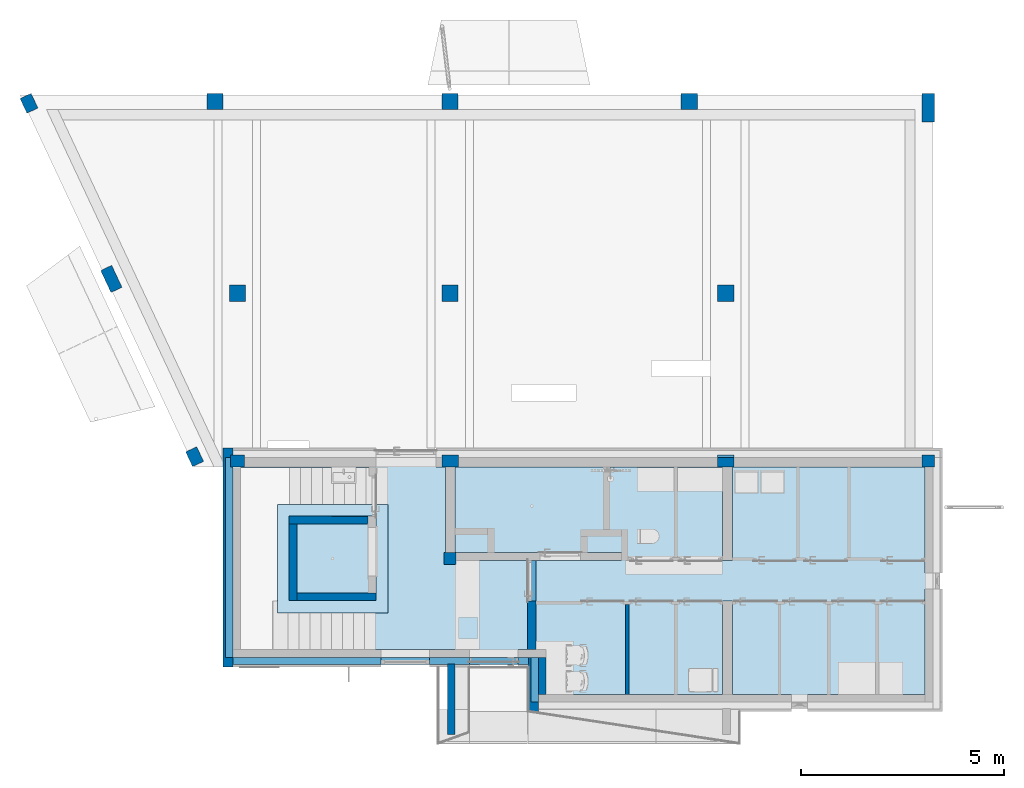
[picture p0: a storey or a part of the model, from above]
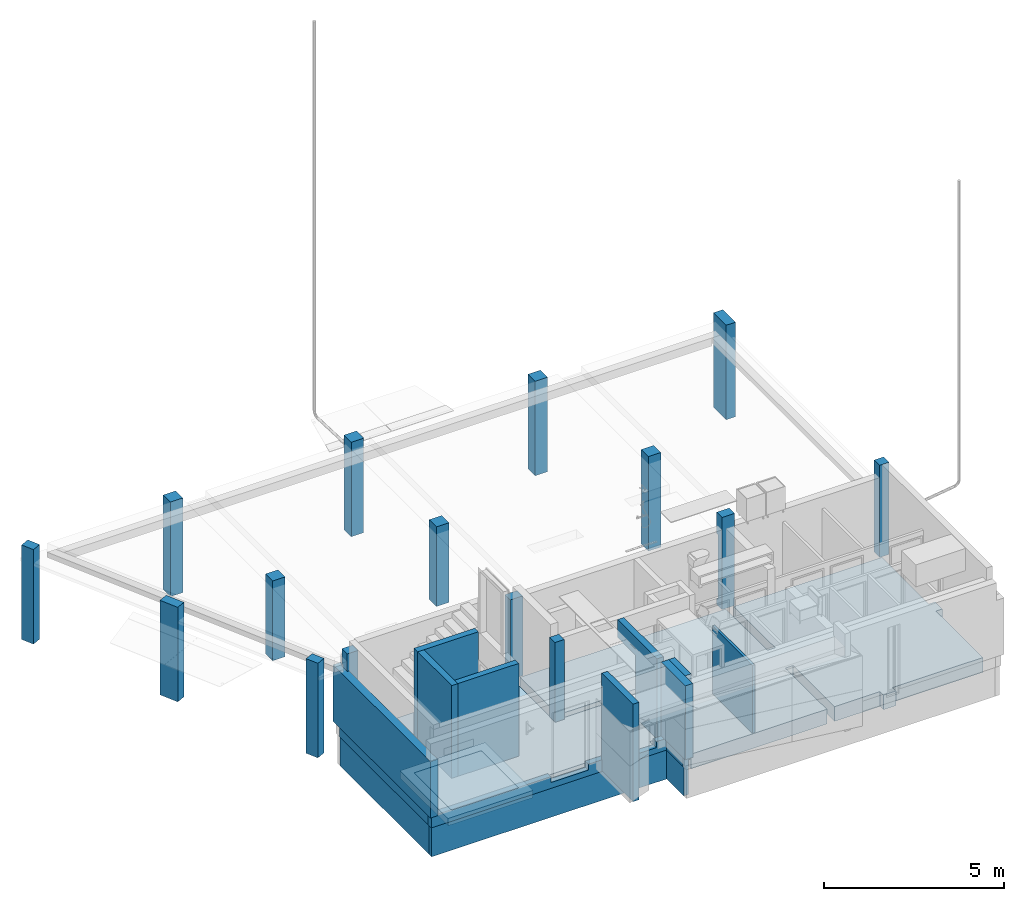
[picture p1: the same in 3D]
Properties of the parts of a building model (IFC2X3), part 1 of 3

# File
Description: ViewDefinition [CoordinationView_V2.0], RevitIdentifiers [ContentGUID: f1a5ce15-1688-4ac3-b104-60991c236845, VersionGUID: 6ece28bc-73fe-4a4b-b3da-6d619ce2e189, NumberOfSaves: 295], CoordinateReference [CoordinateBase: Shared Coordinates, ProjectSite: Internal]
File name: Kiili14_AR.ifc
Time: 2025-11-07T10:45:03+02:00
Written by: ODA SDAI 24.12
Made in: Autodesk Revit 25.4.20.11 (ENU) - IFC 25.4.20.11

# IfcProject, KLI1425
LongName: Kiili 14 korterelamu; Phase: PP

# IfcSite, Default
RefLatitude: 42, 24, 53, 508911; RefLongitude: -71, -15, -29, -58837; RefElevation: 0 mm

# IfcBuilding
Pset_BuildingCommon - NumberOfStoreys: 6

# IfcBuildingStorey: Level:Building Story. Project Base Point (6)
Pset_AirSideSystemInformation - sets with these values: 2
Name | LongName = Name | Elevation (mm)
1K | 1K | 0
2K | 2K | 3125
3K | 3K | 6295
4K | 4K | 9465
5K | 5K | 12811
Parapet | Parapet | 16500

# IfcSpace: Abir. 2-4.7:285176, 2-4.7
In: 2K
LongName: Abir.; InteriorOrExteriorSpace: INTERNAL
Pset_AirSideSystemInformation - Name: Abir.; sets with these values: 2
Pset_SpaceCommon - Reference: Abir. 2-4.7

# IfcSpace: Abir. 3-8.7:285861, 3-8.7
In: 3K
LongName: Abir.; InteriorOrExteriorSpace: INTERNAL
Pset_AirSideSystemInformation - Name: Abir.; sets with these values: 2
Pset_SpaceCommon - Reference: Abir. 3-8.7

# IfcSpace: Abiruum 5-12.9:296837, 5-12.9
In: 5K
LongName: Abiruum; InteriorOrExteriorSpace: INTERNAL
Pset_AirSideSystemInformation - Name: Abiruum; sets with these values: 2
Pset_SpaceCommon - Reference: Abiruum 5-12.9

# IfcSpace: Elutuba-köök 2-1.2:284823, 2-1.2
In: 2K
LongName: Elutuba-köök; InteriorOrExteriorSpace: INTERNAL
Pset_AirSideSystemInformation - Name: Elutuba-köök; sets with these values: 2
Pset_SpaceCommon - Reference: Elutuba-köök 2-1.2

# IfcSpace: Elutuba-köök 2-2.2:284964, 2-2.2
In: 2K
LongName: Elutuba-köök; InteriorOrExteriorSpace: INTERNAL
Pset_AirSideSystemInformation - Name: Elutuba-köök; sets with these values: 2
Pset_SpaceCommon - Reference: Elutuba-köök 2-2.2

# IfcSpace: Elutuba-köök 2-3.2:284970, 2-3.2
In: 2K
LongName: Elutuba-köök; InteriorOrExteriorSpace: INTERNAL
Pset_AirSideSystemInformation - Name: Elutuba-köök; sets with these values: 2
Pset_SpaceCommon - Reference: Elutuba-köök 2-3.2

# IfcSpace: Elutuba-köök 2-4.2:285173, 2-4.2
In: 2K
LongName: Elutuba-köök; InteriorOrExteriorSpace: INTERNAL
Pset_AirSideSystemInformation - Name: Elutuba-köök; sets with these values: 2
Pset_SpaceCommon - Reference: Elutuba-köök 2-4.2

# IfcSpace: Elutuba-köök 3-5.2:285785, 3-5.2
In: 3K
LongName: Elutuba-köök; InteriorOrExteriorSpace: INTERNAL
Pset_AirSideSystemInformation - Name: Elutuba-köök; sets with these values: 2
Pset_SpaceCommon - Reference: Elutuba-köök 3-5.2

# IfcSpace: Elutuba-köök 3-6.2:285788, 3-6.2
In: 3K
LongName: Elutuba-köök; InteriorOrExteriorSpace: INTERNAL
Pset_AirSideSystemInformation - Name: Elutuba-köök; sets with these values: 2
Pset_SpaceCommon - Reference: Elutuba-köök 3-6.2

# IfcSpace: Elutuba-köök 3-7.2:285791, 3-7.2
In: 3K
LongName: Elutuba-köök; InteriorOrExteriorSpace: INTERNAL
Pset_AirSideSystemInformation - Name: Elutuba-köök; sets with these values: 2
Pset_SpaceCommon - Reference: Elutuba-köök 3-7.2

# IfcSpace: Elutuba-köök 3-8.2:285794, 3-8.2
In: 3K
LongName: Elutuba-köök; InteriorOrExteriorSpace: INTERNAL
Pset_AirSideSystemInformation - Name: Elutuba-köök; sets with these values: 2
Pset_SpaceCommon - Reference: Elutuba-köök 3-8.2

# IfcSpace: Elutuba-köök 4-10.2:295655, 4-10.2
In: 4K
LongName: Elutuba-köök; InteriorOrExteriorSpace: INTERNAL
Pset_AirSideSystemInformation - Name: Elutuba-köök; sets with these values: 2
Pset_SpaceCommon - Reference: Elutuba-köök 4-10.2

# IfcSpace: Elutuba-köök 4-11.2:295363, 4-11.2
In: 4K
LongName: Elutuba-köök; InteriorOrExteriorSpace: INTERNAL
Pset_AirSideSystemInformation - Name: Elutuba-köök; sets with these values: 2
Pset_SpaceCommon - Reference: Elutuba-köök 4-11.2

# IfcSpace: Elutuba-köök 4-9.2:295332, 4-9.2
In: 4K
LongName: Elutuba-köök; InteriorOrExteriorSpace: INTERNAL
Pset_AirSideSystemInformation - Name: Elutuba-köök; sets with these values: 2
Pset_SpaceCommon - Reference: Elutuba-köök 4-9.2

# IfcSpace: Esik 2-1.1:284817, 2-1.1
In: 2K
LongName: Esik; InteriorOrExteriorSpace: INTERNAL
Pset_AirSideSystemInformation - Name: Esik; sets with these values: 2
Pset_SpaceCommon - Reference: Esik 2-1.1

# IfcSpace: Esik 2-2.1:284829, 2-2.1
In: 2K
LongName: Esik; InteriorOrExteriorSpace: INTERNAL
Pset_AirSideSystemInformation - Name: Esik; sets with these values: 2
Pset_SpaceCommon - Reference: Esik 2-2.1

# IfcSpace: Esik 2-3.1:284967, 2-3.1
In: 2K
LongName: Esik; InteriorOrExteriorSpace: INTERNAL
Pset_AirSideSystemInformation - Name: Esik; sets with these values: 2
Pset_SpaceCommon - Reference: Esik 2-3.1

# IfcSpace: Esik 2-4.1:285167, 2-4.1
In: 2K
LongName: Esik; InteriorOrExteriorSpace: INTERNAL
Pset_AirSideSystemInformation - Name: Esik; sets with these values: 2
Pset_SpaceCommon - Reference: Esik 2-4.1

# IfcSpace: Esik 3-5.1:285908, 3-5.1
In: 3K
LongName: Esik; InteriorOrExteriorSpace: INTERNAL
Pset_AirSideSystemInformation - Name: Esik; sets with these values: 2
Pset_SpaceCommon - Reference: Esik 3-5.1

# IfcSpace: Esik 3-6.1:285911, 3-6.1
In: 3K
LongName: Esik; InteriorOrExteriorSpace: INTERNAL
Pset_AirSideSystemInformation - Name: Esik; sets with these values: 2
Pset_SpaceCommon - Reference: Esik 3-6.1

# IfcSpace: Esik 3-7.1:285915, 3-7.1
In: 3K
LongName: Esik; InteriorOrExteriorSpace: INTERNAL
Pset_AirSideSystemInformation - Name: Esik; sets with these values: 2
Pset_SpaceCommon - Reference: Esik 3-7.1

# IfcSpace: Esik 3-8.1:285919, 3-8.1
In: 3K
LongName: Esik; InteriorOrExteriorSpace: INTERNAL
Pset_AirSideSystemInformation - Name: Esik; sets with these values: 2
Pset_SpaceCommon - Reference: Esik 3-8.1

# IfcSpace: Esik 4-10.1:295348, 4-10.1
In: 4K
LongName: Esik; InteriorOrExteriorSpace: INTERNAL
Pset_AirSideSystemInformation - Name: Esik; sets with these values: 2
Pset_SpaceCommon - Reference: Esik 4-10.1

# IfcSpace: Esik 4-11.1:295360, 4-11.1
In: 4K
LongName: Esik; InteriorOrExteriorSpace: INTERNAL
Pset_AirSideSystemInformation - Name: Esik; sets with these values: 2
Pset_SpaceCommon - Reference: Esik 4-11.1

# IfcSpace: Esik 4-9.1:295547, 4-9.1
In: 4K
LongName: Esik; InteriorOrExteriorSpace: INTERNAL
Pset_AirSideSystemInformation - Name: Esik; sets with these values: 2
Pset_SpaceCommon - Reference: Esik 4-9.1

# IfcSpace: Esik 5-12.1:509769, 5-12.1
In: 5K
LongName: Esik; InteriorOrExteriorSpace: INTERNAL
Pset_AirSideSystemInformation - Name: Esik; sets with these values: 2
Pset_SpaceCommon - Reference: Esik 5-12.1

# IfcSpace: Garder. 4-11.4:295954, 4-11.4
In: 4K
LongName: Garder.; InteriorOrExteriorSpace: INTERNAL
Pset_AirSideSystemInformation - Name: Garder.; sets with these values: 2
Pset_SpaceCommon - Reference: Garder. 4-11.4

# IfcSpace: Garder. 5-12.2:296507, 5-12.2
In: 5K
LongName: Garder.; InteriorOrExteriorSpace: INTERNAL
Pset_AirSideSystemInformation - Name: Garder.; sets with these values: 2
Pset_SpaceCommon - Reference: Garder. 5-12.2

# IfcSpace: Koridor 1-0.5:490513, 1-0.5
In: 1K
LongName: Koridor; InteriorOrExteriorSpace: INTERNAL
Pset_AirSideSystemInformation - Name: Koridor; sets with these values: 2
Pset_SpaceCommon - Reference: Koridor 1-0.5

# IfcSpace: Koridor 2-0.3:285197, 2-0.3
In: 2K
LongName: Koridor; InteriorOrExteriorSpace: INTERNAL
Pset_AirSideSystemInformation - Name: Koridor; sets with these values: 2
Pset_SpaceCommon - Reference: Koridor 2-0.3

# IfcSpace: Koridor 2-4.3:285179, 2-4.3
In: 2K
LongName: Koridor; InteriorOrExteriorSpace: INTERNAL
Pset_AirSideSystemInformation - Name: Koridor; sets with these values: 2
Pset_SpaceCommon - Reference: Koridor 2-4.3

# IfcSpace: Koridor 3-0.3:286145, 3-0.3
In: 3K
LongName: Koridor; InteriorOrExteriorSpace: INTERNAL
Pset_AirSideSystemInformation - Name: Koridor; sets with these values: 2
Pset_SpaceCommon - Reference: Koridor 3-0.3

# IfcSpace: Koridor 3-8.3:285852, 3-8.3
In: 3K
LongName: Koridor; InteriorOrExteriorSpace: INTERNAL
Pset_AirSideSystemInformation - Name: Koridor; sets with these values: 2
Pset_SpaceCommon - Reference: Koridor 3-8.3

# IfcSpace: Koridor 4-0.3:295980, 4-0.3
In: 4K
LongName: Koridor; InteriorOrExteriorSpace: INTERNAL
Pset_AirSideSystemInformation - Name: Koridor; sets with these values: 2
Pset_SpaceCommon - Reference: Koridor 4-0.3

# IfcSpace: Koridor 4-9.3:295556, 4-9.3
In: 4K
LongName: Koridor; InteriorOrExteriorSpace: INTERNAL
Pset_AirSideSystemInformation - Name: Koridor; sets with these values: 2
Pset_SpaceCommon - Reference: Koridor 4-9.3

# IfcSpace: Koridor 5-12.3:510105, 5-12.3
In: 5K
LongName: Koridor; InteriorOrExteriorSpace: INTERNAL
Pset_AirSideSystemInformation - Name: Koridor; sets with these values: 2
Pset_SpaceCommon - Reference: Koridor 5-12.3

# IfcSpace: Koristaja 1-0.3:497457, 1-0.3
In: 1K
LongName: Koristaja; InteriorOrExteriorSpace: INTERNAL
Pset_AirSideSystemInformation - Name: Koristaja; sets with these values: 2
Pset_SpaceCommon - Reference: Koristaja 1-0.3

# IfcSpace: Leil 5-12.14:510385, 5-12.14
In: 5K
LongName: Leil; InteriorOrExteriorSpace: INTERNAL
Pset_AirSideSystemInformation - Name: Leil; sets with these values: 2
Pset_SpaceCommon - Reference: Leil 5-12.14

# IfcSpace: Lift 1-0.2:517327, 1-0.2
In: 1K
LongName: Lift; InteriorOrExteriorSpace: INTERNAL
Pset_AirSideSystemInformation - Name: Lift; sets with these values: 2
Pset_SpaceCommon - Reference: Lift 1-0.2

# IfcSpace: Lift 2-0.2:285191, 2-0.2
In: 2K
LongName: Lift; InteriorOrExteriorSpace: INTERNAL
Pset_AirSideSystemInformation - Name: Lift; sets with these values: 2
Pset_SpaceCommon - Reference: Lift 2-0.2

# IfcSpace: Lift 3-0.2:286151, 3-0.2
In: 3K
LongName: Lift; InteriorOrExteriorSpace: INTERNAL
Pset_AirSideSystemInformation - Name: Lift; sets with these values: 2
Pset_SpaceCommon - Reference: Lift 3-0.2

# IfcSpace: Lift 4-0.2:295974, 4-0.2
In: 4K
LongName: Lift; InteriorOrExteriorSpace: INTERNAL
Pset_AirSideSystemInformation - Name: Lift; sets with these values: 2
Pset_SpaceCommon - Reference: Lift 4-0.2

# IfcSpace: Lift 5-0.2:296583, 5-0.2
In: 5K
LongName: Lift; InteriorOrExteriorSpace: INTERNAL
Pset_AirSideSystemInformation - Name: Lift; sets with these values: 2
Pset_SpaceCommon - Reference: Lift 5-0.2

# IfcSpace: Panipaik 1-0.10:490445, 1-0.10
In: 1K
LongName: Panipaik; InteriorOrExteriorSpace: INTERNAL
Pset_AirSideSystemInformation - Name: Panipaik; sets with these values: 2
Pset_SpaceCommon - Reference: Panipaik 1-0.10

# IfcSpace: Panipaik 1-0.11:490448, 1-0.11
In: 1K
LongName: Panipaik; InteriorOrExteriorSpace: INTERNAL
Pset_AirSideSystemInformation - Name: Panipaik; sets with these values: 2
Pset_SpaceCommon - Reference: Panipaik 1-0.11

# IfcSpace: Panipaik 1-0.12:490451, 1-0.12
In: 1K
LongName: Panipaik; InteriorOrExteriorSpace: INTERNAL
Pset_AirSideSystemInformation - Name: Panipaik; sets with these values: 2
Pset_SpaceCommon - Reference: Panipaik 1-0.12

# IfcSpace: Panipaik 1-0.13:490454, 1-0.13
In: 1K
LongName: Panipaik; InteriorOrExteriorSpace: INTERNAL
Pset_AirSideSystemInformation - Name: Panipaik; sets with these values: 2
Pset_SpaceCommon - Reference: Panipaik 1-0.13

# IfcSpace: Panipaik 1-0.14:490457, 1-0.14
In: 1K
LongName: Panipaik; InteriorOrExteriorSpace: INTERNAL
Pset_AirSideSystemInformation - Name: Panipaik; sets with these values: 2
Pset_SpaceCommon - Reference: Panipaik 1-0.14

# IfcSpace: Panipaik 1-0.15:490460, 1-0.15
In: 1K
LongName: Panipaik; InteriorOrExteriorSpace: INTERNAL
Pset_AirSideSystemInformation - Name: Panipaik; sets with these values: 2
Pset_SpaceCommon - Reference: Panipaik 1-0.15

# IfcSpace: Panipaik 1-0.16:490463, 1-0.16
In: 1K
LongName: Panipaik; InteriorOrExteriorSpace: INTERNAL
Pset_AirSideSystemInformation - Name: Panipaik; sets with these values: 2
Pset_SpaceCommon - Reference: Panipaik 1-0.16

# IfcSpace: Panipaik 1-0.17:490466, 1-0.17
In: 1K
LongName: Panipaik; InteriorOrExteriorSpace: INTERNAL
Pset_AirSideSystemInformation - Name: Panipaik; sets with these values: 2
Pset_SpaceCommon - Reference: Panipaik 1-0.17

# IfcSpace: Panipaik 1-0.6:490433, 1-0.6
In: 1K
LongName: Panipaik; InteriorOrExteriorSpace: INTERNAL
Pset_AirSideSystemInformation - Name: Panipaik; sets with these values: 2
Pset_SpaceCommon - Reference: Panipaik 1-0.6

# IfcSpace: Panipaik 1-0.7:490436, 1-0.7
In: 1K
LongName: Panipaik; InteriorOrExteriorSpace: INTERNAL
Pset_AirSideSystemInformation - Name: Panipaik; sets with these values: 2
Pset_SpaceCommon - Reference: Panipaik 1-0.7

# IfcSpace: Panipaik 1-0.8:490439, 1-0.8
In: 1K
LongName: Panipaik; InteriorOrExteriorSpace: INTERNAL
Pset_AirSideSystemInformation - Name: Panipaik; sets with these values: 2
Pset_SpaceCommon - Reference: Panipaik 1-0.8

# IfcSpace: Panipaik 1-0.9:490442, 1-0.9
In: 1K
LongName: Panipaik; InteriorOrExteriorSpace: INTERNAL
Pset_AirSideSystemInformation - Name: Panipaik; sets with these values: 2
Pset_SpaceCommon - Reference: Panipaik 1-0.9

# IfcSpace: Sauna eesr. 5-12.6:296002, 5-12.6
In: 5K
LongName: Sauna eesr.; InteriorOrExteriorSpace: INTERNAL
Pset_AirSideSystemInformation - Name: Sauna eesr.; sets with these values: 2
Pset_SpaceCommon - Reference: Sauna eesr. 5-12.6

# IfcSpace: Tehnor. 1-0.4:490507, 1-0.4
In: 1K
LongName: Tehnor.; InteriorOrExteriorSpace: INTERNAL
Pset_AirSideSystemInformation - Name: Tehnor.; sets with these values: 2
Pset_SpaceCommon - Reference: Tehnor. 1-0.4

# IfcSpace: Trepikoda 1-0.1:517294, 1-0.1
In: 1K
LongName: Trepikoda; InteriorOrExteriorSpace: INTERNAL
Pset_AirSideSystemInformation - Name: Trepikoda; sets with these values: 2
Pset_SpaceCommon - Reference: Trepikoda 1-0.1

# IfcSpace: Trepikoda 2-0.1:285194, 2-0.1
In: 2K
LongName: Trepikoda; InteriorOrExteriorSpace: INTERNAL
Pset_AirSideSystemInformation - Name: Trepikoda; sets with these values: 2
Pset_SpaceCommon - Reference: Trepikoda 2-0.1

# IfcSpace: Trepikoda 3-0.1:286157, 3-0.1
In: 3K
LongName: Trepikoda; InteriorOrExteriorSpace: INTERNAL
Pset_AirSideSystemInformation - Name: Trepikoda; sets with these values: 2
Pset_SpaceCommon - Reference: Trepikoda 3-0.1

# IfcSpace: Trepikoda 4-0.1:295968, 4-0.1
In: 4K
LongName: Trepikoda; InteriorOrExteriorSpace: INTERNAL
Pset_AirSideSystemInformation - Name: Trepikoda; sets with these values: 2
Pset_SpaceCommon - Reference: Trepikoda 4-0.1

# IfcSpace: Trepikoda 5-0.1:296577, 5-0.1
In: 5K
LongName: Trepikoda; InteriorOrExteriorSpace: INTERNAL
Pset_AirSideSystemInformation - Name: Trepikoda; sets with these values: 2
Pset_SpaceCommon - Reference: Trepikoda 5-0.1

# IfcSpace: Tuba 2-1.3:284826, 2-1.3
In: 2K
LongName: Tuba; InteriorOrExteriorSpace: INTERNAL
Pset_AirSideSystemInformation - Name: Tuba; sets with these values: 2
Pset_SpaceCommon - Reference: Tuba 2-1.3

# IfcSpace: Tuba 2-2.3:284835, 2-2.3
In: 2K
LongName: Tuba; InteriorOrExteriorSpace: INTERNAL
Pset_AirSideSystemInformation - Name: Tuba; sets with these values: 2
Pset_SpaceCommon - Reference: Tuba 2-2.3

# IfcSpace: Tuba 2-3.3:284977, 2-3.3
In: 2K
LongName: Tuba; InteriorOrExteriorSpace: INTERNAL
Pset_AirSideSystemInformation - Name: Tuba; sets with these values: 2
Pset_SpaceCommon - Reference: Tuba 2-3.3

# IfcSpace: Tuba 2-4.4:285182, 2-4.4
In: 2K
LongName: Tuba; InteriorOrExteriorSpace: INTERNAL
Pset_AirSideSystemInformation - Name: Tuba; sets with these values: 2
Pset_SpaceCommon - Reference: Tuba 2-4.4

# IfcSpace: Tuba 2-4.5:285185, 2-4.5
In: 2K
LongName: Tuba; InteriorOrExteriorSpace: INTERNAL
Pset_AirSideSystemInformation - Name: Tuba; sets with these values: 2
Pset_SpaceCommon - Reference: Tuba 2-4.5

# IfcSpace: Tuba 3-5.3:285767, 3-5.3
In: 3K
LongName: Tuba; InteriorOrExteriorSpace: INTERNAL
Pset_AirSideSystemInformation - Name: Tuba; sets with these values: 2
Pset_SpaceCommon - Reference: Tuba 3-5.3

# IfcSpace: Tuba 3-6.3:285770, 3-6.3
In: 3K
LongName: Tuba; InteriorOrExteriorSpace: INTERNAL
Pset_AirSideSystemInformation - Name: Tuba; sets with these values: 2
Pset_SpaceCommon - Reference: Tuba 3-6.3

# IfcSpace: Tuba 3-7.3:285773, 3-7.3
In: 3K
LongName: Tuba; InteriorOrExteriorSpace: INTERNAL
Pset_AirSideSystemInformation - Name: Tuba; sets with these values: 2
Pset_SpaceCommon - Reference: Tuba 3-7.3

# IfcSpace: Tuba 3-8.4:285776, 3-8.4
In: 3K
LongName: Tuba; InteriorOrExteriorSpace: INTERNAL
Pset_AirSideSystemInformation - Name: Tuba; sets with these values: 2
Pset_SpaceCommon - Reference: Tuba 3-8.4

# IfcSpace: Tuba 3-8.5:285779, 3-8.5
In: 3K
LongName: Tuba; InteriorOrExteriorSpace: INTERNAL
Pset_AirSideSystemInformation - Name: Tuba; sets with these values: 2
Pset_SpaceCommon - Reference: Tuba 3-8.5

# IfcSpace: Tuba 4-10.3:295354, 4-10.3
In: 4K
LongName: Tuba; InteriorOrExteriorSpace: INTERNAL
Pset_AirSideSystemInformation - Name: Tuba; sets with these values: 2
Pset_SpaceCommon - Reference: Tuba 4-10.3

# IfcSpace: Tuba 4-11.3:295370, 4-11.3
In: 4K
LongName: Tuba; InteriorOrExteriorSpace: INTERNAL
Pset_AirSideSystemInformation - Name: Tuba; sets with these values: 2
Pset_SpaceCommon - Reference: Tuba 4-11.3

# IfcSpace: Tuba 4-9.4:295336, 4-9.4
In: 4K
LongName: Tuba; InteriorOrExteriorSpace: INTERNAL
Pset_AirSideSystemInformation - Name: Tuba; sets with these values: 2
Pset_SpaceCommon - Reference: Tuba 4-9.4

# IfcSpace: Tuba 4-9.5:295339, 4-9.5
In: 4K
LongName: Tuba; InteriorOrExteriorSpace: INTERNAL
Pset_AirSideSystemInformation - Name: Tuba; sets with these values: 2
Pset_SpaceCommon - Reference: Tuba 4-9.5

# IfcSpace: Tuba 5-12.10:296516, 5-12.10
In: 5K
LongName: Tuba; InteriorOrExteriorSpace: INTERNAL
Pset_AirSideSystemInformation - Name: Tuba; sets with these values: 2
Pset_SpaceCommon - Reference: Tuba 5-12.10

# IfcSpace: Tuba 5-12.12:295989, 5-12.12
In: 5K
LongName: Tuba; InteriorOrExteriorSpace: INTERNAL
Pset_AirSideSystemInformation - Name: Tuba; sets with these values: 2
Pset_SpaceCommon - Reference: Tuba 5-12.12

# IfcSpace: Tuba 5-12.13:295993, 5-12.13
In: 5K
LongName: Tuba; InteriorOrExteriorSpace: INTERNAL
Pset_AirSideSystemInformation - Name: Tuba; sets with these values: 2
Pset_SpaceCommon - Reference: Tuba 5-12.13

# IfcSpace: Tuba 5-12.4:295999, 5-12.4
In: 5K
LongName: Tuba; InteriorOrExteriorSpace: INTERNAL
Pset_AirSideSystemInformation - Name: Tuba; sets with these values: 2
Pset_SpaceCommon - Reference: Tuba 5-12.4

# IfcSpace: Tuba 5-12.7:296005, 5-12.7
In: 5K
LongName: Tuba; InteriorOrExteriorSpace: INTERNAL
Pset_AirSideSystemInformation - Name: Tuba; sets with these values: 2
Pset_SpaceCommon - Reference: Tuba 5-12.7

# IfcSpace: Vannit. 2-1.4:284820, 2-1.4
In: 2K
LongName: Vannit.; InteriorOrExteriorSpace: INTERNAL
Pset_AirSideSystemInformation - Name: Vannit.; sets with these values: 2
Pset_SpaceCommon - Reference: Vannit. 2-1.4

# IfcSpace: Vannit. 2-2.4:284832, 2-2.4
In: 2K
LongName: Vannit.; InteriorOrExteriorSpace: INTERNAL
Pset_AirSideSystemInformation - Name: Vannit.; sets with these values: 2
Pset_SpaceCommon - Reference: Vannit. 2-2.4

# IfcSpace: Vannit. 2-3.4:284974, 2-3.4
In: 2K
LongName: Vannit.; InteriorOrExteriorSpace: INTERNAL
Pset_AirSideSystemInformation - Name: Vannit.; sets with these values: 2
Pset_SpaceCommon - Reference: Vannit. 2-3.4

# IfcSpace: Vannit. 2-4.6:285170, 2-4.6
In: 2K
LongName: Vannit.; InteriorOrExteriorSpace: INTERNAL
Pset_AirSideSystemInformation - Name: Vannit.; sets with these values: 2
Pset_SpaceCommon - Reference: Vannit. 2-4.6

# IfcSpace: Vannit. 3-5.4:285843, 3-5.4
In: 3K
LongName: Vannit.; InteriorOrExteriorSpace: INTERNAL
Pset_AirSideSystemInformation - Name: Vannit.; sets with these values: 2
Pset_SpaceCommon - Reference: Vannit. 3-5.4

# IfcSpace: Vannit. 3-6.4:285846, 3-6.4
In: 3K
LongName: Vannit.; InteriorOrExteriorSpace: INTERNAL
Pset_AirSideSystemInformation - Name: Vannit.; sets with these values: 2
Pset_SpaceCommon - Reference: Vannit. 3-6.4

# IfcSpace: Vannit. 3-7.4:285849, 3-7.4
In: 3K
LongName: Vannit.; InteriorOrExteriorSpace: INTERNAL
Pset_AirSideSystemInformation - Name: Vannit.; sets with these values: 2
Pset_SpaceCommon - Reference: Vannit. 3-7.4

# IfcSpace: Vannit. 3-8.6:285855, 3-8.6
In: 3K
LongName: Vannit.; InteriorOrExteriorSpace: INTERNAL
Pset_AirSideSystemInformation - Name: Vannit.; sets with these values: 2
Pset_SpaceCommon - Reference: Vannit. 3-8.6

# IfcSpace: Vannit. 4-10.4:295351, 4-10.4
In: 4K
LongName: Vannit.; InteriorOrExteriorSpace: INTERNAL
Pset_AirSideSystemInformation - Name: Vannit.; sets with these values: 2
Pset_SpaceCommon - Reference: Vannit. 4-10.4

# IfcSpace: Vannit. 4-11.5:295367, 4-11.5
In: 4K
LongName: Vannit.; InteriorOrExteriorSpace: INTERNAL
Pset_AirSideSystemInformation - Name: Vannit.; sets with these values: 2
Pset_SpaceCommon - Reference: Vannit. 4-11.5

# IfcSpace: Vannit. 4-9.6:295342, 4-9.6
In: 4K
LongName: Vannit.; InteriorOrExteriorSpace: INTERNAL
Pset_AirSideSystemInformation - Name: Vannit.; sets with these values: 2
Pset_SpaceCommon - Reference: Vannit. 4-9.6

# IfcSpace: Vannit. 5-12.11:295996, 5-12.11
In: 5K
LongName: Vannit.; InteriorOrExteriorSpace: INTERNAL
Pset_AirSideSystemInformation - Name: Vannit.; sets with these values: 2
Pset_SpaceCommon - Reference: Vannit. 5-12.11

# IfcSpace: Vannit. 5-12.8:296008, 5-12.8
In: 5K
LongName: Vannit.; InteriorOrExteriorSpace: INTERNAL
Pset_AirSideSystemInformation - Name: Vannit.; sets with these values: 2
Pset_SpaceCommon - Reference: Vannit. 5-12.8

# IfcSpace: WC 5-12.5:296011, 5-12.5
In: 5K
LongName: WC; InteriorOrExteriorSpace: INTERNAL
Pset_AirSideSystemInformation - Name: WC; sets with these values: 2
Pset_SpaceCommon - Reference: WC 5-12.5

# IfcBeam: M_Precast Beam - Double-Sided Corbel - Straight Ends:T-tala (3)
In: 2K
Type - PredefinedType: BEAM
Type - Pset_BeamCommon - LoadBearing: yes
Material: _K. Betoon. Armeeritud. Monteeritav
Pset_BeamCommon - IsExternal: no; Reference: T-tala; Span: 8650 mm; Slope: 0 deg
Pset_QuantityTakeOff - Reference: T-tala; sets with these values: 2
Name (M_Precast Beam - Double-Sided Corbel - Straight Ends:T-tala:...)
669460
670158
670166

# IfcBeam: M_Precast Beam - One-Sided Corbel - Straight Ends:400x600 (2)
In: 2K
Type - PredefinedType: BEAM
Type - Pset_BeamCommon - LoadBearing: yes
Material: _K. Betoon. Armeeritud. Monteeritav
Pset_BeamCommon - IsExternal: no; Slope: 0 deg; Reference: 400x600
Pset_QuantityTakeOff - Reference: 400x600; sets with these values: 2
Name (M_Precast Beam - One-Sided Corbel - Straight Ends:400x600:...) | Span (mm)
670254 | 8805.02
670708 | 10031.2

# IfcBeam: M_Precast-Rectangular Beam:400 RB 800, M_Precast-Rectangular Beam:400 RB 800:671603
In: 2K
Type - PredefinedType: BEAM
Type - Pset_BeamCommon - LoadBearing: yes
Material: _K. Betoon. Armeeritud. Monteeritav
Pset_BeamCommon - IsExternal: no; Slope: 0 deg; Reference: 400 RB 800; Span: 22267.1 mm
Pset_QuantityTakeOff - Reference: 400 RB 800; sets with these values: 2

# IfcBuildingElementPart (465)
Name (Part:...) | In | Material
713097 | 2K | _K. Välisviimistlus. Alumiinium-komposiitplaat
713098 | 2K | _K. Õhk. Roov. Fassaadikatte alusroov. Horisontaalne. 25 mm
713099 | 2K | _K. Õhk. Roov. Fassaadikatte alusroov. Horisontaalne. 25 mm
713100 | 2K | _K. Õhk. Roov. Fassaadikatte alusroov. Horisontaalne. 25 mm
713101 | 2K | _K. Õhk. Roov. Fassaadikatte alusroov. Horisontaalne. 25 mm
713102 | 2K | _K. Õhk. Roov. Fassaadikatte alusroov. Horisontaalne. 25 mm
713103 | 2K | _K. Õhk. Roov. Fassaadikatte alusroov. Horisontaalne. 25 mm
713104 | 2K | _K. Õhk. Roov. Fassaadikatte alusroov. Horisontaalne. 25 mm
713105 | 2K | _K. Õhk. Roov. Fassaadikatte alusroov. Horisontaalne. 25 mm
713106 | 2K | _K. Õhk. Roov. Fassaadikatte alusroov. Horisontaalne. 25 mm
713107 | 2K | _K. Õhk. Roov. Fassaadikatte alusroov. Horisontaalne. 25 mm
713108 | 2K | _K. Õhk. Roov. Fassaadikatte alusroov. Horisontaalne. 25 mm
713109 | 2K | _K. Õhk. Roov. Fassaadikatte alusroov. Horisontaalne. 25 mm
713110 | 2K | _K. Õhk. Roov. Fassaadikatte alusroov. Horisontaalne. 25 mm
713111 | 2K | _K. Välisviimistlus. Alumiinium-komposiitplaat
713112 | 2K | _K. Välisviimistlus. Alumiinium-komposiitplaat
713113 | 2K | _K. Välisviimistlus. Alumiinium-komposiitplaat
713114 | 2K | _K. Välisviimistlus. Alumiinium-komposiitplaat
713115 | 2K | _K. Välisviimistlus. Alumiinium-komposiitplaat
713116 | 2K | _K. Välisviimistlus. Alumiinium-komposiitplaat
713117 | 2K | _K. Välisviimistlus. Alumiinium-komposiitplaat
713118 | 2K | _K. Välisviimistlus. Alumiinium-komposiitplaat
713119 | 2K | _K. Välisviimistlus. Alumiinium-komposiitplaat
713120 | 2K | _K. Välisviimistlus. Alumiinium-komposiitplaat
713121 | 2K | _K. Välisviimistlus. Alumiinium-komposiitplaat
713122 | 2K | _K. Välisviimistlus. Alumiinium-komposiitplaat
710677 | 2K | _K. Välisviimistlus. Alumiinium-komposiitplaat
710678 | 2K | _K. Õhk. Roov. Fassaadikatte alusroov. Horisontaalne. 25 mm
710679 | 2K | _K. Õhk. Roov. Fassaadikatte alusroov. Horisontaalne. 25 mm
710680 | 2K | _K. Õhk. Roov. Fassaadikatte alusroov. Horisontaalne. 25 mm
710681 | 2K | _K. Õhk. Roov. Fassaadikatte alusroov. Horisontaalne. 25 mm
710682 | 2K | _K. Õhk. Roov. Fassaadikatte alusroov. Horisontaalne. 25 mm
710683 | 2K | _K. Õhk. Roov. Fassaadikatte alusroov. Horisontaalne. 25 mm
710684 | 2K | _K. Õhk. Roov. Fassaadikatte alusroov. Horisontaalne. 25 mm
710685 | 2K | _K. Õhk. Roov. Fassaadikatte alusroov. Horisontaalne. 25 mm
710686 | 2K | _K. Õhk. Roov. Fassaadikatte alusroov. Horisontaalne. 25 mm
710687 | 2K | _K. Õhk. Roov. Fassaadikatte alusroov. Horisontaalne. 25 mm
710688 | 2K | _K. Õhk. Roov. Fassaadikatte alusroov. Horisontaalne. 25 mm
710689 | 2K | _K. Õhk. Roov. Fassaadikatte alusroov. Horisontaalne. 25 mm
710690 | 2K | _K. Õhk. Roov. Fassaadikatte alusroov. Horisontaalne. 25 mm
710691 | 2K | _K. Välisviimistlus. Alumiinium-komposiitplaat
710692 | 2K | _K. Välisviimistlus. Alumiinium-komposiitplaat
710693 | 2K | _K. Välisviimistlus. Alumiinium-komposiitplaat
710694 | 2K | _K. Välisviimistlus. Alumiinium-komposiitplaat
710695 | 2K | _K. Välisviimistlus. Alumiinium-komposiitplaat
710696 | 2K | _K. Välisviimistlus. Alumiinium-komposiitplaat
710697 | 2K | _K. Välisviimistlus. Alumiinium-komposiitplaat
710698 | 2K | _K. Välisviimistlus. Alumiinium-komposiitplaat
710699 | 2K | _K. Välisviimistlus. Alumiinium-komposiitplaat
710700 | 2K | _K. Välisviimistlus. Alumiinium-komposiitplaat
710701 | 2K | _K. Välisviimistlus. Alumiinium-komposiitplaat
710702 | 2K | _K. Välisviimistlus. Alumiinium-komposiitplaat
711866 | 2K | _K. Õhk. Roov. Fassaadikatte alusroov. Horisontaalne. 25 mm
711867 | 2K | _K. Õhk. Roov. Fassaadikatte alusroov. Horisontaalne. 25 mm
711868 | 2K | _K. Õhk. Roov. Fassaadikatte alusroov. Horisontaalne. 25 mm
711869 | 2K | _K. Õhk. Roov. Fassaadikatte alusroov. Horisontaalne. 25 mm
711870 | 2K | _K. Õhk. Roov. Fassaadikatte alusroov. Horisontaalne. 25 mm
711871 | 2K | _K. Õhk. Roov. Fassaadikatte alusroov. Horisontaalne. 25 mm
711872 | 2K | _K. Õhk. Roov. Fassaadikatte alusroov. Horisontaalne. 25 mm
711874 | 2K | _K. Õhk. Roov. Fassaadikatte alusroov. Horisontaalne. 25 mm
711875 | 2K | _K. Õhk. Roov. Fassaadikatte alusroov. Horisontaalne. 25 mm
711876 | 2K | _K. Õhk. Roov. Fassaadikatte alusroov. Horisontaalne. 25 mm
711877 | 2K | _K. Õhk. Roov. Fassaadikatte alusroov. Horisontaalne. 25 mm
711879 | 2K | _K. Välisviimistlus. Alumiinium-komposiitplaat
711880 | 2K | _K. Välisviimistlus. Alumiinium-komposiitplaat
711882 | 2K | _K. Välisviimistlus. Alumiinium-komposiitplaat
711883 | 2K | _K. Välisviimistlus. Alumiinium-komposiitplaat
711884 | 2K | _K. Välisviimistlus. Alumiinium-komposiitplaat
711886 | 2K | _K. Välisviimistlus. Alumiinium-komposiitplaat
711888 | 2K | _K. Välisviimistlus. Alumiinium-komposiitplaat
711889 | 2K | _K. Välisviimistlus. Alumiinium-komposiitplaat
760929 | 2K | _K. Õhk. Roov. Fassaadikatte alusroov. Horisontaalne. 25 mm
760930 | 2K | _K. Õhk. Roov. Fassaadikatte alusroov. Horisontaalne. 25 mm
760931 | 2K | _K. Välisviimistlus. Alumiinium-komposiitplaat
707545 | 2K | _K. Välisviimistlus. Alumiinium-komposiitplaat
707546 | 2K | _K. Õhk. Roov. Fassaadikatte alusroov. Horisontaalne. 25 mm
707547 | 2K | _K. Õhk. Roov. Fassaadikatte alusroov. Horisontaalne. 25 mm
707549 | 2K | _K. Õhk. Roov. Fassaadikatte alusroov. Horisontaalne. 25 mm
707550 | 2K | _K. Õhk. Roov. Fassaadikatte alusroov. Horisontaalne. 25 mm
707551 | 2K | _K. Õhk. Roov. Fassaadikatte alusroov. Horisontaalne. 25 mm
707552 | 2K | _K. Õhk. Roov. Fassaadikatte alusroov. Horisontaalne. 25 mm
707553 | 2K | _K. Õhk. Roov. Fassaadikatte alusroov. Horisontaalne. 25 mm
707554 | 2K | _K. Õhk. Roov. Fassaadikatte alusroov. Horisontaalne. 25 mm
707555 | 2K | _K. Õhk. Roov. Fassaadikatte alusroov. Horisontaalne. 25 mm
707556 | 2K | _K. Õhk. Roov. Fassaadikatte alusroov. Horisontaalne. 25 mm
707557 | 2K | _K. Õhk. Roov. Fassaadikatte alusroov. Horisontaalne. 25 mm
707558 | 2K | _K. Välisviimistlus. Alumiinium-komposiitplaat
707560 | 2K | _K. Välisviimistlus. Alumiinium-komposiitplaat
707561 | 2K | _K. Välisviimistlus. Alumiinium-komposiitplaat
707562 | 2K | _K. Välisviimistlus. Alumiinium-komposiitplaat
707563 | 2K | _K. Välisviimistlus. Alumiinium-komposiitplaat
707564 | 2K | _K. Välisviimistlus. Alumiinium-komposiitplaat
707565 | 2K | _K. Välisviimistlus. Alumiinium-komposiitplaat
707566 | 2K | _K. Välisviimistlus. Alumiinium-komposiitplaat
707567 | 2K | _K. Välisviimistlus. Alumiinium-komposiitplaat
707568 | 2K | _K. Välisviimistlus. Alumiinium-komposiitplaat
707828 | 2K | _K. Õhk. Roov. Fassaadikatte alusroov. Horisontaalne. 25 mm
707829 | 2K | _K. Õhk. Roov. Fassaadikatte alusroov. Horisontaalne. 25 mm
707830 | 2K | _K. Välisviimistlus. Alumiinium-komposiitplaat
707831 | 2K | _K. Välisviimistlus. Alumiinium-komposiitplaat
710145 | 2K | _K. Välisviimistlus. Alumiinium-komposiitplaat
710146 | 2K | _K. Õhk. Roov. Fassaadikatte alusroov. Horisontaalne. 25 mm
710147 | 2K | _K. Õhk. Roov. Fassaadikatte alusroov. Horisontaalne. 25 mm
710148 | 2K | _K. Õhk. Roov. Fassaadikatte alusroov. Horisontaalne. 25 mm
710149 | 2K | _K. Õhk. Roov. Fassaadikatte alusroov. Horisontaalne. 25 mm
710150 | 2K | _K. Õhk. Roov. Fassaadikatte alusroov. Horisontaalne. 25 mm
710151 | 2K | _K. Õhk. Roov. Fassaadikatte alusroov. Horisontaalne. 25 mm
710152 | 2K | _K. Õhk. Roov. Fassaadikatte alusroov. Horisontaalne. 25 mm
710153 | 2K | _K. Õhk. Roov. Fassaadikatte alusroov. Horisontaalne. 25 mm
710154 | 2K | _K. Õhk. Roov. Fassaadikatte alusroov. Horisontaalne. 25 mm
710155 | 2K | _K. Õhk. Roov. Fassaadikatte alusroov. Horisontaalne. 25 mm
710156 | 2K | _K. Õhk. Roov. Fassaadikatte alusroov. Horisontaalne. 25 mm
710157 | 2K | _K. Õhk. Roov. Fassaadikatte alusroov. Horisontaalne. 25 mm
710158 | 2K | _K. Õhk. Roov. Fassaadikatte alusroov. Horisontaalne. 25 mm
710159 | 2K | _K. Välisviimistlus. Alumiinium-komposiitplaat
710160 | 2K | _K. Välisviimistlus. Alumiinium-komposiitplaat
710161 | 2K | _K. Välisviimistlus. Alumiinium-komposiitplaat
710162 | 2K | _K. Välisviimistlus. Alumiinium-komposiitplaat
710163 | 2K | _K. Välisviimistlus. Alumiinium-komposiitplaat
710164 | 2K | _K. Välisviimistlus. Alumiinium-komposiitplaat
710165 | 2K | _K. Välisviimistlus. Alumiinium-komposiitplaat
710166 | 2K | _K. Välisviimistlus. Alumiinium-komposiitplaat
710167 | 2K | _K. Välisviimistlus. Alumiinium-komposiitplaat
710168 | 2K | _K. Välisviimistlus. Alumiinium-komposiitplaat
710169 | 2K | _K. Välisviimistlus. Alumiinium-komposiitplaat
710170 | 2K | _K. Välisviimistlus. Alumiinium-komposiitplaat
709193 | 2K | _K. Välisviimistlus. Alumiinium-komposiitplaat
709194 | 2K | _K. Õhk. Roov. Fassaadikatte alusroov. Horisontaalne. 25 mm
709195 | 2K | _K. Õhk. Roov. Fassaadikatte alusroov. Horisontaalne. 25 mm
709196 | 2K | _K. Õhk. Roov. Fassaadikatte alusroov. Horisontaalne. 25 mm
709198 | 2K | _K. Õhk. Roov. Fassaadikatte alusroov. Horisontaalne. 25 mm
709199 | 2K | _K. Õhk. Roov. Fassaadikatte alusroov. Horisontaalne. 25 mm
709200 | 2K | _K. Õhk. Roov. Fassaadikatte alusroov. Horisontaalne. 25 mm
709201 | 2K | _K. Õhk. Roov. Fassaadikatte alusroov. Horisontaalne. 25 mm
709203 | 2K | _K. Õhk. Roov. Fassaadikatte alusroov. Horisontaalne. 25 mm
709204 | 2K | _K. Õhk. Roov. Fassaadikatte alusroov. Horisontaalne. 25 mm
709205 | 2K | _K. Õhk. Roov. Fassaadikatte alusroov. Horisontaalne. 25 mm
709206 | 2K | _K. Õhk. Roov. Fassaadikatte alusroov. Horisontaalne. 25 mm
709207 | 2K | _K. Välisviimistlus. Alumiinium-komposiitplaat
709208 | 2K | _K. Välisviimistlus. Alumiinium-komposiitplaat
709210 | 2K | _K. Välisviimistlus. Alumiinium-komposiitplaat
709212 | 2K | _K. Välisviimistlus. Alumiinium-komposiitplaat
709215 | 2K | _K. Välisviimistlus. Alumiinium-komposiitplaat
709216 | 2K | _K. Välisviimistlus. Alumiinium-komposiitplaat
709217 | 2K | _K. Välisviimistlus. Alumiinium-komposiitplaat
760555 | 2K | _K. Õhk. Roov. Fassaadikatte alusroov. Horisontaalne. 25 mm
760556 | 2K | _K. Õhk. Roov. Fassaadikatte alusroov. Horisontaalne. 25 mm
760557 | 2K | _K. Välisviimistlus. Alumiinium-komposiitplaat
705880 | 2K | _K. Välisviimistlus. Alumiinium-komposiitplaat
705881 | 2K | _K. Õhk. Roov. Fassaadikatte alusroov. Horisontaalne. 25 mm
705882 | 2K | _K. Õhk. Roov. Fassaadikatte alusroov. Horisontaalne. 25 mm
705883 | 2K | _K. Õhk. Roov. Fassaadikatte alusroov. Horisontaalne. 25 mm
705884 | 2K | _K. Õhk. Roov. Fassaadikatte alusroov. Horisontaalne. 25 mm
705885 | 2K | _K. Õhk. Roov. Fassaadikatte alusroov. Horisontaalne. 25 mm
705886 | 2K | _K. Õhk. Roov. Fassaadikatte alusroov. Horisontaalne. 25 mm
705887 | 2K | _K. Õhk. Roov. Fassaadikatte alusroov. Horisontaalne. 25 mm
705888 | 2K | _K. Õhk. Roov. Fassaadikatte alusroov. Horisontaalne. 25 mm
705889 | 2K | _K. Õhk. Roov. Fassaadikatte alusroov. Horisontaalne. 25 mm
705890 | 2K | _K. Õhk. Roov. Fassaadikatte alusroov. Horisontaalne. 25 mm
705891 | 2K | _K. Välisviimistlus. Alumiinium-komposiitplaat
705892 | 2K | _K. Välisviimistlus. Alumiinium-komposiitplaat
705893 | 2K | _K. Välisviimistlus. Alumiinium-komposiitplaat
705894 | 2K | _K. Välisviimistlus. Alumiinium-komposiitplaat
705895 | 2K | _K. Välisviimistlus. Alumiinium-komposiitplaat
705896 | 2K | _K. Välisviimistlus. Alumiinium-komposiitplaat
705897 | 2K | _K. Välisviimistlus. Alumiinium-komposiitplaat
705898 | 2K | _K. Välisviimistlus. Alumiinium-komposiitplaat
705899 | 2K | _K. Välisviimistlus. Alumiinium-komposiitplaat
704829 | 2K | _K. Välisviimistlus. Alumiinium-komposiitplaat
704830 | 2K | _K. Õhk. Roov. Fassaadikatte alusroov. Horisontaalne. 25 mm
704831 | 2K | _K. Õhk. Roov. Fassaadikatte alusroov. Horisontaalne. 25 mm
704832 | 2K | _K. Õhk. Roov. Fassaadikatte alusroov. Horisontaalne. 25 mm
704833 | 2K | _K. Õhk. Roov. Fassaadikatte alusroov. Horisontaalne. 25 mm
704834 | 2K | _K. Õhk. Roov. Fassaadikatte alusroov. Horisontaalne. 25 mm
704835 | 2K | _K. Õhk. Roov. Fassaadikatte alusroov. Horisontaalne. 25 mm
704836 | 2K | _K. Õhk. Roov. Fassaadikatte alusroov. Horisontaalne. 25 mm
704837 | 2K | _K. Õhk. Roov. Fassaadikatte alusroov. Horisontaalne. 25 mm
704838 | 2K | _K. Õhk. Roov. Fassaadikatte alusroov. Horisontaalne. 25 mm
704839 | 2K | _K. Õhk. Roov. Fassaadikatte alusroov. Horisontaalne. 25 mm
704840 | 2K | _K. Välisviimistlus. Alumiinium-komposiitplaat
704841 | 2K | _K. Välisviimistlus. Alumiinium-komposiitplaat
704842 | 2K | _K. Välisviimistlus. Alumiinium-komposiitplaat
704843 | 2K | _K. Välisviimistlus. Alumiinium-komposiitplaat
704844 | 2K | _K. Välisviimistlus. Alumiinium-komposiitplaat
704845 | 2K | _K. Välisviimistlus. Alumiinium-komposiitplaat
704846 | 2K | _K. Välisviimistlus. Alumiinium-komposiitplaat
704847 | 2K | _K. Välisviimistlus. Alumiinium-komposiitplaat
704848 | 2K | _K. Välisviimistlus. Alumiinium-komposiitplaat
705448 | 2K | _K. Õhk. Roov. Fassaadikatte alusroov. Horisontaalne. 25 mm
705449 | 2K | _K. Õhk. Roov. Fassaadikatte alusroov. Horisontaalne. 25 mm
705450 | 2K | _K. Õhk. Roov. Fassaadikatte alusroov. Horisontaalne. 25 mm
705451 | 2K | _K. Õhk. Roov. Fassaadikatte alusroov. Horisontaalne. 25 mm
705452 | 2K | _K. Õhk. Roov. Fassaadikatte alusroov. Horisontaalne. 25 mm
705453 | 2K | _K. Õhk. Roov. Fassaadikatte alusroov. Horisontaalne. 25 mm
705454 | 2K | _K. Õhk. Roov. Fassaadikatte alusroov. Horisontaalne. 25 mm
705455 | 2K | _K. Õhk. Roov. Fassaadikatte alusroov. Horisontaalne. 25 mm
705456 | 2K | _K. Õhk. Roov. Fassaadikatte alusroov. Horisontaalne. 25 mm
705457 | 2K | _K. Välisviimistlus. Alumiinium-komposiitplaat
705458 | 2K | _K. Välisviimistlus. Alumiinium-komposiitplaat
705461 | 2K | _K. Välisviimistlus. Alumiinium-komposiitplaat
705462 | 2K | _K. Välisviimistlus. Alumiinium-komposiitplaat
705464 | 2K | _K. Välisviimistlus. Alumiinium-komposiitplaat
705465 | 2K | _K. Välisviimistlus. Alumiinium-komposiitplaat
674171 | 2K | _K. Õhk. Roov. Fassaadikatte alusroov. Horisontaalne. 25 mm
674172 | 2K | _K. Õhk. Roov. Fassaadikatte alusroov. Horisontaalne. 25 mm
674173 | 2K | _K. Õhk. Roov. Fassaadikatte alusroov. Horisontaalne. 25 mm
674174 | 2K | _K. Õhk. Roov. Fassaadikatte alusroov. Horisontaalne. 25 mm
674175 | 2K | _K. Õhk. Roov. Fassaadikatte alusroov. Horisontaalne. 25 mm
674176 | 2K | _K. Õhk. Roov. Fassaadikatte alusroov. Horisontaalne. 25 mm
674177 | 2K | _K. Õhk. Roov. Fassaadikatte alusroov. Horisontaalne. 25 mm
674178 | 2K | _K. Õhk. Roov. Fassaadikatte alusroov. Horisontaalne. 25 mm
674179 | 2K | _K. Välisviimistlus. Alumiinium-komposiitplaat
674180 | 2K | _K. Välisviimistlus. Alumiinium-komposiitplaat
674181 | 2K | _K. Välisviimistlus. Alumiinium-komposiitplaat
674182 | 2K | _K. Välisviimistlus. Alumiinium-komposiitplaat
674183 | 2K | _K. Välisviimistlus. Alumiinium-komposiitplaat
674184 | 2K | _K. Välisviimistlus. Alumiinium-komposiitplaat
674185 | 2K | _K. Välisviimistlus. Alumiinium-komposiitplaat
674186 | 2K | _K. Välisviimistlus. Alumiinium-komposiitplaat
701230 | 2K | _K. Õhk. Roov. Fassaadikatte alusroov. Horisontaalne. 25 mm
701231 | 2K | _K. Õhk. Roov. Fassaadikatte alusroov. Horisontaalne. 25 mm
701232 | 2K | _K. Välisviimistlus. Alumiinium-komposiitplaat
701233 | 2K | _K. Välisviimistlus. Alumiinium-komposiitplaat
704000 | 2K | _K. Välisviimistlus. Alumiinium-komposiitplaat
704001 | 2K | _K. Õhk. Roov. Fassaadikatte alusroov. Horisontaalne. 25 mm
704002 | 2K | _K. Õhk. Roov. Fassaadikatte alusroov. Horisontaalne. 25 mm
704003 | 2K | _K. Õhk. Roov. Fassaadikatte alusroov. Horisontaalne. 25 mm
704004 | 2K | _K. Õhk. Roov. Fassaadikatte alusroov. Horisontaalne. 25 mm
704005 | 2K | _K. Õhk. Roov. Fassaadikatte alusroov. Horisontaalne. 25 mm
704006 | 2K | _K. Õhk. Roov. Fassaadikatte alusroov. Horisontaalne. 25 mm
704007 | 2K | _K. Õhk. Roov. Fassaadikatte alusroov. Horisontaalne. 25 mm
704008 | 2K | _K. Õhk. Roov. Fassaadikatte alusroov. Horisontaalne. 25 mm
704009 | 2K | _K. Õhk. Roov. Fassaadikatte alusroov. Horisontaalne. 25 mm
704010 | 2K | _K. Õhk. Roov. Fassaadikatte alusroov. Horisontaalne. 25 mm
704011 | 2K | _K. Välisviimistlus. Alumiinium-komposiitplaat
704012 | 2K | _K. Välisviimistlus. Alumiinium-komposiitplaat
704013 | 2K | _K. Välisviimistlus. Alumiinium-komposiitplaat
704014 | 2K | _K. Välisviimistlus. Alumiinium-komposiitplaat
704015 | 2K | _K. Välisviimistlus. Alumiinium-komposiitplaat
704016 | 2K | _K. Välisviimistlus. Alumiinium-komposiitplaat
704017 | 2K | _K. Välisviimistlus. Alumiinium-komposiitplaat
704018 | 2K | _K. Välisviimistlus. Alumiinium-komposiitplaat
704019 | 2K | _K. Välisviimistlus. Alumiinium-komposiitplaat
702260 | 2K | _K. Välisviimistlus. Alumiinium-komposiitplaat
702262 | 2K | _K. Välisviimistlus. Alumiinium-komposiitplaat
702264 | 2K | _K. Välisviimistlus. Alumiinium-komposiitplaat
702265 | 2K | _K. Välisviimistlus. Alumiinium-komposiitplaat
702266 | 2K | _K. Välisviimistlus. Alumiinium-komposiitplaat
702268 | 2K | _K. Välisviimistlus. Alumiinium-komposiitplaat
676765 | 2K | _K. Välisviimistlus. Alumiinium-komposiitplaat
676766 | 2K | _K. Õhk. Roov. Fassaadikatte alusroov. Horisontaalne. 25 mm
676767 | 2K | _K. Õhk. Roov. Fassaadikatte alusroov. Horisontaalne. 25 mm
676768 | 2K | _K. Õhk. Roov. Fassaadikatte alusroov. Horisontaalne. 25 mm
676769 | 2K | _K. Õhk. Roov. Fassaadikatte alusroov. Horisontaalne. 25 mm
676770 | 2K | _K. Õhk. Roov. Fassaadikatte alusroov. Horisontaalne. 25 mm
676771 | 2K | _K. Õhk. Roov. Fassaadikatte alusroov. Horisontaalne. 25 mm
676772 | 2K | _K. Õhk. Roov. Fassaadikatte alusroov. Horisontaalne. 25 mm
676773 | 2K | _K. Välisviimistlus. Alumiinium-komposiitplaat
676774 | 2K | _K. Välisviimistlus. Alumiinium-komposiitplaat
676775 | 2K | _K. Välisviimistlus. Alumiinium-komposiitplaat
676776 | 2K | _K. Välisviimistlus. Alumiinium-komposiitplaat
676777 | 2K | _K. Välisviimistlus. Alumiinium-komposiitplaat
676778 | 2K | _K. Välisviimistlus. Alumiinium-komposiitplaat
675941 | 2K | _K. Õhk. Roov. Fassaadikatte alusroov. Horisontaalne. 25 mm
676171 | 2K | _K. Välisviimistlus. Alumiinium-komposiitplaat
694031 | 2K | _K. Välisviimistlus. Alumiinium-komposiitplaat
694033 | 2K | _K. Välisviimistlus. Alumiinium-komposiitplaat
694034 | 2K | _K. Välisviimistlus. Alumiinium-komposiitplaat
694035 | 2K | _K. Välisviimistlus. Alumiinium-komposiitplaat
694036 | 2K | _K. Välisviimistlus. Alumiinium-komposiitplaat
695132 | 2K | _K. Välisviimistlus. Alumiinium-komposiitplaat
676512 | 2K | _K. Välisviimistlus. Alumiinium-komposiitplaat
676513 | 2K | _K. Õhk. Roov. Fassaadikatte alusroov. Horisontaalne. 25 mm
676515 | 2K | _K. Õhk. Roov. Fassaadikatte alusroov. Horisontaalne. 25 mm
676516 | 2K | _K. Õhk. Roov. Fassaadikatte alusroov. Horisontaalne. 25 mm
676519 | 2K | _K. Õhk. Roov. Fassaadikatte alusroov. Horisontaalne. 25 mm
676521 | 2K | _K. Välisviimistlus. Alumiinium-komposiitplaat
676522 | 2K | _K. Välisviimistlus. Alumiinium-komposiitplaat
676525 | 2K | _K. Välisviimistlus. Alumiinium-komposiitplaat
691583 | 2K | _K. Õhk. Roov. Fassaadikatte alusroov. Horisontaalne. 25 mm
691587 | 2K | _K. Välisviimistlus. Alumiinium-komposiitplaat
701683 | 2K | _K. Õhk. Roov. Fassaadikatte alusroov. Horisontaalne. 25 mm
701684 | 2K | _K. Õhk. Roov. Fassaadikatte alusroov. Horisontaalne. 25 mm
673930 | 2K | _K. Õhk. Roov. Fassaadikatte alusroov. Horisontaalne. 25 mm
673931 | 2K | _K. Õhk. Roov. Fassaadikatte alusroov. Horisontaalne. 25 mm
673932 | 2K | _K. Õhk. Roov. Fassaadikatte alusroov. Horisontaalne. 25 mm
673933 | 2K | _K. Õhk. Roov. Fassaadikatte alusroov. Horisontaalne. 25 mm
673934 | 2K | _K. Õhk. Roov. Fassaadikatte alusroov. Horisontaalne. 25 mm
673935 | 2K | _K. Välisviimistlus. Alumiinium-komposiitplaat
673936 | 2K | _K. Välisviimistlus. Alumiinium-komposiitplaat
673937 | 2K | _K. Välisviimistlus. Alumiinium-komposiitplaat
673938 | 2K | _K. Välisviimistlus. Alumiinium-komposiitplaat
673939 | 2K | _K. Välisviimistlus. Alumiinium-komposiitplaat
674870 | 2K | _K. Välisviimistlus. Alumiinium-komposiitplaat
674871 | 2K | _K. Õhk. Roov. Fassaadikatte alusroov. Horisontaalne. 25 mm
674872 | 2K | _K. Õhk. Roov. Fassaadikatte alusroov. Horisontaalne. 25 mm
674873 | 2K | _K. Välisviimistlus. Alumiinium-komposiitplaat
675921 | 2K | _K. Välisviimistlus. Alumiinium-komposiitplaat
675922 | 2K | _K. Õhk. Roov. Fassaadikatte alusroov. Horisontaalne. 25 mm
675923 | 2K | _K. Õhk. Roov. Fassaadikatte alusroov. Horisontaalne. 25 mm
675924 | 2K | _K. Õhk. Roov. Fassaadikatte alusroov. Horisontaalne. 25 mm
675925 | 2K | _K. Õhk. Roov. Fassaadikatte alusroov. Horisontaalne. 25 mm
675926 | 2K | _K. Õhk. Roov. Fassaadikatte alusroov. Horisontaalne. 25 mm
675927 | 2K | _K. Õhk. Roov. Fassaadikatte alusroov. Horisontaalne. 25 mm
675928 | 2K | _K. Õhk. Roov. Fassaadikatte alusroov. Horisontaalne. 25 mm
675929 | 2K | _K. Välisviimistlus. Alumiinium-komposiitplaat
675930 | 2K | _K. Välisviimistlus. Alumiinium-komposiitplaat
675931 | 2K | _K. Välisviimistlus. Alumiinium-komposiitplaat
675932 | 2K | _K. Välisviimistlus. Alumiinium-komposiitplaat
675933 | 2K | _K. Välisviimistlus. Alumiinium-komposiitplaat
675934 | 2K | _K. Välisviimistlus. Alumiinium-komposiitplaat
693098 | 2K | _K. Õhk. Roov. Fassaadikatte alusroov. Horisontaalne. 25 mm
693099 | 2K | _K. Õhk. Roov. Fassaadikatte alusroov. Horisontaalne. 25 mm
693101 | 2K | _K. Õhk. Roov. Fassaadikatte alusroov. Horisontaalne. 25 mm
693104 | 2K | _K. Õhk. Roov. Fassaadikatte alusroov. Horisontaalne. 25 mm
693106 | 2K | _K. Õhk. Roov. Fassaadikatte alusroov. Horisontaalne. 25 mm
693108 | 2K | _K. Välisviimistlus. Alumiinium-komposiitplaat
693109 | 2K | _K. Välisviimistlus. Alumiinium-komposiitplaat
693111 | 2K | _K. Välisviimistlus. Alumiinium-komposiitplaat
693114 | 2K | _K. Välisviimistlus. Alumiinium-komposiitplaat
693116 | 2K | _K. Välisviimistlus. Alumiinium-komposiitplaat
701845 | 2K | _K. Õhk. Roov. Fassaadikatte alusroov. Horisontaalne. 25 mm
701847 | 2K | _K. Õhk. Roov. Fassaadikatte alusroov. Horisontaalne. 25 mm
719988 | 5K | _K. Välisviimistlus. Alumiinium-komposiitplaat
719989 | 5K | _K. Õhk. Roov. Fassaadikatte alusroov. Horisontaalne. 25 mm
719990 | 5K | _K. Õhk. Roov. Fassaadikatte alusroov. Horisontaalne. 25 mm
719991 | 5K | _K. Õhk. Roov. Fassaadikatte alusroov. Horisontaalne. 25 mm
719993 | 5K | _K. Välisviimistlus. Alumiinium-komposiitplaat
719150 | 5K | _K. Välisviimistlus. Alumiinium-komposiitplaat
719151 | 5K | _K. Õhk. Roov. Fassaadikatte alusroov. Horisontaalne. 25 mm
719152 | 5K | _K. Õhk. Roov. Fassaadikatte alusroov. Horisontaalne. 25 mm
719153 | 5K | _K. Õhk. Roov. Fassaadikatte alusroov. Horisontaalne. 25 mm
719154 | 5K | _K. Välisviimistlus. Alumiinium-komposiitplaat
719155 | 5K | _K. Välisviimistlus. Alumiinium-komposiitplaat
720932 | 5K | _K. Välisviimistlus. Alumiinium-komposiitplaat
720933 | 5K | _K. Õhk. Roov. Fassaadikatte alusroov. Horisontaalne. 25 mm
720934 | 5K | _K. Õhk. Roov. Fassaadikatte alusroov. Horisontaalne. 25 mm
720935 | 5K | _K. Õhk. Roov. Fassaadikatte alusroov. Horisontaalne. 25 mm
720936 | 5K | _K. Välisviimistlus. Alumiinium-komposiitplaat
720937 | 5K | _K. Välisviimistlus. Alumiinium-komposiitplaat
721535 | 5K | _K. Välisviimistlus. Alumiinium-komposiitplaat
721536 | 5K | _K. Õhk. Roov. Fassaadikatte alusroov. Horisontaalne. 25 mm
721537 | 5K | _K. Õhk. Roov. Fassaadikatte alusroov. Horisontaalne. 25 mm
721538 | 5K | _K. Õhk. Roov. Fassaadikatte alusroov. Horisontaalne. 25 mm
721539 | 5K | _K. Välisviimistlus. Alumiinium-komposiitplaat
721896 | 5K | _K. Välisviimistlus. Alumiinium-komposiitplaat
721897 | 5K | _K. Õhk. Roov. Fassaadikatte alusroov. Horisontaalne. 25 mm
721898 | 5K | _K. Õhk. Roov. Fassaadikatte alusroov. Horisontaalne. 25 mm
721899 | 5K | _K. Õhk. Roov. Fassaadikatte alusroov. Horisontaalne. 25 mm
721900 | 5K | _K. Välisviimistlus. Alumiinium-komposiitplaat
721901 | 5K | _K. Välisviimistlus. Alumiinium-komposiitplaat
721113 | 5K | _K. Välisviimistlus. Alumiinium-komposiitplaat
721114 | 5K | _K. Õhk. Roov. Fassaadikatte alusroov. Horisontaalne. 25 mm
721115 | 5K | _K. Õhk. Roov. Fassaadikatte alusroov. Horisontaalne. 25 mm
721116 | 5K | _K. Õhk. Roov. Fassaadikatte alusroov. Horisontaalne. 25 mm
721117 | 5K | _K. Välisviimistlus. Alumiinium-komposiitplaat
721118 | 5K | _K. Välisviimistlus. Alumiinium-komposiitplaat
720653 | Parapet | _K. Välisviimistlus. Alumiinium-komposiitplaat
720654 | Parapet | _K. Õhk. Roov. Fassaadikatte alusroov. Horisontaalne. 25 mm
720655 | Parapet | _K. Õhk. Roov. Fassaadikatte alusroov. Horisontaalne. 25 mm
720656 | Parapet | _K. Õhk. Roov. Fassaadikatte alusroov. Horisontaalne. 25 mm
720657 | Parapet | _K. Õhk. Roov. Fassaadikatte alusroov. Horisontaalne. 25 mm
720658 | Parapet | _K. Õhk. Roov. Fassaadikatte alusroov. Horisontaalne. 25 mm
720659 | Parapet | _K. Välisviimistlus. Alumiinium-komposiitplaat
720660 | Parapet | _K. Välisviimistlus. Alumiinium-komposiitplaat
720661 | Parapet | _K. Välisviimistlus. Alumiinium-komposiitplaat
720662 | Parapet | _K. Välisviimistlus. Alumiinium-komposiitplaat
717084 | 5K | _K. Õhk. Roov. Fassaadikatte alusroov. Horisontaalne. 25 mm
717085 | 5K | _K. Õhk. Roov. Fassaadikatte alusroov. Horisontaalne. 25 mm
717087 | 5K | _K. Välisviimistlus. Alumiinium-komposiitplaat
717088 | 5K | _K. Välisviimistlus. Alumiinium-komposiitplaat
714182 | 5K | _K. Välisviimistlus. Alumiinium-komposiitplaat
714183 | 5K | _K. Õhk. Roov. Fassaadikatte alusroov. Horisontaalne. 25 mm
714184 | 5K | _K. Õhk. Roov. Fassaadikatte alusroov. Horisontaalne. 25 mm
714185 | 5K | _K. Õhk. Roov. Fassaadikatte alusroov. Horisontaalne. 25 mm
714186 | 5K | _K. Õhk. Roov. Fassaadikatte alusroov. Horisontaalne. 25 mm
714187 | 5K | _K. Välisviimistlus. Alumiinium-komposiitplaat
714188 | 5K | _K. Välisviimistlus. Alumiinium-komposiitplaat
714189 | 5K | _K. Välisviimistlus. Alumiinium-komposiitplaat
715540 | 5K | _K. Välisviimistlus. Alumiinium-komposiitplaat
715541 | 5K | _K. Õhk. Roov. Fassaadikatte alusroov. Horisontaalne. 25 mm
715542 | 5K | _K. Õhk. Roov. Fassaadikatte alusroov. Horisontaalne. 25 mm
715543 | 5K | _K. Õhk. Roov. Fassaadikatte alusroov. Horisontaalne. 25 mm
715544 | 5K | _K. Õhk. Roov. Fassaadikatte alusroov. Horisontaalne. 25 mm
715545 | 5K | _K. Välisviimistlus. Alumiinium-komposiitplaat
715546 | 5K | _K. Välisviimistlus. Alumiinium-komposiitplaat
715547 | 5K | _K. Välisviimistlus. Alumiinium-komposiitplaat
717761 | 5K | _K. Õhk. Roov. Fassaadikatte alusroov. Horisontaalne. 25 mm
717763 | 5K | _K. Õhk. Roov. Fassaadikatte alusroov. Horisontaalne. 25 mm
717764 | 5K | _K. Välisviimistlus. Alumiinium-komposiitplaat
717766 | 5K | _K. Välisviimistlus. Alumiinium-komposiitplaat
762181 | 5K | _K. Õhk. Roov. Fassaadikatte alusroov. Horisontaalne. 25 mm
675277 | 5K | _K. Välisviimistlus. Alumiinium-komposiitplaat
675278 | 5K | _K. Õhk. Roov. Fassaadikatte alusroov. Horisontaalne. 25 mm
675279 | 5K | _K. Õhk. Roov. Fassaadikatte alusroov. Horisontaalne. 25 mm
675280 | 5K | _K. Õhk. Roov. Fassaadikatte alusroov. Horisontaalne. 25 mm
675281 | 5K | _K. Õhk. Roov. Fassaadikatte alusroov. Horisontaalne. 25 mm
675282 | 5K | _K. Välisviimistlus. Alumiinium-komposiitplaat
675283 | 5K | _K. Välisviimistlus. Alumiinium-komposiitplaat
675284 | 5K | _K. Välisviimistlus. Alumiinium-komposiitplaat
715916 | 5K | _K. Välisviimistlus. Alumiinium-komposiitplaat
715917 | 5K | _K. Õhk. Roov. Fassaadikatte alusroov. Horisontaalne. 25 mm
715918 | 5K | _K. Õhk. Roov. Fassaadikatte alusroov. Horisontaalne. 25 mm
715919 | 5K | _K. Õhk. Roov. Fassaadikatte alusroov. Horisontaalne. 25 mm
715920 | 5K | _K. Õhk. Roov. Fassaadikatte alusroov. Horisontaalne. 25 mm
715921 | 5K | _K. Välisviimistlus. Alumiinium-komposiitplaat
715922 | 5K | _K. Välisviimistlus. Alumiinium-komposiitplaat
715923 | 5K | _K. Välisviimistlus. Alumiinium-komposiitplaat
716481 | Parapet | _K. Välisviimistlus. Alumiinium-komposiitplaat
716482 | Parapet | _K. Õhk. Roov. Fassaadikatte alusroov. Horisontaalne. 25 mm
716483 | Parapet | _K. Õhk. Roov. Fassaadikatte alusroov. Horisontaalne. 25 mm
716484 | Parapet | _K. Õhk. Roov. Fassaadikatte alusroov. Horisontaalne. 25 mm
716485 | Parapet | _K. Välisviimistlus. Alumiinium-komposiitplaat
716486 | Parapet | _K. Välisviimistlus. Alumiinium-komposiitplaat
716802 | 5K | _K. Välisviimistlus. Alumiinium-komposiitplaat
716803 | 5K | _K. Õhk. Roov. Fassaadikatte alusroov. Horisontaalne. 25 mm
716804 | 5K | _K. Õhk. Roov. Fassaadikatte alusroov. Horisontaalne. 25 mm
716805 | 5K | _K. Õhk. Roov. Fassaadikatte alusroov. Horisontaalne. 25 mm
716806 | 5K | _K. Välisviimistlus. Alumiinium-komposiitplaat
716807 | 5K | _K. Välisviimistlus. Alumiinium-komposiitplaat
723134 | 1K | _K. Välisviimistlus. Alumiinium-komposiitplaat
723135 | 1K | _K. Õhk. Roov. Fassaadikatte alusroov. Horisontaalne. 25 mm
723136 | 1K | _K. Õhk. Roov. Fassaadikatte alusroov. Horisontaalne. 25 mm
723137 | 1K | _K. Välisviimistlus. Alumiinium-komposiitplaat
723196 | 1K | _K. Välisviimistlus. Alumiinium-komposiitplaat
723198 | 1K | _K. Õhk. Roov. Fassaadikatte alusroov. Horisontaalne. 25 mm
723257 | 1K | _K. Välisviimistlus. Alumiinium-komposiitplaat
723258 | 1K | _K. Õhk. Roov. Fassaadikatte alusroov. Horisontaalne. 25 mm
723259 | 1K | _K. Õhk. Roov. Fassaadikatte alusroov. Horisontaalne. 25 mm
723260 | 1K | _K. Välisviimistlus. Alumiinium-komposiitplaat
723585 | 1K | _K. Välisviimistlus. Alumiinium-komposiitplaat
723586 | 1K | _K. Õhk. Roov. Fassaadikatte alusroov. Horisontaalne. 25 mm
723587 | 1K | _K. Õhk. Roov. Fassaadikatte alusroov. Horisontaalne. 25 mm
723588 | 1K | _K. Välisviimistlus. Alumiinium-komposiitplaat
534382 | 1K | _K. Õhk. Roov. Fassaadikatte alusroov. Horisontaalne. 25 mm
534385 | 1K | _K. Välisviimistlus. Alumiinium-komposiitplaat
724000 | 1K | _K. Välisviimistlus. Alumiinium-komposiitplaat
724001 | 1K | _K. Õhk. Roov. Fassaadikatte alusroov. Horisontaalne. 25 mm
724002 | 1K | _K. Õhk. Roov. Fassaadikatte alusroov. Horisontaalne. 25 mm
724003 | 1K | _K. Õhk. Roov. Fassaadikatte alusroov. Horisontaalne. 25 mm
724004 | 1K | _K. Välisviimistlus. Alumiinium-komposiitplaat
724005 | 1K | _K. Välisviimistlus. Alumiinium-komposiitplaat
724226 | 1K | _K. Välisviimistlus. Alumiinium-komposiitplaat
724227 | 1K | _K. Õhk. Roov. Fassaadikatte alusroov. Horisontaalne. 25 mm
724228 | 1K | _K. Õhk. Roov. Fassaadikatte alusroov. Horisontaalne. 25 mm
724229 | 1K | _K. Välisviimistlus. Alumiinium-komposiitplaat
723826 | 1K | _K. Välisviimistlus. Alumiinium-komposiitplaat
723827 | 1K | _K. Õhk. Roov. Fassaadikatte alusroov. Horisontaalne. 25 mm
723828 | 1K | _K. Õhk. Roov. Fassaadikatte alusroov. Horisontaalne. 25 mm
723829 | 1K | _K. Välisviimistlus. Alumiinium-komposiitplaat
725842 | 1K | _K. Välisviimistlus. Alumiinium-komposiitplaat
725843 | 1K | _K. Õhk. Roov. Fassaadikatte alusroov. Horisontaalne. 25 mm
725844 | 1K | _K. Õhk. Roov. Fassaadikatte alusroov. Horisontaalne. 25 mm
725845 | 1K | _K. Välisviimistlus. Alumiinium-komposiitplaat
739213 | 1K | _K. Välisviimistlus. Alumiinium-komposiitplaat
739214 | 1K | _K. Õhk. Roov. Fassaadikatte alusroov. Horisontaalne. 25 mm
739215 | 1K | _K. Õhk. Roov. Fassaadikatte alusroov. Horisontaalne. 25 mm
739216 | 1K | _K. Õhk. Roov. Fassaadikatte alusroov. Horisontaalne. 25 mm
739217 | 1K | _K. Õhk. Roov. Fassaadikatte alusroov. Horisontaalne. 25 mm
739218 | 1K | _K. Õhk. Roov. Fassaadikatte alusroov. Horisontaalne. 25 mm
739219 | 1K | _K. Õhk. Roov. Fassaadikatte alusroov. Horisontaalne. 25 mm
739220 | 1K | _K. Õhk. Roov. Fassaadikatte alusroov. Horisontaalne. 25 mm
739222 | 1K | _K. Välisviimistlus. Alumiinium-komposiitplaat
739223 | 1K | _K. Välisviimistlus. Alumiinium-komposiitplaat
739226 | 1K | _K. Välisviimistlus. Alumiinium-komposiitplaat

# IfcBuildingElementProxy: Door-casing_Rectangle:Door-casing_Rectangle (13)
Type - Material: <Unnamed>
Pset_BuildingElementProxyCommon - Reference: Door-casing_Rectangle; sets with these values: 2
Name (Door-casing_Rectangle:Door-casing_Rectangle:...) | In
345891 | 1-0.4
345987 | 1-0.1
492370 | 2-0.3
492394 | 2-0.3
492527 | 2-0.3
492572 | 2-0.3
493646 | 3-0.3
493650 | 3-0.3
493654 | 3-0.3
493658 | 3-0.3
509804 | 4-0.1
509913 | 5-12.1
517154 | 1-0.1

# IfcBuildingElementProxy: Door-casing_Rectangle:Door-casing_Rectangle (2)
In: 1K
Type - Material: _K. Avatäited. Raam. Alumiinium
Pset_BuildingElementProxyCommon - Reference: Door-casing_Rectangle; sets with these values: 2
Name (Door-casing_Rectangle:Door-casing_Rectangle:...)
346272
489209

# IfcBuildingElementProxy: Door-casing_Rectangle:Door-casing_Rectangle (12)
In: 1-0.5
Type - Material: _K. Metall. Plekk. Tsingitud
Pset_BuildingElementProxyCommon - Reference: Door-casing_Rectangle; sets with these values: 2
Name (Door-casing_Rectangle:Door-casing_Rectangle:...)
491813
491997
492014
492031
492048
492065
492082
492101
492208
492225
492263
492280

# IfcBuildingElementProxy: Door-casing_Rectangle:Door-casing_Rectangle (41)
Type - Material: _K. Puit. Peitsitud ja lakitud
Pset_BuildingElementProxyCommon - Reference: Door-casing_Rectangle; sets with these values: 2
Name (Door-casing_Rectangle:Door-casing_Rectangle:...) | In
514374 | 5-12.12
514480 | 5-12.13
515150 | 5-12.11
515270 | 5-12.3
515338 | 5-12.3
515455 | 5-12.7
515548 | 5-12.7
515680 | 5-12.9
516058 | 5-12.6
522175 | 4-10.3
522227 | 4-10.2
522287 | 4-9.5
522321 | 4-9.4
522386 | 4-9.3
522532 | 4-11.2
522564 | 4-11.5
522599 | 4-11.1
522640 | 4-9.1
523066 | 4-0.3
536288 | 2-1.3
536353 | 2-1.2
536381 | 2-1.2
536428 | 2-2.3
536481 | 2-2.1
536545 | 2-3.1
536626 | 2-3.3
536693 | 2-4.3
536742 | 2-4.4
536839 | 2-4.3
536930 | 2-4.3
537461 | 3-5.3
537465 | 3-5.2
537467 | 3-5.2
537469 | 3-6.3
537471 | 3-6.1
537475 | 3-7.1
537479 | 3-7.3
537481 | 3-8.3
537483 | 3-8.4
537487 | 3-8.3
537491 | 3-8.3

# IfcBuildingElementProxy: Door-handle_Lever_ABLOY_INOXI_3-19ss-002_RT:Default (136)
Type - Material: <Unnamed>
Pset_BuildingElementProxyCommon - Reference: Default; sets with these values: 2
Name (Door-handle_Lever_ABLOY_INOXI_3-19ss-002_RT:Default:...) | In
345889 | 1-0.4
345890 | 1K
345985 | 1-0.1
345986 | 1K
346270 | 1K
346271 | 1K
489338 | 1K
489339 | 1K
491811 | 1-0.5
491812 | 1K
491995 | 1-0.5
491996 | 1K
492012 | 1-0.5
492013 | 1K
492029 | 1-0.5
492030 | 1K
492046 | 1-0.5
492047 | 1K
492063 | 1-0.5
492064 | 1K
492080 | 1-0.5
492081 | 1K
492171 | 1K
492172 | 1-0.5
492209 | 1K
492210 | 1-0.5
492226 | 1K
492227 | 1-0.5
492264 | 1K
492265 | 1-0.5
492281 | 1K
492282 | 1-0.5
492368 | 2K
492369 | 2-0.3
492392 | 2K
492393 | 2-0.3
492525 | 2-0.3
492526 | 2K
492570 | 2-0.3
492571 | 2K
493644 | 3K
493645 | 3-0.3
493648 | 3K
493649 | 3-0.3
493652 | 3-0.3
493653 | 3K
493656 | 3-0.3
493657 | 3K
509802 | 4-0.1
509803 | 4-0.1
509911 | 5K
509912 | 5-12.1
514372 | 5K
514373 | 5-12.12
514636 | 5-12.13
514637 | 5K
515148 | 5-12.11
515149 | 5K
515268 | 5-12.3
515269 | 5K
515336 | 5-12.3
515337 | 5K
515598 | 5K
515599 | 5-12.7
515600 | 5K
515601 | 5-12.7
515681 | 5K
515682 | 5-12.9
516174 | 5-12.6
516175 | 5K
517152 | 1K
517153 | 1-0.1
522173 | 4K
522174 | 4-10.3
522285 | 4K
522286 | 4-9.5
522319 | 4K
522320 | 4-9.4
522530 | 4K
522531 | 4-11.2
522597 | 4K
522598 | 4-11.1
522942 | 4-10.2
522943 | 4K
522988 | 4K
522989 | 4-9.1
523006 | 4-9.3
523007 | 4K
523149 | 4-0.3
523150 | 4K
523224 | 4-11.5
523225 | 4K
536351 | 2K
536352 | 2-1.2
536543 | 2K
536544 | 2-3.1
536624 | 2K
536625 | 2-3.3
536837 | 2K
536838 | 2-4.3
536928 | 2K
536929 | 2-4.3
537084 | 2-1.3
537085 | 2K
537119 | 2-1.2
537120 | 2K
537179 | 2-2.1
537180 | 2K
537197 | 2-2.3
537198 | 2K
537259 | 2-4.4
537260 | 2K
537277 | 2-4.3
537278 | 2K
537463 | 3K
537464 | 3-5.2
537473 | 3K
537474 | 3-7.1
537477 | 3K
537478 | 3-7.3
537485 | 3K
537486 | 3-8.3
537489 | 3K
537490 | 3-8.3
537492 | 3-5.3
537493 | 3K
537494 | 3-5.2
537495 | 3K
537496 | 3-6.1
537497 | 3K
537498 | 3-6.3
537499 | 3K
537500 | 3-8.4
537501 | 3K
537502 | 3-8.3
537503 | 3K

# IfcBuildingElementProxy: HR_Elevator-door_v1:Default (4)
Type - Material: <Unnamed>
Pset_BuildingElementProxyCommon - Reference: Default; sets with these values: 2
Name (HR_Elevator-door_v1:Default:...) | In
514112 | 4-0.1
517436 | 1-0.2
518800 | 1-0.2
518804 | 2-0.2

# IfcBuildingElementProxy: HR_Flashing_Parapet_v2:Default (6)
In: Parapet
Type - Material: _K. Metall. Plekk. Värvitud. Must
Pset_BuildingElementProxyCommon - Reference: Default; sets with these values: 2
Name (HR_Flashing_Parapet_v2:Default:...)
786767
786858
786981
787136
787441
787840

# IfcBuildingElementProxy: HR_Ladder_Generic_Wall-hosted_v1:Default, HR_Ladder_Generic_Wall-hosted_v1:Default:270476
In: 4-0.1
Type - Material: <Unnamed>
Pset_BuildingElementProxyCommon - Reference: Default; sets with these values: 2

# IfcBuildingElementProxy: HR_Speciality-equipment_Hot-plate_Generic_v1:Default (12)
Type - Material: Kitchen. Hot Plate. Base, Kitchen. Hot Plate. Surface, Kitchen. Hot Plate. Frame, Kitchen. Hot Plate. Hob, Kitchen. Hot Plate. Buttons
Pset_BuildingElementProxyCommon - Reference: Default; sets with these values: 2
Name (HR_Speciality-equipment_Hot-plate_Generic_v1:Default:...) | In | Group
634454 | 2-1.2 | Model Group:Mööbel. Tyykorrus:651438
647986 | 2-4.2 | Model Group:Mööbel. Tyykorrus:651438
648889 | 2-2.2 | Model Group:Mööbel. Tyykorrus:651438
650522 | 2-3.2 | Model Group:Mööbel. Tyykorrus:651438
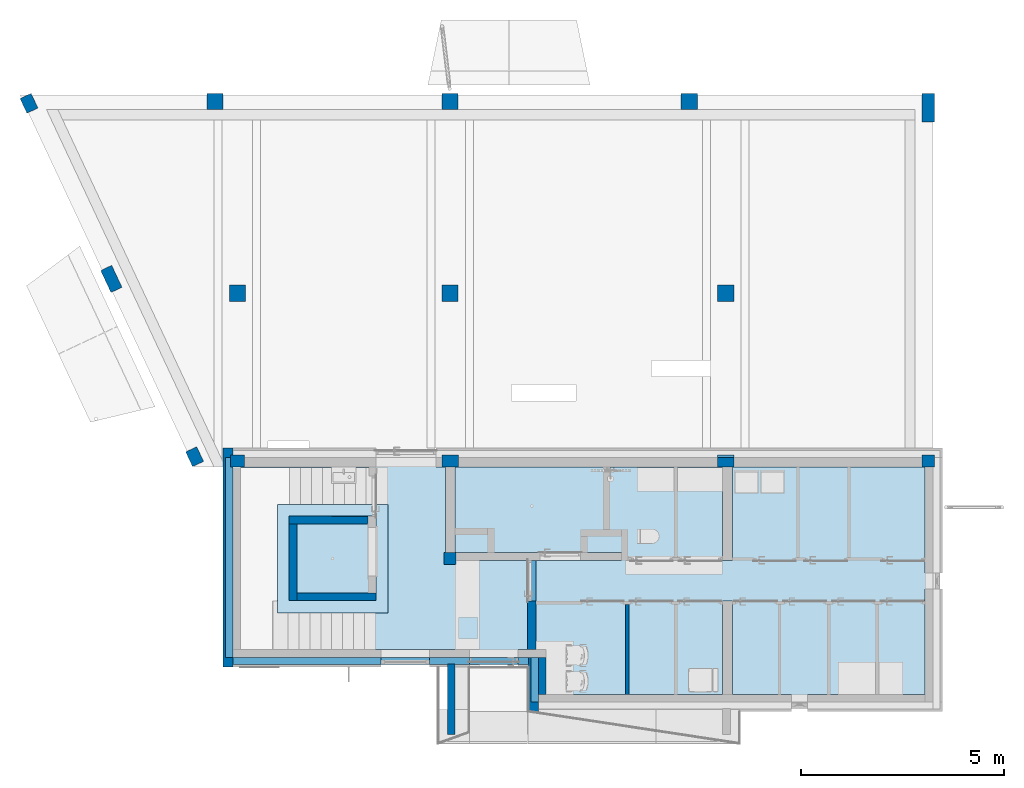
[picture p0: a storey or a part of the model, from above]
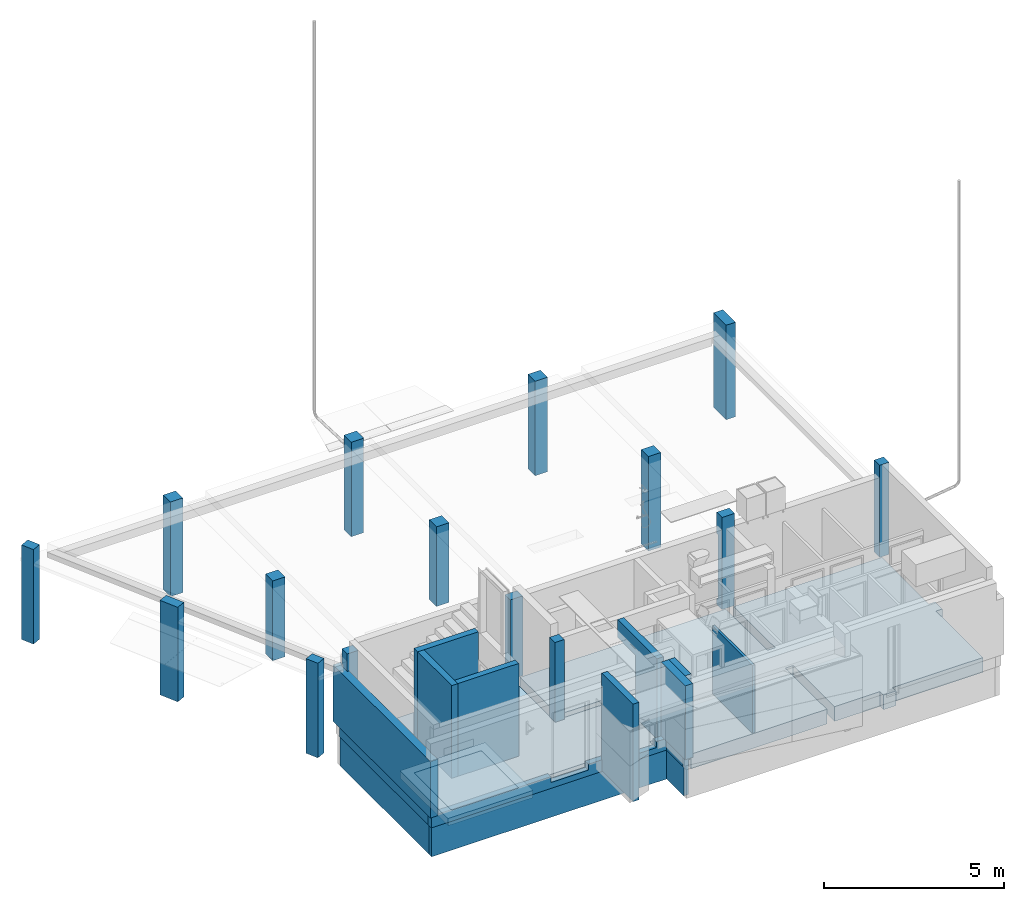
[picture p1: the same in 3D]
Properties of the parts of a building model (IFC2X3), part 2 of 3

# IfcBuildingElementProxy: HR_Speciality-equipment_Hot-plate_Generic_v1:Default (12)
Name (HR_Speciality-equipment_Hot-plate_Generic_v1:Default:...) | In | Group
652425 | 3-5.2 | Model Group:Mööbel. Tyykorrus:652539
652497 | 3-8.2 | Model Group:Mööbel. Tyykorrus:652539
652509 | 3-6.2 | Model Group:Mööbel. Tyykorrus:652539
652533 | 3-7.2 | Model Group:Mööbel. Tyykorrus:652539
653145 | 4-9.2 | Model Group:Mööbel. 4K:653259
653217 | 4-11.2 | Model Group:Mööbel. 4K:653259
653253 | 4-10.2 | Model Group:Mööbel. 4K:653259
661677 | 5-12.4

# IfcBuildingElementProxy: JSO_Solar-panel (1):JSO_Solar-panel (1) (36)
In: 5K
Type - Material: Solar Panel. Panel, Solar Panel. Frame, Solar Panel. Bracket
Pset_BuildingElementProxyCommon - Reference: JSO_Solar-panel (1); sets with these values: 2
Name (JSO_Solar-panel (1):JSO_Solar-panel (1):...)
801606
801608
801610
801612
801614
801616
801617
801618
801619
801620
801621
801622
801623
801627
801628
801629
801630
801631
801632
801636
801637
801638
801639
801640
801641
801642
801643
801644
801645
801646
801648
801649
801650
801651
801653
801655

# IfcBuildingElementProxy: Lipualus_seinale:Lipualus_seinale, Lipualus_seinale:Lipualus_seinale:792574
In: 1K
Type - Material: <Unnamed>
Pset_BuildingElementProxyCommon - Reference: Lipualus_seinale; sets with these values: 2

# IfcBuildingElementProxy: Tänavasilt.Aadress_ja_majanumber:Standard. H320 mm x L(700+400) mm, Tänavasilt.Aadress_ja_majanumber:Standard. H320 mm x L(700+400) mm:794555
In: 1K
Type - Material: _HR. Metal. Paint. Tänavasilt. Sinine, _HR. Metal. Paint. Tänavasilt. Valge
Pset_BuildingElementProxyCommon - Reference: Standard. H320 mm x L(700+400) mm; sets with these values: 2

# IfcColumn: HR_Column_Rectangular_Hollow:160x160x5 (3)
Type - PredefinedType: COLUMN; Material: _K. Metall. Teras. Värvitud
Pset_ColumnCommon - IsExternal: no; Reference: 160x160x5
Pset_QuantityTakeOff - Reference: 160x160x5; sets with these values: 2
Name (HR_Column_Rectangular_Hollow:160x160x5:...) | In
213196 | 4K
213197 | 4K
213219 | 5K

# IfcColumn: HR_Column_Rectangular_Hollow:200x200x5 (2)
Type - PredefinedType: COLUMN; Material: _K. Metall. Teras. Värvitud
Pset_ColumnCommon - IsExternal: no; Reference: 200x200x5
Pset_QuantityTakeOff - Reference: 200x200x5; sets with these values: 2
Name (HR_Column_Rectangular_Hollow:200x200x5:...) | In
212256 | 2K
213126 | 3K

# IfcColumn: HR_Column_Rectangular_Hollow:200x200x8 (4)
Type - PredefinedType: COLUMN; Material: _K. Metall. Teras. Värvitud
Pset_ColumnCommon - IsExternal: no; Reference: 200x200x8
Pset_QuantityTakeOff - Reference: 200x200x8; sets with these values: 2
Name (HR_Column_Rectangular_Hollow:200x200x8:...) | In
212568 | 2K
212580 | 2K
213127 | 3K
213128 | 3K

# IfcColumn: HR_Column_Rectangular_Solid:300x300 (2)
In: 1K
Type - PredefinedType: COLUMN; Material: _K. Betoon. Armeeritud. Monteeritav
Pset_ColumnCommon - IsExternal: no; Reference: 300x300
Pset_QuantityTakeOff - Reference: 300x300; sets with these values: 2
Name (HR_Column_Rectangular_Solid:300x300:...)
205801
207272

# IfcColumn: HR_Column_Rectangular_Solid:350x300, HR_Column_Rectangular_Solid:350x300:205682
In: 1K
Type - PredefinedType: COLUMN; Material: _K. Betoon. Armeeritud. Monteeritav
Pset_ColumnCommon - IsExternal: no; Reference: 350x300
Pset_QuantityTakeOff - Reference: 350x300; sets with these values: 2

# IfcColumn: HR_Column_Rectangular_Solid:400x300 (4)
In: 1K
Type - PredefinedType: COLUMN; Material: _K. Betoon. Armeeritud. Monteeritav
Pset_ColumnCommon - Reference: 400x300; IsExternal: no
Pset_QuantityTakeOff - Reference: 400x300; sets with these values: 2
Name (HR_Column_Rectangular_Solid:400x300:...)
205350
205633
206933
207209

# IfcColumn: HR_Column_Rectangular_Solid:400x400 (6)
In: 1K
Type - PredefinedType: COLUMN; Material: _K. Betoon. Armeeritud. Monteeritav
Pset_ColumnCommon - IsExternal: no; Reference: 400x400
Pset_QuantityTakeOff - Reference: 400x400; sets with these values: 2
Name (HR_Column_Rectangular_Solid:400x400:...)
206716
206845
206859
206873
206885
206895

# IfcColumn: HR_Column_Rectangular_Solid:600x300, HR_Column_Rectangular_Solid:600x300:207099
In: 1K
Type - PredefinedType: COLUMN; Material: _K. Betoon. Armeeritud. Monteeritav
Pset_ColumnCommon - IsExternal: no; Reference: 600x300
Pset_QuantityTakeOff - Reference: 600x300; sets with these values: 2

# IfcColumn: HR_Column_Rectangular_Solid:700x300, HR_Column_Rectangular_Solid:700x300:208280
In: 1K
Type - PredefinedType: COLUMN; Material: _K. Betoon. Armeeritud. Monteeritav
Pset_ColumnCommon - IsExternal: no; Reference: 700x300
Pset_QuantityTakeOff - Reference: 700x300; sets with these values: 2

# IfcCovering: Compound Ceiling:Default. 50 mm, Compound Ceiling:Default. 50 mm:488815
In: 1K
Type - PredefinedType: CEILING
Type - Pset_CoveringCommon - TotalThickness: 20 mm
Material: _K. Õhk. Roov. Fassaadikatte alusroov. Horisontaalne. 25 mm 16 mm, _K. Välisviimistlus. Alumiinium-komposiitplaat 4 mm
Pset_CoveringCommon - Reference: Default. 50 mm; Finish: _K. Välisviimistlus. Alumiinium-komposiitplaat;
Pset_QuantityTakeOff - Reference: Default. 50 mm

# IfcCovering: Compound Ceiling:Parkla soojem lagi (3)
In: 1K
Type - PredefinedType: CEILING
Type - Pset_CoveringCommon - TotalThickness: 304 mm
Material: _K. Soojustus. Mineraalvill 300 mm, _K. Välisviimistlus. Alumiinium-komposiitplaat. Must 4 mm
Pset_CoveringCommon - Reference: Parkla soojem lagi; Finish: _K. Välisviimistlus. Alumiinium-komposiitplaat. Must;
Pset_QuantityTakeOff - Reference: Parkla soojem lagi
Name (Compound Ceiling:Parkla soojem lagi:...)
525626
527126
672377

# IfcCovering: Compound Ceiling:Parkla tala alune perimeetris, Compound Ceiling:Parkla tala alune perimeetris:526526
In: 1K
Type - PredefinedType: CEILING
Type - Pset_CoveringCommon - TotalThickness: 104 mm
Material: _K. Soojustus. Mineraalvill 100 mm, _K. Välisviimistlus. Alumiinium-komposiitplaat 4 mm
Pset_CoveringCommon - Reference: Parkla tala alune perimeetris; Finish: _K. Välisviimistlus. Alumiinium-komposiitplaat;
Pset_QuantityTakeOff - Reference: Parkla tala alune perimeetris

# IfcCovering: Compound Ceiling:Valge rõdud (47)
Type - PredefinedType: CEILING
Type - Pset_CoveringCommon - TotalThickness: 20 mm
Material: _K. Õhk. Roov. Fassaadikatte alusroov. Horisontaalne. 25 mm 16 mm, _K. Välisviimistlus. Alumiinium-komposiitplaat 4 mm
Pset_CoveringCommon - Reference: Valge rõdud; Finish: _K. Välisviimistlus. Alumiinium-komposiitplaat;
Pset_QuantityTakeOff - Reference: Valge rõdud
Name (Compound Ceiling:Valge rõdud:...) | In
677792 | 1K
699351 | 1K
699431 | 2K
699438 | 2K
728988 | 2K
731225 | 2K
731490 | 1K
731694 | 1K
731724 | 1K
731851 | 1K
732288 | 2K
732830 | 3K
732842 | 3K
732853 | 2K
732860 | 2K
732867 | 2K
732874 | 2K
733314 | 3K
733318 | 3K
733327 | 3K
733339 | 4K
733348 | 4K
733359 | 3K
733366 | 3K
733373 | 3K
733380 | 3K
733444 | 4K
733451 | 4K
733458 | 4K
733465 | 4K
733567 | 5K
733574 | 5K
733581 | 5K
733588 | 5K
733616 | 4K
733774 | 4K
733807 | 4K
734142 | 5K
734149 | 5K
734156 | 5K
734478 | 2K
734487 | 2K
734510 | 5K
735012 | 5K
735556 | 5K
735563 | 5K
735574 | 5K

# IfcDistributionPort (68)
Description: Flow
Name | FlowDirection
OutPort_275203_1 | SOURCE
OutPort_275469_1 | SOURCE
InPort_505974_3 | SINK
InPort_505974_4 | SINK
InPort_645102_3 | SINK
InPort_645102_4 | SINK
InPort_645804_3 | SINK
InPort_645804_4 | SINK
InPort_646623_3 | SINK
InPort_646623_4 | SINK
InPort_651368_3 | SINK
InPort_651368_4 | SINK
InPort_652472_3 | SINK
InPort_652472_4 | SINK
InPort_652477_3 | SINK
InPort_652477_4 | SINK
InPort_652481_3 | SINK
InPort_652481_4 | SINK
InPort_652537_3 | SINK
InPort_652537_4 | SINK
InPort_653192_3 | SINK
InPort_653192_4 | SINK
InPort_653197_3 | SINK
InPort_653197_4 | SINK
InPort_653201_3 | SINK
InPort_653201_4 | SINK
InPort_653257_3 | SINK
InPort_653257_4 | SINK
InPort_658073_3 | SINK
InPort_658073_4 | SINK
InPort_663499_3 | SINK
InPort_663499_4 | SINK
InPort_663736_3 | SINK
InPort_663736_4 | SINK
InPort_663894_3 | SINK
InPort_663894_4 | SINK
InPort_664015_3 | SINK
InPort_664015_4 | SINK
Port_777160_0 | SOURCEANDSINK | Group: Hydronic Supply 1
Port_777160_1 | SOURCEANDSINK | Group: Hydronic Supply 1
Port_777181_1 | SOURCEANDSINK | Group: Hydronic Supply 1
Port_777169_0 | SOURCEANDSINK | Group: Hydronic Supply 1
Port_777181_2 | SOURCEANDSINK | Group: Hydronic Supply 1
Port_777169_1 | SOURCEANDSINK | Group: Hydronic Supply 1
Port_777192_1 | SOURCEANDSINK | Group: Hydronic Supply 1
Port_777186_0 | SOURCEANDSINK | Group: Hydronic Supply 1
Port_777192_2 | SOURCEANDSINK | Group: Hydronic Supply 1
Port_777186_1 | SOURCEANDSINK | Group: Hydronic Supply 1
Port_784283_0 | SOURCEANDSINK | Group: Hydronic Supply 2
Port_784283_1 | SOURCEANDSINK | Group: Hydronic Supply 2
Port_784301_1 | SOURCEANDSINK | Group: Hydronic Supply 2
Port_784292_0 | SOURCEANDSINK | Group: Hydronic Supply 2
Port_784301_2 | SOURCEANDSINK | Group: Hydronic Supply 2
Port_784292_1 | SOURCEANDSINK | Group: Hydronic Supply 2
Port_784312_1 | SOURCEANDSINK | Group: Hydronic Supply 2
Port_784306_0 | SOURCEANDSINK | Group: Hydronic Supply 2
Port_784312_2 | SOURCEANDSINK | Group: Hydronic Supply 2
Port_784306_1 | SOURCEANDSINK | Group: Hydronic Supply 2
Port_784369_0 | SOURCEANDSINK | Group: Hydronic Supply 3
Port_784369_1 | SOURCEANDSINK | Group: Hydronic Supply 3
Port_784387_1 | SOURCEANDSINK | Group: Hydronic Supply 3
Port_784378_0 | SOURCEANDSINK | Group: Hydronic Supply 3
Port_784387_2 | SOURCEANDSINK | Group: Hydronic Supply 3
Port_784378_1 | SOURCEANDSINK | Group: Hydronic Supply 3
Port_784401_1 | SOURCEANDSINK | Group: Hydronic Supply 3
Port_784392_0 | SOURCEANDSINK | Group: Hydronic Supply 3
Port_784401_2 | SOURCEANDSINK | Group: Hydronic Supply 3
Port_784392_1 | SOURCEANDSINK | Group: Hydronic Supply 3

# IfcDoor: HR_Generic_Hinged_Double:Default. Klaasprofiiluks lävepakuga. 1500 x 2100 mm, HR_Generic_Hinged_Double:Default. Klaasprofiiluks lävepakuga. 1500 x 2100 mm:489204
In: 1K
Type - ParameterTakesPrecedence: no; Sizeable: no; Material: _K. Avatäited. Raam. Alumiinium, _K. Klaas. Pakett
Type - HR_Generic_Hinged_Double:Default. Klaasprofiiluks lävepakuga. 1500 x 2100 mm:489204 - ThresholdDepth: 92 mm; ThresholdThickness: 20 mm
OverallHeight: 2150 mm; OverallWidth: 1530 mm
Pset_DoorCommon - IsExternal: no; Reference: Default. Klaasprofiiluks lävepakuga. 1500 x 2100 mm
Pset_QuantityTakeOff - Reference: Default. Klaasprofiiluks lävepakuga. 1500 x 2100 mm

# IfcDoor: HR_Generic_Hinged_Single:Default. Klaasprofiiluks lävepakuga. 1200 x 2100 mm. Left, HR_Generic_Hinged_Single:Default. Klaasprofiiluks lävepakuga. 1200 x 2100 mm. Left:346267
In: 1K
Type - ParameterTakesPrecedence: no; Sizeable: no; Material: _K. Klaas. Kirgas, _K. Avatäited. Raam. Alumiinium
Type - HR_Generic_Hinged_Single:Default. Klaasprofiiluks lävepakuga. 1200 x 2100 mm. Left:346267 - ThresholdDepth: 92 mm; ThresholdThickness: 25 mm
OverallHeight: 2130 mm; OverallWidth: 1260 mm
Pset_DoorCommon - IsExternal: no; Reference: Default. Klaasprofiiluks lävepakuga. 1200 x 2100 mm. Left
Pset_QuantityTakeOff - Reference: Default. Klaasprofiiluks lävepakuga. 1200 x 2100 mm. Left

# IfcDoor: HR_Generic_Hinged_Single:Default. Manteluks lävepakuga. 1000 x 2100 mm. Left (3)
Type - ParameterTakesPrecedence: no; Sizeable: no; Material: <Unnamed>, Default
Type - HR_Generic_Hinged_Single:Default. Manteluks lävepakuga. 1000 x 2100 mm. Left:345886 - ThresholdDepth: 92 mm; ThresholdThickness: 20 mm
OverallHeight: 2130 mm; OverallWidth: 1060 mm
Pset_DoorCommon - IsExternal: no; Reference: Default. Manteluks lävepakuga. 1000 x 2100 mm. Left
Pset_QuantityTakeOff - Reference: Default. Manteluks lävepakuga. 1000 x 2100 mm. Left
Name (HR_Generic_Hinged_Single:Default. Manteluks lävepakuga. 1000 x 2100 mm. Left:...) | In
345886 | 1K
492522 | 2K
493651 | 3K

# IfcDoor: HR_Generic_Hinged_Single:Default. Manteluks lävepakuga. 1000 x 2100 mm. Left, HR_Generic_Hinged_Single:Default. Manteluks lävepakuga. 1000 x 2100 mm. Left:345984
In: 1K
Type - ParameterTakesPrecedence: no; Sizeable: no; Material: <Unnamed>, Default
Type - HR_Generic_Hinged_Single:Default. Manteluks lävepakuga. 1000 x 2100 mm. Left:345984 - ThresholdDepth: 92 mm; ThresholdThickness: 20 mm
OverallHeight: 2130 mm; OverallWidth: 1060 mm
Pset_DoorCommon - IsExternal: no; Reference: Default. Manteluks lävepakuga. 1000 x 2100 mm. Left
Pset_QuantityTakeOff - Reference: Default. Manteluks lävepakuga. 1000 x 2100 mm. Left

# IfcDoor: HR_Generic_Hinged_Single:Default. Manteluks lävepakuga. 1000 x 2100 mm. Left, HR_Generic_Hinged_Single:Default. Manteluks lävepakuga. 1000 x 2100 mm. Left:492567
In: 2K
Type - ParameterTakesPrecedence: no; Sizeable: no; Material: <Unnamed>, Default
Type - HR_Generic_Hinged_Single:Default. Manteluks lävepakuga. 1000 x 2100 mm. Left:492567 - ThresholdDepth: 92 mm; ThresholdThickness: 20 mm
OverallHeight: 2130 mm; OverallWidth: 1060 mm
Pset_DoorCommon - IsExternal: yes; Reference: Default. Manteluks lävepakuga. 1000 x 2100 mm. Left
Pset_QuantityTakeOff - Reference: Default. Manteluks lävepakuga. 1000 x 2100 mm. Left

# IfcDoor: HR_Generic_Hinged_Single:Default. Manteluks lävepakuga. 1000 x 2100 mm. Left, HR_Generic_Hinged_Single:Default. Manteluks lävepakuga. 1000 x 2100 mm. Left:493655
In: 3K
Type - ParameterTakesPrecedence: no; Sizeable: no; Material: <Unnamed>, Default
Type - HR_Generic_Hinged_Single:Default. Manteluks lävepakuga. 1000 x 2100 mm. Left:493655 - ThresholdDepth: 92 mm; ThresholdThickness: 20 mm
OverallHeight: 2130 mm; OverallWidth: 1060 mm
Pset_DoorCommon - IsExternal: yes; Reference: Default. Manteluks lävepakuga. 1000 x 2100 mm. Left
Pset_QuantityTakeOff - Reference: Default. Manteluks lävepakuga. 1000 x 2100 mm. Left

# IfcDoor: HR_Generic_Hinged_Single:Default. Manteluks lävepakuga. 1000 x 2100 mm. Left, HR_Generic_Hinged_Single:Default. Manteluks lävepakuga. 1000 x 2100 mm. Left:509799
In: 5K
Type - ParameterTakesPrecedence: no; Sizeable: no; Material: <Unnamed>, Default
Type - HR_Generic_Hinged_Single:Default. Manteluks lävepakuga. 1000 x 2100 mm. Left:509799 - ThresholdDepth: 92 mm; ThresholdThickness: 20 mm
OverallHeight: 2130 mm; OverallWidth: 1060 mm
Pset_DoorCommon - IsExternal: no; Reference: Default. Manteluks lävepakuga. 1000 x 2100 mm. Left
Pset_QuantityTakeOff - Reference: Default. Manteluks lävepakuga. 1000 x 2100 mm. Left

# IfcDoor: HR_Generic_Hinged_Single:Default. Manteluks lävepakuga. 1000 x 2100 mm. Right (4)
Type - ParameterTakesPrecedence: no; Sizeable: no; Material: <Unnamed>
Type - HR_Generic_Hinged_Single:Default. Manteluks lävepakuga. 1000 x 2100 mm. Right:492365 - ThresholdDepth: 92 mm; ThresholdThickness: 20 mm
OverallHeight: 2130 mm; OverallWidth: 1060 mm
Pset_DoorCommon - IsExternal: no; Reference: Default. Manteluks lävepakuga. 1000 x 2100 mm. Right
Pset_QuantityTakeOff - Reference: Default. Manteluks lävepakuga. 1000 x 2100 mm. Right
Name (HR_Generic_Hinged_Single:Default. Manteluks lävepakuga. 1000 x 2100 mm. Right:...) | In
492365 | 2K
492389 | 2K
493643 | 3K
493647 | 3K

# IfcDoor: HR_Generic_Hinged_Single:Default. Manteluks lävepakuga. 1000 x 2100 mm. Right, HR_Generic_Hinged_Single:Default. Manteluks lävepakuga. 1000 x 2100 mm. Right:509908
In: 5K
Type - ParameterTakesPrecedence: no; Sizeable: no; Material: <Unnamed>
Type - HR_Generic_Hinged_Single:Default. Manteluks lävepakuga. 1000 x 2100 mm. Right:509908 - ThresholdDepth: 92 mm; ThresholdThickness: 20 mm
OverallHeight: 2130 mm; OverallWidth: 1060 mm
Pset_DoorCommon - IsExternal: yes; Reference: Default. Manteluks lävepakuga. 1000 x 2100 mm. Right
Pset_QuantityTakeOff - Reference: Default. Manteluks lävepakuga. 1000 x 2100 mm. Right

# IfcDoor: HR_Generic_Hinged_Single:Default. Manteluks lävepakuga. 1000 x 2100 mm. Right, HR_Generic_Hinged_Single:Default. Manteluks lävepakuga. 1000 x 2100 mm. Right:517149
In: 1K
Type - ParameterTakesPrecedence: no; Sizeable: no; Material: <Unnamed>
Type - HR_Generic_Hinged_Single:Default. Manteluks lävepakuga. 1000 x 2100 mm. Right:517149 - ThresholdDepth: 92 mm; ThresholdThickness: 20 mm
OverallHeight: 2130 mm; OverallWidth: 1060 mm
Pset_DoorCommon - IsExternal: no; Reference: Default. Manteluks lävepakuga. 1000 x 2100 mm. Right
Pset_QuantityTakeOff - Reference: Default. Manteluks lävepakuga. 1000 x 2100 mm. Right

# IfcDoor: HR_Generic_Hinged_Single:Default. Manteluks lävepakuga. 1000 x 2100 mm. Right, HR_Generic_Hinged_Single:Default. Manteluks lävepakuga. 1000 x 2100 mm. Right:522594
In: 4K
Type - ParameterTakesPrecedence: no; Sizeable: no; Material: _K. Puit. Peitsitud ja lakitud
Type - HR_Generic_Hinged_Single:Default. Manteluks lävepakuga. 1000 x 2100 mm. Right:522594 - ThresholdDepth: 92 mm; ThresholdThickness: 20 mm
OverallHeight: 2130 mm; OverallWidth: 1060 mm
Pset_DoorCommon - IsExternal: yes; Reference: Default. Manteluks lävepakuga. 1000 x 2100 mm. Right
Pset_QuantityTakeOff - Reference: Default. Manteluks lävepakuga. 1000 x 2100 mm. Right

# IfcDoor: HR_Generic_Hinged_Single:Default. Manteluks lävepakuga. 1000 x 2100 mm. Right, HR_Generic_Hinged_Single:Default. Manteluks lävepakuga. 1000 x 2100 mm. Right:522635
In: 4K
Type - ParameterTakesPrecedence: no; Sizeable: no; Material: _K. Puit. Peitsitud ja lakitud
Type - HR_Generic_Hinged_Single:Default. Manteluks lävepakuga. 1000 x 2100 mm. Right:522635 - ThresholdDepth: 92 mm; ThresholdThickness: 20 mm
OverallHeight: 2130 mm; OverallWidth: 1060 mm
Pset_DoorCommon - IsExternal: no; Reference: Default. Manteluks lävepakuga. 1000 x 2100 mm. Right
Pset_QuantityTakeOff - Reference: Default. Manteluks lävepakuga. 1000 x 2100 mm. Right

# IfcDoor: HR_Generic_Hinged_Single:Default. Manteluks lävepakuga. 700 x 2100 mm. Left, HR_Generic_Hinged_Single:Default. Manteluks lävepakuga. 700 x 2100 mm. Left:516053
In: 5K
Type - ParameterTakesPrecedence: no; Sizeable: no; Material: _K. Puit. Peitsitud ja lakitud
Type - HR_Generic_Hinged_Single:Default. Manteluks lävepakuga. 700 x 2100 mm. Left:516053 - ThresholdDepth: 92 mm; ThresholdThickness: 20 mm
OverallHeight: 2130 mm; OverallWidth: 760 mm
Pset_DoorCommon - IsExternal: no; Reference: Default. Manteluks lävepakuga. 700 x 2100 mm. Left
Pset_QuantityTakeOff - Reference: Default. Manteluks lävepakuga. 700 x 2100 mm. Left

# IfcDoor: HR_Generic_Hinged_Single:Default. Manteluks lävepakuga. 800 x 2100 mm. Left (11)
Type - ParameterTakesPrecedence: no; Sizeable: no; Material: _K. Puit. Peitsitud ja lakitud
Type - HR_Generic_Hinged_Single:Default. Manteluks lävepakuga. 800 x 2100 mm. Left:514475 - ThresholdDepth: 92 mm; ThresholdThickness: 20 mm
OverallHeight: 2130 mm; OverallWidth: 860 mm
Pset_DoorCommon - IsExternal: no; Reference: Default. Manteluks lävepakuga. 800 x 2100 mm. Left
Pset_QuantityTakeOff - Reference: Default. Manteluks lävepakuga. 800 x 2100 mm. Left
Name (HR_Generic_Hinged_Single:Default. Manteluks lävepakuga. 800 x 2100 mm. Left:...) | In
514475 | 5K
515146 | 5K
515265 | 5K
515333 | 5K
522381 | 4K
536377 | 2K
536423 | 2K
536688 | 2K
537466 | 3K
537468 | 3K
537480 | 3K

# IfcDoor: HR_Generic_Hinged_Single:Default. Manteluks lävepakuga. 800 x 2100 mm. Left, HR_Generic_Hinged_Single:Default. Manteluks lävepakuga. 800 x 2100 mm. Left:522222
In: 4K
Type - ParameterTakesPrecedence: no; Sizeable: no; Material: _K. Puit. Peitsitud ja lakitud
Type - HR_Generic_Hinged_Single:Default. Manteluks lävepakuga. 800 x 2100 mm. Left:522222 - ThresholdDepth: 92 mm; ThresholdThickness: 20 mm
OverallHeight: 2130 mm; OverallWidth: 860 mm
Pset_DoorCommon - IsExternal: no; Reference: Default. Manteluks lävepakuga. 800 x 2100 mm. Left
Pset_QuantityTakeOff - Reference: Default. Manteluks lävepakuga. 800 x 2100 mm. Left

# IfcDoor: HR_Generic_Hinged_Single:Default. Manteluks lävepakuga. 800 x 2100 mm. Left (5)
Type - ParameterTakesPrecedence: no; Sizeable: no; Material: _K. Puit. Peitsitud ja lakitud
Type - HR_Generic_Hinged_Single:Default. Manteluks lävepakuga. 800 x 2100 mm. Left:522559 - ThresholdDepth: 92 mm; ThresholdThickness: 20 mm
OverallHeight: 2130 mm; OverallWidth: 860 mm
Pset_DoorCommon - IsExternal: no; Reference: Default. Manteluks lävepakuga. 800 x 2100 mm. Left
Pset_QuantityTakeOff - Reference: Default. Manteluks lävepakuga. 800 x 2100 mm. Left
Name (HR_Generic_Hinged_Single:Default. Manteluks lävepakuga. 800 x 2100 mm. Left:...) | In
522559 | 4K
536284 | 2K
536737 | 2K
537460 | 3K
537482 | 3K

# IfcDoor: HR_Generic_Hinged_Single:Default. Manteluks lävepakuga. 800 x 2100 mm. Left (2)
Type - ParameterTakesPrecedence: no; Sizeable: no; Material: _K. Puit. Peitsitud ja lakitud
Type - HR_Generic_Hinged_Single:Default. Manteluks lävepakuga. 800 x 2100 mm. Left:536476 - ThresholdDepth: 92 mm; ThresholdThickness: 20 mm
OverallHeight: 2130 mm; OverallWidth: 860 mm
Pset_DoorCommon - IsExternal: no; Reference: Default. Manteluks lävepakuga. 800 x 2100 mm. Left
Pset_QuantityTakeOff - Reference: Default. Manteluks lävepakuga. 800 x 2100 mm. Left
Name (HR_Generic_Hinged_Single:Default. Manteluks lävepakuga. 800 x 2100 mm. Left:...) | In
536476 | 2K
537470 | 3K

# IfcDoor: HR_Generic_Hinged_Single:Default. Manteluks lävepakuga. 800 x 2100 mm. Right (7)
Type - ParameterTakesPrecedence: no; Sizeable: no; Material: _K. Puit. Peitsitud ja lakitud
Type - HR_Generic_Hinged_Single:Default. Manteluks lävepakuga. 800 x 2100 mm. Right:514369 - ThresholdDepth: 92 mm; ThresholdThickness: 20 mm
OverallHeight: 2130 mm; OverallWidth: 860 mm
Pset_DoorCommon - IsExternal: no; Reference: Default. Manteluks lävepakuga. 800 x 2100 mm. Right
Pset_QuantityTakeOff - Reference: Default. Manteluks lävepakuga. 800 x 2100 mm. Right
Name (HR_Generic_Hinged_Single:Default. Manteluks lävepakuga. 800 x 2100 mm. Right:...) | In
514369 | 5K
515450 | 5K
515543 | 5K
515679 | 5K
522170 | 4K
536621 | 2K
537476 | 3K

# IfcDoor: HR_Generic_Hinged_Single:Default. Manteluks lävepakuga. 800 x 2100 mm. Right (6)
Type - ParameterTakesPrecedence: no; Sizeable: no; Material: _K. Puit. Peitsitud ja lakitud
Type - HR_Generic_Hinged_Single:Default. Manteluks lävepakuga. 800 x 2100 mm. Right:522282 - ThresholdDepth: 92 mm; ThresholdThickness: 20 mm
OverallHeight: 2130 mm; OverallWidth: 860 mm
Pset_DoorCommon - IsExternal: no; Reference: Default. Manteluks lävepakuga. 800 x 2100 mm. Right
Pset_QuantityTakeOff - Reference: Default. Manteluks lävepakuga. 800 x 2100 mm. Right
Name (HR_Generic_Hinged_Single:Default. Manteluks lävepakuga. 800 x 2100 mm. Right:...) | In
522282 | 4K
522316 | 4K
536348 | 2K
536834 | 2K
537462 | 3K
537484 | 3K

# IfcDoor: HR_Generic_Hinged_Single:Default. Manteluks lävepakuga. 800 x 2100 mm. Right, HR_Generic_Hinged_Single:Default. Manteluks lävepakuga. 800 x 2100 mm. Right:522527
In: 4K
Type - ParameterTakesPrecedence: no; Sizeable: no; Material: _K. Puit. Peitsitud ja lakitud
Type - HR_Generic_Hinged_Single:Default. Manteluks lävepakuga. 800 x 2100 mm. Right:522527 - ThresholdDepth: 92 mm; ThresholdThickness: 20 mm
OverallHeight: 2130 mm; OverallWidth: 860 mm
Pset_DoorCommon - IsExternal: yes; Reference: Default. Manteluks lävepakuga. 800 x 2100 mm. Right
Pset_QuantityTakeOff - Reference: Default. Manteluks lävepakuga. 800 x 2100 mm. Right

# IfcDoor: HR_Generic_Hinged_Single:Default. Manteluks lävepakuga. 800 x 2100 mm. Right (2)
Type - ParameterTakesPrecedence: no; Sizeable: no; Material: _K. Puit. Peitsitud ja lakitud
Type - HR_Generic_Hinged_Single:Default. Manteluks lävepakuga. 800 x 2100 mm. Right:536540 - ThresholdDepth: 92 mm; ThresholdThickness: 20 mm
OverallHeight: 2130 mm; OverallWidth: 860 mm
Pset_DoorCommon - IsExternal: no; Reference: Default. Manteluks lävepakuga. 800 x 2100 mm. Right
Pset_QuantityTakeOff - Reference: Default. Manteluks lävepakuga. 800 x 2100 mm. Right
Name (HR_Generic_Hinged_Single:Default. Manteluks lävepakuga. 800 x 2100 mm. Right:...) | In
536540 | 2K
537472 | 3K

# IfcDoor: HR_Generic_Hinged_Single:Default. Manteluks lävepakuga. 800 x 2100 mm. Right (2)
Type - ParameterTakesPrecedence: no; Sizeable: no; Material: _K. Puit. Peitsitud ja lakitud
Type - HR_Generic_Hinged_Single:Default. Manteluks lävepakuga. 800 x 2100 mm. Right:536925 - ThresholdDepth: 92 mm; ThresholdThickness: 20 mm
OverallHeight: 2130 mm; OverallWidth: 860 mm
Pset_DoorCommon - IsExternal: yes; Reference: Default. Manteluks lävepakuga. 800 x 2100 mm. Right
Pset_QuantityTakeOff - Reference: Default. Manteluks lävepakuga. 800 x 2100 mm. Right
Name (HR_Generic_Hinged_Single:Default. Manteluks lävepakuga. 800 x 2100 mm. Right:...) | In
536925 | 2K
537488 | 3K

# IfcDoor: HR_Generic_Hinged_Single:Default. Manteluks lävepakuta. 1000 x 2100 mm. Left, HR_Generic_Hinged_Single:Default. Manteluks lävepakuta. 1000 x 2100 mm. Left:523065
In: 4K
Type - ParameterTakesPrecedence: no; Sizeable: no; Material: _K. Puit. Peitsitud ja lakitud
Type - HR_Generic_Hinged_Single:Default. Manteluks lävepakuta. 1000 x 2100 mm. Left:523065 - ThresholdDepth: 92 mm; ThresholdThickness: 20 mm
OverallHeight: 2130 mm; OverallWidth: 1060 mm
Pset_DoorCommon - IsExternal: no; Reference: Default. Manteluks lävepakuta. 1000 x 2100 mm. Left
Pset_QuantityTakeOff - Reference: Default. Manteluks lävepakuta. 1000 x 2100 mm. Left

# IfcDoor: HR_Generic_Hinged_Single:Panipaik. Parem (5)
In: 1K
Type - ParameterTakesPrecedence: no; Sizeable: no; Material: _K. Metall. Plekk. Tsingitud
Type - HR_Generic_Hinged_Single:Panipaik. Parem:492096 - ThresholdDepth: 92 mm; ThresholdThickness: 20 mm
OverallHeight: 2130 mm; OverallWidth: 1060 mm
Pset_DoorCommon - IsExternal: no; Reference: Panipaik. Parem
Pset_QuantityTakeOff - Reference: Panipaik. Parem
Name (HR_Generic_Hinged_Single:Panipaik. Parem:...)
492096
492207
492224
492262
492279

# IfcDoor: HR_Generic_Hinged_Single:Panipaik. Vasak (7)
In: 1K
Type - ParameterTakesPrecedence: no; Sizeable: no; Material: _K. Metall. Plekk. Tsingitud
Type - HR_Generic_Hinged_Single:Panipaik. Vasak:491808 - ThresholdDepth: 92 mm; ThresholdThickness: 20 mm
OverallHeight: 2130 mm; OverallWidth: 1060 mm
Pset_DoorCommon - IsExternal: no; Reference: Panipaik. Vasak
Pset_QuantityTakeOff - Reference: Panipaik. Vasak
Name (HR_Generic_Hinged_Single:Panipaik. Vasak:...)
491808
491994
492011
492028
492045
492062
492079

# IfcFlowFitting: Elbow - Welded - SS:D+100 (6)
Type - Material: <Unnamed>
Pset_DistributionFlowElementCommon - Reference: D+100; sets with these values: 2
Pset_PipeFittingTypeCommon - NominalDiameter: 80
Name (Elbow - Welded - SS:D+100:...) | In | Group
777181 | 5K | Hydronic Supply 1
777192 | 5K | Hydronic Supply 1
784301 | 1K | Hydronic Supply 2
784312 | 1K | Hydronic Supply 2
784387 | 1K | Hydronic Supply 3
784401 | 1K | Hydronic Supply 3

# IfcFlowSegment: Pipe Types:Default (9)
Type - Material: _K. Metall. Plekk. Värvitud. Valge
Pset_DistributionFlowElementCommon - Reference: Default; sets with these values: 2
Pset_DuctConnection - ConnectionType: Generic; sets with these values: 2
Name (Pipe Types:Default:...) | In | Pset_FlowSegmentDuctSegment, Length (mm) = Pset_FlowSegmentPipeSegment, Length (mm) | InvertElevation (mm) | Group
777160 | 5K | 6657.93 | 2807.07 | Hydronic Supply 1
777169 | 5K | 3035.31 | 2272.03 | Hydronic Supply 1
777186 | 5K | 2137.93 | -6.15853 | Hydronic Supply 1
784283 | 1K | 13200.7 | 2546.06 | Hydronic Supply 2
784292 | 1K | 1241.5 | 2177.43 | Hydronic Supply 2
784306 | 1K | 2040.75 | -3.30495 | Hydronic Supply 2
784369 | 1K | 10143.5 | 2552.22 | Hydronic Supply 3
784378 | 1K | 1087.06 | 2184.1 | Hydronic Supply 3
784392 | 1K | 2043.53 | 0.907731 | Hydronic Supply 3

# IfcFlowTerminal: Drain-Roof-WATTS-Large_Area-Type_RD-100:2" (2)
Type - Material: Metal-WATTS-Cast Iron, Platic-WATTS_Polyethylene
Type - Pset_ManufacturerTypeInformation - Manufacturer: WATTS
Type - Pset_PipeConnectionFlanged - FlangeThickness: 7.9248 mm
Classification: D2040200 (Uniformat)
Pset_DistributionFlowElementCommon - Reference: 2"; sets with these values: 2
Name (Drain-Roof-WATTS-Large_Area-Type_RD-100:2":...) | In
275203 | Parapet
275469 | 5K

# IfcFlowTerminal: HR_Plumbing-fixtures_Bath_Generic_v1:Default, HR_Plumbing-fixtures_Bath_Generic_v1:Default:562632
In: 3-6.2
Type - Material: <Unnamed>
Pset_DistributionFlowElementCommon - Reference: Default; sets with these values: 2

# IfcFlowTerminal: HR_Plumbing-fixtures_Drain_Channel_Generic_v1:Default (10)
Type - Material: <Unnamed>
Pset_DistributionFlowElementCommon - Reference: Default; sets with these values: 2
Name (HR_Plumbing-fixtures_Drain_Channel_Generic_v1:Default:...) | In
644703 | 2-2.4
645500 | 2-1.4
646540 | 1-0.6
651320 | 2-3.4
652812 | 2-2.4
652814 | 2-1.4
652818 | 2-4.6
652821 | 2-3.4
658984 | 3-8.6
658987 | 3-7.4

# IfcFlowTerminal: HR_Plumbing-fixtures_Drain_Generic_v2:150x150 (3)
Type - Material: <Unnamed>
Pset_DistributionFlowElementCommon - Reference: 150x150; sets with these values: 2
Name (HR_Plumbing-fixtures_Drain_Generic_v2:150x150:...) | In
625330 | 1-0.3
625508 | 1-0.4
625547 | 1K

# IfcFlowTerminal: HR_Plumbing-fixtures_Faucet_Generic_v1:Default (12)
Type - Material: <Unnamed>
Pset_DistributionFlowElementCommon - Reference: Default; sets with these values: 2
Name (HR_Plumbing-fixtures_Faucet_Generic_v1:Default:...) | In | Group
634737 | 2-1.2 | Model Group:Mööbel. Tyykorrus:651438
647712 | 2-4.2 | Model Group:Mööbel. Tyykorrus:651438
648967 | 2-2.2 | Model Group:Mööbel. Tyykorrus:651438
649993 | 2-3.2 | Model Group:Mööbel. Tyykorrus:651438
652428 | 3-5.2 | Model Group:Mööbel. Tyykorrus:652539
652495 | 3-8.2 | Model Group:Mööbel. Tyykorrus:652539
652512 | 3-6.2 | Model Group:Mööbel. Tyykorrus:652539
652524 | 3-7.2 | Model Group:Mööbel. Tyykorrus:652539
653148 | 4-9.2 | Model Group:Mööbel. 4K:653259
653215 | 4-11.2 | Model Group:Mööbel. 4K:653259
653244 | 4-10.2 | Model Group:Mööbel. 4K:653259
661781 | 5-12.4

# IfcFlowTerminal: HR_Plumbing-fixtures_Shower-mixer_Generic_v1:Default (10)
Type - Material: <Unnamed>
Pset_DistributionFlowElementCommon - Reference: Default; sets with these values: 2
Name (HR_Plumbing-fixtures_Shower-mixer_Generic_v1:Default:...) | In
639354 | 2-2.4
645499 | 2-1.4
646539 | 1-0.6
651319 | 2-3.4
652810 | 2-2.4
652813 | 2-1.4
652817 | 2-4.6
652820 | 2-3.4
658983 | 3-8.6
658986 | 3-7.4

# IfcFlowTerminal: HR_Plumbing-fixtures_Sink_Generic_Bathroom_v1:600 x 400 mm (18)
Type - Material: <Unnamed>
Pset_DistributionFlowElementCommon - Reference: 600 x 400 mm; sets with these values: 2
Name (HR_Plumbing-fixtures_Sink_Generic_Bathroom_v1:600 x 400 mm:...) | In | Group
505973 | 1-0.3
645101 | 2-2.4 | Model Group:Mööbel. Tyykorrus:651438
645803 | 2-1.4 | Model Group:Mööbel. Tyykorrus:651438
646622 | 2-4.6 | Model Group:Mööbel. Tyykorrus:651438
651367 | 2-3.4 | Model Group:Mööbel. Tyykorrus:651438
652471 | 3-6.4 | Model Group:Mööbel. Tyykorrus:652539
652476 | 3-5.4 | Model Group:Mööbel. Tyykorrus:652539
652480 | 3-8.6 | Model Group:Mööbel. Tyykorrus:652539
652536 | 3-7.4 | Model Group:Mööbel. Tyykorrus:652539
653191 | 4-9.1 | Model Group:Mööbel. 4K:653259
653196 | 4K | Model Group:Mööbel. 4K:653259
653200 | 4-11.5 | Model Group:Mööbel. 4K:653259
653256 | 4-10.4 | Model Group:Mööbel. 4K:653259
658072 | 4-9.6 | Model Group:Mööbel. 4K:653259
663498 | 5-12.11
663735 | 5-12.11
663893 | 5-12.5
664014 | 5-12.8

# IfcFlowTerminal: HR_Plumbing-fixtures_Sink_Generic_Kitchen_v1:Default (12)
Type - Material: <Unnamed>
Pset_DistributionFlowElementCommon - Reference: Default; sets with these values: 2
Name (HR_Plumbing-fixtures_Sink_Generic_Kitchen_v1:Default:...) | In | Group
634736 | 2-1.2 | Model Group:Mööbel. Tyykorrus:651438
647711 | 2-4.2 | Model Group:Mööbel. Tyykorrus:651438
648966 | 2-2.2 | Model Group:Mööbel. Tyykorrus:651438
649992 | 2-3.2 | Model Group:Mööbel. Tyykorrus:651438
652427 | 3-5.2 | Model Group:Mööbel. Tyykorrus:652539
652494 | 3-8.2 | Model Group:Mööbel. Tyykorrus:652539
652511 | 3-6.2 | Model Group:Mööbel. Tyykorrus:652539
652523 | 3-7.2 | Model Group:Mööbel. Tyykorrus:652539
653147 | 4-9.2 | Model Group:Mööbel. 4K:653259
653214 | 4-11.2 | Model Group:Mööbel. 4K:653259
653243 | 4-10.2 | Model Group:Mööbel. 4K:653259
661780 | 5-12.4

# IfcFlowTerminal: HR_Plumbing-fixtures_Toilet_Generic_v3:Default (14)
Type - Material: <Unnamed>
Pset_DistributionFlowElementCommon - Reference: Default; sets with these values: 2
Name (HR_Plumbing-fixtures_Toilet_Generic_v3:Default:...) | In
553312 | 2-3.4
553366 | 1-0.6
553421 | 2-1.4
553525 | 2-2.4
553652 | 3-7.4
553654 | 3-8.6
553656 | 3-5.4
553658 | 3-6.4
553753 | 3-6.1
554051 | 3-7.4
554115 | 3-8.6
662123 | 5-12.5
662245 | 5-12.11
663468 | 5-12.8

# IfcFlowTerminal: Plumbing-fixtures_Faucet_Gala_Noa:3893000 (18)
Type - Material: <Unnamed>
Pset_DistributionFlowElementCommon - Reference: 3893000; sets with these values: 2
Name (Plumbing-fixtures_Faucet_Gala_Noa:3893000:...) | In | Group
505974 | 1-0.3
645102 | 2-2.4 | Model Group:Mööbel. Tyykorrus:651438
645804 | 2-1.4 | Model Group:Mööbel. Tyykorrus:651438
646623 | 2-4.6 | Model Group:Mööbel. Tyykorrus:651438
651368 | 2-3.4 | Model Group:Mööbel. Tyykorrus:651438
652472 | 3-6.4 | Model Group:Mööbel. Tyykorrus:652539
652477 | 3-5.4 | Model Group:Mööbel. Tyykorrus:652539
652481 | 3-8.6 | Model Group:Mööbel. Tyykorrus:652539
652537 | 3-7.4 | Model Group:Mööbel. Tyykorrus:652539
653192 | 4-9.1 | Model Group:Mööbel. 4K:653259
653197 | 4K | Model Group:Mööbel. 4K:653259
653201 | 4-11.5 | Model Group:Mööbel. 4K:653259
653257 | 4-10.4 | Model Group:Mööbel. 4K:653259
658073 | 4-9.6 | Model Group:Mööbel. 4K:653259
663499 | 5-12.11
663736 | 5-12.11
663894 | 5-12.5
664015 | 5-12.8

# IfcFurnishingElement: HR_Casework-components_Front-panel_Generic_v1_1x:Default (40)
Type - Material: <Unnamed>
Pset_QuantityTakeOff - Reference: Default
Name (HR_Casework-components_Front-panel_Generic_v1_1x:Default:...) | In | Group
633716 | 2-1.2 | Model Group:Mööbel. Tyykorrus:651438
633927 | 2-1.2 | Model Group:Mööbel. Tyykorrus:651438
634917 | 2-1.4 | Model Group:Mööbel. Tyykorrus:651438
638295 | 2-2.4 | Model Group:Mööbel. Tyykorrus:651438
646811 | 2-4.7 | Model Group:Mööbel. Tyykorrus:651438
646946 | 2-4.7 | Model Group:Mööbel. Tyykorrus:651438
647316 | 2-4.2 | Model Group:Mööbel. Tyykorrus:651438
647325 | 2-4.2 | Model Group:Mööbel. Tyykorrus:651438
647617 | 2-4.2 | Model Group:Mööbel. Tyykorrus:651438
649139 | 2-2.2 | Model Group:Mööbel. Tyykorrus:651438
649250 | 2-2.2 | Model Group:Mööbel. Tyykorrus:651438
649996 | 2-3.2 | Model Group:Mööbel. Tyykorrus:651438
649998 | 2-3.2 | Model Group:Mööbel. Tyykorrus:651438
650484 | 2-3.2 | Model Group:Mööbel. Tyykorrus:651438
652421 | 3-5.2 | Model Group:Mööbel. Tyykorrus:652539
652423 | 3-5.2 | Model Group:Mööbel. Tyykorrus:652539
652431 | 3-5.4 | Model Group:Mööbel. Tyykorrus:652539
652469 | 3-6.4 | Model Group:Mööbel. Tyykorrus:652539
652484 | 3-8.7 | Model Group:Mööbel. Tyykorrus:652539
652486 | 3-8.7 | Model Group:Mööbel. Tyykorrus:652539
652488 | 3-8.2 | Model Group:Mööbel. Tyykorrus:652539
652490 | 3-8.2 | Model Group:Mööbel. Tyykorrus:652539
652493 | 3-8.2 | Model Group:Mööbel. Tyykorrus:652539
652515 | 3-6.2 | Model Group:Mööbel. Tyykorrus:652539
652517 | 3-6.2 | Model Group:Mööbel. Tyykorrus:652539
652526 | 3-7.2 | Model Group:Mööbel. Tyykorrus:652539
652528 | 3-7.2 | Model Group:Mööbel. Tyykorrus:652539
652532 | 3-7.2 | Model Group:Mööbel. Tyykorrus:652539
653141 | 4-9.2 | Model Group:Mööbel. 4K:653259
653143 | 4-9.2 | Model Group:Mööbel. 4K:653259
653204 | 4-10.2 | Model Group:Mööbel. 4K:653259
653206 | 4-10.2 | Model Group:Mööbel. 4K:653259
653210 | 4-11.2 | Model Group:Mööbel. 4K:653259
653213 | 4-11.2 | Model Group:Mööbel. 4K:653259
653237 | 4-9.6 | Model Group:Mööbel. 4K:653259
653248 | 4-10.2 | Model Group:Mööbel. 4K:653259
656511 | 4-9.2 | Model Group:Mööbel. 4K:653259
660925 | 5-12.4
661170 | 5-12.4
661919 | 5-12.4

# IfcFurnishingElement: HR_Casework_Kitchen_Generic_Appliance_v1:Dishwasher (12)
Type - Material: <Unnamed>
Type - Pset_FurnitureTypeCommon - Description: Nõudepesumasin
Pset_QuantityTakeOff - Reference: Dishwasher
Name (HR_Casework_Kitchen_Generic_Appliance_v1:Dishwasher:...) | In | Group
633926 | 2-1.2 | Model Group:Mööbel. Tyykorrus:651438
647616 | 2-4.2 | Model Group:Mööbel. Tyykorrus:651438
649249 | 2-2.2 | Model Group:Mööbel. Tyykorrus:651438
649997 | 2-3.2 | Model Group:Mööbel. Tyykorrus:651438
652422 | 2-1.2 | Model Group:Mööbel. Tyykorrus:652539
652492 | 2-4.2 | Model Group:Mööbel. Tyykorrus:652539
652516 | 2-2.2 | Model Group:Mööbel. Tyykorrus:652539
652527 | 2-3.2 | Model Group:Mööbel. Tyykorrus:652539
653142 | 3-5.2 | Model Group:Mööbel. 4K:653259
653212 | 3-8.2 | Model Group:Mööbel. 4K:653259
653236 | 3-6.1 | Model Group:Mööbel. 4K:653259
653247 | 3-7.1 | Model Group:Mööbel. 4K:653259

# IfcFurnishingElement: HR_Casework_Kitchen_Generic_Appliance_v1:Fridge (10)
Type - Material: <Unnamed>
Type - Pset_FurnitureTypeCommon - Description: Külmik
Pset_QuantityTakeOff - Reference: Fridge
Name (HR_Casework_Kitchen_Generic_Appliance_v1:Fridge:...) | In | Group
633715 | 2-1.2 | Model Group:Mööbel. Tyykorrus:651438
647324 | 2-4.2 | Model Group:Mööbel. Tyykorrus:651438
649138 | 2-2.2 | Model Group:Mööbel. Tyykorrus:651438
649995 | 2-3.2 | Model Group:Mööbel. Tyykorrus:651438
652420 | 2-1.2 | Model Group:Mööbel. Tyykorrus:652539
652489 | 2-4.2 | Model Group:Mööbel. Tyykorrus:652539
652514 | 2-2.2 | Model Group:Mööbel. Tyykorrus:652539
652525 | 2-3.2 | Model Group:Mööbel. Tyykorrus:652539
653140 | 3-5.2 | Model Group:Mööbel. 4K:653259
653209 | 4K | Model Group:Mööbel. 4K:653259

# IfcFurnishingElement: HR_Casework_Kitchen_Generic_Appliance_v1:Washing Machine (4)
Type - Material: <Unnamed>
Type - Pset_FurnitureTypeCommon - Description: Pesumasin
Pset_QuantityTakeOff - Reference: Washing Machine
Name (HR_Casework_Kitchen_Generic_Appliance_v1:Washing Machine:...) | In | Group
634916 | 2-1.4 | Model Group:Mööbel. Tyykorrus:651438
638294 | 2-2.4 | Model Group:Mööbel. Tyykorrus:651438
652430 | 2-1.4 | Model Group:Mööbel. Tyykorrus:652539
652468 | 2-2.4 | Model Group:Mööbel. Tyykorrus:652539

# IfcFurnishingElement: HR_Casework_Kitchen_Generic_Appliance_v3:Dishwasher (6)
Type - Material: <Unnamed>
Pset_QuantityTakeOff - Reference: Dishwasher
Name (HR_Casework_Kitchen_Generic_Appliance_v3:Dishwasher:...) | In | Group
646945 | 1-0.8 | Model Group:Mööbel. Tyykorrus:651438
647315 | 2-4.2 | Model Group:Mööbel. Tyykorrus:651438
652485 | 2-4.7 | Model Group:Mööbel. Tyykorrus:652539
652487 | 2-4.2 | Model Group:Mööbel. Tyykorrus:652539
653205 | 3-7.1 | Model Group:Mööbel. 4K:653259
656510 | 3-5.1 | Model Group:Mööbel. 4K:653259

# IfcFurnishingElement: HR_Casework_Kitchen_Generic_Appliance_v3:Fridge, HR_Casework_Kitchen_Generic_Appliance_v3:Fridge:661169
In: 5-12.4
Type - Material: <Unnamed>
Type - Pset_FurnitureTypeCommon - Description: Külmik
Pset_QuantityTakeOff - Reference: Fridge

# IfcFurnishingElement: HR_Casework_Kitchen_Generic_Appliance_v3:Vent (2)
In: 2-3.2
Type - Material: <Unnamed>
Type - Pset_FurnitureTypeCommon - Description: Ventseade
Pset_QuantityTakeOff - Reference: Vent
Name (HR_Casework_Kitchen_Generic_Appliance_v3:Vent:...) | Group
650483 | Model Group:Mööbel. Tyykorrus:651438
652531 | Model Group:Mööbel. Tyykorrus:652539

# IfcFurnishingElement: HR_Casework_Kitchen_Generic_Appliance_v4:Dishwasher, HR_Casework_Kitchen_Generic_Appliance_v4:Dishwasher:661918
In: 5-12.4
Type - Material: <Unnamed>
Type - Pset_FurnitureTypeCommon - Description: Nõudepesumasin
Pset_QuantityTakeOff - Reference: Dishwasher

# IfcFurnishingElement: HR_Casework_Kitchen_Generic_Appliance_v4:Fridge (2)
Type - Material: <Unnamed>
Type - Pset_FurnitureTypeCommon - Description: Külmik
Pset_QuantityTakeOff - Reference: Fridge
Name (HR_Casework_Kitchen_Generic_Appliance_v4:Fridge:...) | In
653203 | 3-7.1 | Group: Model Group:Mööbel. 4K:653259
660924 | 5-12.4

# IfcFurnishingElement: HR_Casework_Kitchen_Generic_Appliance_v4:Washing Machine (2)
Type - Material: <Unnamed>
Type - Pset_FurnitureTypeCommon - Description: Pesumasin
Pset_QuantityTakeOff - Reference: Washing Machine
Name (HR_Casework_Kitchen_Generic_Appliance_v4:Washing Machine:...) | In | Group
646810 | 1-0.8 | Model Group:Mööbel. Tyykorrus:651438
652483 | 2-4.7 | Model Group:Mööbel. Tyykorrus:652539

# IfcFurnishingElement: HR_Casework_Work-surface_Generic_Rectangular_v1:Default (33)
Type - Material: <Unnamed>
Pset_QuantityTakeOff - Reference: Default
Name (HR_Casework_Work-surface_Generic_Rectangular_v1:Default:...) | In | Group
634034 | 2-1.2 | Model Group:Mööbel. Tyykorrus:651438
644904 | 2-2.4 | Model Group:Mööbel. Tyykorrus:651438
645802 | 2-1.4 | Model Group:Mööbel. Tyykorrus:651438
646621 | 1-0.7 | Model Group:Mööbel. Tyykorrus:651438
647542 | 1-0.1 | Model Group:Mööbel. Tyykorrus:651438
648686 | 2-2.2 | Model Group:Mööbel. Tyykorrus:651438
648750 | 2-2.2 | Model Group:Mööbel. Tyykorrus:651438
649991 | 2-3.2 | Model Group:Mööbel. Tyykorrus:651438
650082 | 2-3.2 | Model Group:Mööbel. Tyykorrus:651438
650861 | 2-3.4 | Model Group:Mööbel. Tyykorrus:651438
652424 | 2-1.2 | Model Group:Mööbel. Tyykorrus:652539
652470 | 2-2.4 | Model Group:Mööbel. Tyykorrus:652539
652475 | 2-1.4 | Model Group:Mööbel. Tyykorrus:652539
652479 | 2-4.6 | Model Group:Mööbel. Tyykorrus:652539
652491 | 2-4.2 | Model Group:Mööbel. Tyykorrus:652539
652507 | 2-2.2 | Model Group:Mööbel. Tyykorrus:652539
652508 | 2-2.2 | Model Group:Mööbel. Tyykorrus:652539
652522 | 2-3.2 | Model Group:Mööbel. Tyykorrus:652539
652529 | 2-3.2 | Model Group:Mööbel. Tyykorrus:652539
652535 | 2-3.4 | Model Group:Mööbel. Tyykorrus:652539
653144 | 3-5.1 | Model Group:Mööbel. 4K:653259
653195 | 3-5.4 | Model Group:Mööbel. 4K:653259
653199 | 3-8.6 | Model Group:Mööbel. 4K:653259
653211 | 3-8.2 | Model Group:Mööbel. 4K:653259
653227 | 3-6.2 | Model Group:Mööbel. 4K:653259
653242 | 3-7.1 | Model Group:Mööbel. 4K:653259
653255 | 3-7.4 | Model Group:Mööbel. 4K:653259
660587 | 5-12.4
660821 | 5-12.4
661476 | 5-12.4
662583 | 5-12.5
663187 | 5-12.11
664013 | 5-12.8

# IfcFurnishingElement: HR_Furniture_Armchair_Generic_v1:Default, HR_Furniture_Armchair_Generic_v1:Default:660180
In: 5-12.4
Type - Material: <Unnamed>
Pset_QuantityTakeOff - Reference: Default

# IfcFurnishingElement: HR_Furniture_Bed_Generic_Double_v1:Default (12)
Type - Material: <Unnamed>
Pset_QuantityTakeOff - Reference: Default
Name (HR_Furniture_Bed_Generic_Double_v1:Default:...) | In | Group
625814 | 2-1.3 | Model Group:Kahene öökappidega:626272
626339 | 2-2.3 | Model Group:Kahene öökappidega:626342
626548 | 2-3.3 | Model Group:Kahene öökappidega:626551
626690 | 2-4.4 | Model Group:Kahene öökappidega:626693
652387 | 2-1.3 | Model Group:Kahene öökappidega:652390
652391 | 2-2.3 | Model Group:Kahene öökappidega:652394
652395 | 2-3.3 | Model Group:Kahene öökappidega:652398
652399 | 2-4.4 | Model Group:Kahene öökappidega:652402
653115 | 3-7.2 | Model Group:Kahene öökappidega:653118
653119 | 3-8.4 | Model Group:Kahene öökappidega:653122
658711 | 3-7.2 | Model Group:Kahene öökappidega:658714
659421 | 5-12.7 | Model Group:Kahene öökappidega:659424

# IfcFurnishingElement: HR_Furniture_Bed_Generic_Single_v1:Default (5)
Type - Material: <Unnamed>
Pset_QuantityTakeOff - Reference: Default
Name (HR_Furniture_Bed_Generic_Single_v1:Default:...) | In | Group
626953 | 2-4.5 | Model Group:Mööbel. Tyykorrus:651438
652403 | 2-4.5 | Model Group:Mööbel. Tyykorrus:652539
653123 | 3-6.2 | Model Group:Mööbel. 4K:653259
659029 | 5-12.13
659303 | 5-12.12

# IfcFurnishingElement: HR_Furniture_Bedside-table_Generic_v1:Default (24)
Type - Material: <Unnamed>
Pset_QuantityTakeOff - Reference: Default
Name (HR_Furniture_Bedside-table_Generic_v1:Default:...) | In | Group
625971 | 2-1.3 | Model Group:Kahene öökappidega:626272
626222 | 2-1.3 | Model Group:Kahene öökappidega:626272
626340 | 2-2.3 | Model Group:Kahene öökappidega:626342
626341 | 2-2.3 | Model Group:Kahene öökappidega:626342
626549 | 2-3.3 | Model Group:Kahene öökappidega:626551
626550 | 2-3.3 | Model Group:Kahene öökappidega:626551
626691 | 2-4.4 | Model Group:Kahene öökappidega:626693
626692 | 2-4.4 | Model Group:Kahene öökappidega:626693
652388 | 2-1.3 | Model Group:Kahene öökappidega:652390
652389 | 2-1.3 | Model Group:Kahene öökappidega:652390
652392 | 2-2.3 | Model Group:Kahene öökappidega:652394
652393 | 2-2.3 | Model Group:Kahene öökappidega:652394
652396 | 2-3.3 | Model Group:Kahene öökappidega:652398
652397 | 2-3.3 | Model Group:Kahene öökappidega:652398
652400 | 2-4.4 | Model Group:Kahene öökappidega:652402
652401 | 2-4.4 | Model Group:Kahene öökappidega:652402
653116 | 3-7.2 | Model Group:Kahene öökappidega:653118
653117 | 3-7.2 | Model Group:Kahene öökappidega:653118
653120 | 3-8.4 | Model Group:Kahene öökappidega:653122
653121 | 3-8.4 | Model Group:Kahene öökappidega:653122
658712 | 3-7.2 | Model Group:Kahene öökappidega:658714
658713 | 3-7.2 | Model Group:Kahene öökappidega:658714
659422 | 5-12.7 | Model Group:Kahene öökappidega:659424
659423 | 5-12.7 | Model Group:Kahene öökappidega:659424

# IfcFurnishingElement: HR_Furniture_Chair_Haworth_Very-Side:No Arms (54)
Type - Material: Haworth - Metal - Chrome, Haworth - Trim - Polymer Colors - Slate TR-FJ, Haworth - Trim - Polymer Colors - Glacier TR-FN
Type - Pset_FurnitureTypeCommon - Description: Haworth_Chair_Very-Perforated Side and Seminar
Type - Pset_ManufacturerTypeInformation - Manufacturer: Haworth
Classification: E2020200 (Uniformat)
Pset_QuantityTakeOff - Reference: No Arms
Name (HR_Furniture_Chair_Haworth_Very-Side:No Arms:...) | In | Group
637563 | 2-1.2 | Model Group:Neljane laud:637840
637997 | 2-1.2 | Model Group:Neljane laud:637840
638023 | 2-1.2 | Model Group:Neljane laud:637840
638024 | 2-1.2 | Model Group:Neljane laud:637840
638104 | 2-3.2 | Model Group:Neljane laud:638105
638106 | 2-3.2 | Model Group:Neljane laud:638105
638107 | 2-3.2 | Model Group:Neljane laud:638105
638108 | 2-3.2 | Model Group:Neljane laud:638105
648343 | 1-0.17 | Model Group:Kuuene laud:648344
648345 | 2-4.2 | Model Group:Kuuene laud:648344
648346 | 2-4.2 | Model Group:Kuuene laud:648344
648347 | 2-4.2 | Model Group:Kuuene laud:648344
648576 | 1-0.17 | Model Group:Kuuene laud:648344
648577 | 2-4.2 | Model Group:Kuuene laud:648344
649397 | 2-2.2 | Model Group:Kahene laud:649395
649398 | 2-2.2 | Model Group:Kahene laud:649395
652457 | 2-1.2 | Model Group:Neljane laud:652458
652459 | 2-1.2 | Model Group:Neljane laud:652458
652460 | 2-1.2 | Model Group:Neljane laud:652458
652461 | 2-1.2 | Model Group:Neljane laud:652458
652463 | 2-3.2 | Model Group:Neljane laud:652464
652465 | 2-3.2 | Model Group:Neljane laud:652464
652466 | 2-3.2 | Model Group:Neljane laud:652464
652467 | 2-3.2 | Model Group:Neljane laud:652464
652500 | 2-4.2 | Model Group:Kuuene laud:652501
652502 | 2-4.2 | Model Group:Kuuene laud:652501
652503 | 2-4.2 | Model Group:Kuuene laud:652501
652504 | 2-4.2 | Model Group:Kuuene laud:652501
652505 | 2-4.2 | Model Group:Kuuene laud:652501
652506 | 2-4.2 | Model Group:Kuuene laud:652501
652520 | 2-2.2 | Model Group:Kahene laud:652519
652521 | 2-2.2 | Model Group:Kahene laud:652519
653183 | 3-8.4 | Model Group:Neljane laud:653184
653185 | 3-8.4 | Model Group:Neljane laud:653184
653186 | 3-8.4 | Model Group:Neljane laud:653184
653187 | 3-8.4 | Model Group:Neljane laud:653184
653220 | 3-8.2 | Model Group:Kuuene laud:653221
653222 | 3-8.2 | Model Group:Kuuene laud:653221
653223 | 3-8.2 | Model Group:Kuuene laud:653221
653224 | 3-8.2 | Model Group:Kuuene laud:653221
653225 | 3-8.2 | Model Group:Kuuene laud:653221
653226 | 3-8.2 | Model Group:Kuuene laud:653221
656733 | 3-5.2 | Model Group:Kuuene laud:656734
656735 | 3-5.2 | Model Group:Kuuene laud:656734
656736 | 3-5.2 | Model Group:Kuuene laud:656734
656737 | 3-5.2 | Model Group:Kuuene laud:656734
656738 | 3-5.2 | Model Group:Kuuene laud:656734
656739 | 3-5.2 | Model Group:Kuuene laud:656734
660366 | 5-12.4 | Model Group:Kuuene laud:660367
660368 | 5-12.4 | Model Group:Kuuene laud:660367
660369 | 5-12.4 | Model Group:Kuuene laud:660367
660370 | 5-12.4 | Model Group:Kuuene laud:660367
660371 | 5-12.4 | Model Group:Kuuene laud:660367
660372 | 5-12.4 | Model Group:Kuuene laud:660367

# IfcFurnishingElement: HR_Furniture_Chair_Haworth_Very-Task:Height Adjustable Arms (5)
Type - Material: Haworth - Paint - Smoke TR-E, Haworth - Metal - Polished Aluminum, Haworth - Plastic - Black, Haworth - Fabric - Zody Mesh - Comfort MA-002, Haworth - Fabric - Zinger - Gravel NI-4
Type - Pset_FurnitureTypeCommon - Description: Very Task Chair
Type - Pset_ManufacturerTypeInformation - Manufacturer: Haworth
Classification: E2020200 (Uniformat)
Pset_QuantityTakeOff - Reference: Height Adjustable Arms
Name (HR_Furniture_Chair_Haworth_Very-Task:Height Adjustable Arms:...) | In | Group
632146 | 2-4.5 | Model Group:Mööbel. Tyykorrus:651438
652405 | 3-8.5 | Model Group:Mööbel. Tyykorrus:652539
653125 | 4-9.4 | Model Group:Mööbel. 4K:653259
659738 | 5-12.12
659933 | 5-12.13

# IfcFurnishingElement: HR_Furniture_Couch_Generic_v1_Middle:Default (48)
Type - Material: <Unnamed>
Pset_QuantityTakeOff - Reference: Default
Name (HR_Furniture_Couch_Generic_v1_Middle:Default:...) | In | Group
635045 | 2-1.2 | Model Group:Nurgatiivan:635475
635344 | 2-1.2 | Model Group:Nurgatiivan:635475
635352 | 2-1.2 | Model Group:Nurgatiivan:635475
635362 | 2-1.2 | Model Group:Nurgatiivan:635475
635676 | 2-3.2 | Model Group:Nurgatiivan:635681
635678 | 2-3.2 | Model Group:Nurgatiivan:635681
635679 | 2-3.2 | Model Group:Nurgatiivan:635681
635680 | 2-3.2 | Model Group:Nurgatiivan:635681
635800 | 2-2.2 | Model Group:Nurgatiivan:635805
635802 | 2-2.2 | Model Group:Nurgatiivan:635805
635803 | 2-2.2 | Model Group:Nurgatiivan:635805
635804 | 2-2.2 | Model Group:Nurgatiivan:635805
635879 | 2-4.2 | Model Group:Nurgatiivan:635884
635881 | 2-4.2 | Model Group:Nurgatiivan:635884
635882 | 2-4.2 | Model Group:Nurgatiivan:635884
635883 | 1-0.15 | Model Group:Nurgatiivan:635884
652432 | 2-1.2 | Model Group:Nurgatiivan:652437
652434 | 2-1.2 | Model Group:Nurgatiivan:652437
652435 | 2-1.2 | Model Group:Nurgatiivan:652437
652436 | 2-1.2 | Model Group:Nurgatiivan:652437
652438 | 2-3.2 | Model Group:Nurgatiivan:652443
652440 | 2-3.2 | Model Group:Nurgatiivan:652443
652441 | 2-3.2 | Model Group:Nurgatiivan:652443
652442 | 2-3.2 | Model Group:Nurgatiivan:652443
652444 | 2-2.2 | Model Group:Nurgatiivan:652449
652446 | 2-2.2 | Model Group:Nurgatiivan:652449
652447 | 2-2.2 | Model Group:Nurgatiivan:652449
652448 | 2-2.2 | Model Group:Nurgatiivan:652449
652450 | 2-4.2 | Model Group:Nurgatiivan:652455
652452 | 2-4.2 | Model Group:Nurgatiivan:652455
652453 | 2-4.2 | Model Group:Nurgatiivan:652455
652454 | 2-4.2 | Model Group:Nurgatiivan:652455
653158 | 3-5.3 | Model Group:Nurgatiivan:653163
653160 | 3-5.3 | Model Group:Nurgatiivan:653163
653161 | 3-5.3 | Model Group:Nurgatiivan:653163
653162 | 3-5.3 | Model Group:Nurgatiivan:653163
653170 | 3-8.2 | Model Group:Nurgatiivan:653175
653172 | 3-8.2 | Model Group:Nurgatiivan:653175
653173 | 3-8.2 | Model Group:Nurgatiivan:653175
653174 | 3-8.2 | Model Group:Nurgatiivan:653175
654503 | 3-7.3 | Model Group:Nurgatiivan:654508
654505 | 3-7.3 | Model Group:Nurgatiivan:654508
654506 | 3-7.3 | Model Group:Nurgatiivan:654508
654507 | 3-7.3 | Model Group:Nurgatiivan:654508
660023 | 5-12.4 | Model Group:Nurgatiivan:660028
660025 | 5-12.4 | Model Group:Nurgatiivan:660028
660026 | 5-12.4 | Model Group:Nurgatiivan:660028
660027 | 5-12.4 | Model Group:Nurgatiivan:660028

# IfcFurnishingElement: HR_Furniture_Couch_Generic_v1_Side:Default (12)
Type - Material: <Unnamed>
Pset_QuantityTakeOff - Reference: Default
Name (HR_Furniture_Couch_Generic_v1_Side:Default:...) | In | Group
635105 | 2-1.2 | Model Group:Nurgatiivan:635475
635677 | 2-3.2 | Model Group:Nurgatiivan:635681
635801 | 2-2.2 | Model Group:Nurgatiivan:635805
635880 | 2-4.2 | Model Group:Nurgatiivan:635884
652433 | 2-1.2 | Model Group:Nurgatiivan:652437
652439 | 2-3.2 | Model Group:Nurgatiivan:652443
652445 | 2-2.2 | Model Group:Nurgatiivan:652449
652451 | 2-4.2 | Model Group:Nurgatiivan:652455
653159 | 3-5.3 | Model Group:Nurgatiivan:653163
653171 | 3-8.2 | Model Group:Nurgatiivan:653175
654504 | 3-7.3 | Model Group:Nurgatiivan:654508
660024 | 5-12.4 | Model Group:Nurgatiivan:660028

# IfcFurnishingElement: HR_Furniture_Office-desk_Placeholder_v2:Default (5)
Type - Material: <Unnamed>
Pset_QuantityTakeOff - Reference: Default
Name (HR_Furniture_Office-desk_Placeholder_v2:Default:...) | In | Group
632145 | 1-0.12 | Model Group:Mööbel. Tyykorrus:651438
652404 | 2-4.5 | Model Group:Mööbel. Tyykorrus:652539
653124 | 3-6.3 | Model Group:Mööbel. 4K:653259
659737 | 5-12.12
659932 | 5-12.13

# IfcFurnishingElement: HR_Furniture_TV-stand_Generic_v2016-05-13:Default (12)
Type - Material: <Unnamed>
Pset_QuantityTakeOff - Reference: Default
Name (HR_Furniture_TV-stand_Generic_v2016-05-13:Default:...) | In | Group
632537 | 2-3.2 | Model Group:TV:632929
632995 | 1-0.6 | Model Group:TV:632997
633007 | 2-2.2 | Model Group:TV:633009
633019 | 2-1.2 | Model Group:TV:633021
652406 | 2-3.2 | Model Group:TV:652408
652409 | 2-4.2 | Model Group:TV:652411
652412 | 2-2.2 | Model Group:TV:652414
652415 | 2-1.2 | Model Group:TV:652417
653126 | 3-7.3 | Model Group:TV:653128
653129 | 3-8.2 | Model Group:TV:653131
653135 | 3-6.3 | Model Group:TV:653137
660020 | 5K | Model Group:TV:660022

# IfcFurnishingElement: HR_Furniture_Table_Generic_v2016-02-11:1600x1000 (5)
Type - Material: <Unnamed>
Pset_QuantityTakeOff - Reference: 1600x1000
Name (HR_Furniture_Table_Generic_v2016-02-11:1600x1000:...) | In | Group
637354 | 2-1.2 | Model Group:Neljane laud:637840
638103 | 2-3.2 | Model Group:Neljane laud:638105
652456 | 2-1.2 | Model Group:Neljane laud:652458
652462 | 2-3.2 | Model Group:Neljane laud:652464
653182 | 3-8.4 | Model Group:Neljane laud:653184

# IfcFurnishingElement: HR_Furniture_Table_Generic_v2016-02-11:1600x800 (2)
In: 2-2.2
Type - Material: <Unnamed>
Pset_QuantityTakeOff - Reference: 1600x800
Name (HR_Furniture_Table_Generic_v2016-02-11:1600x800:...) | Group
649393 | Model Group:Kahene laud:649395
652518 | Model Group:Kahene laud:652519

# IfcFurnishingElement: HR_Furniture_Table_Generic_v2016-02-11:2000x1000 (5)
Type - Material: <Unnamed>
Pset_QuantityTakeOff - Reference: 2000x1000
Name (HR_Furniture_Table_Generic_v2016-02-11:2000x1000:...) | In | Group
648342 | 1-0.17 | Model Group:Kuuene laud:648344
652499 | 2-4.2 | Model Group:Kuuene laud:652501
653219 | 3-8.2 | Model Group:Kuuene laud:653221
656732 | 3-5.2 | Model Group:Kuuene laud:656734
660365 | 5-12.4 | Model Group:Kuuene laud:660367

# IfcFurnishingElement: HR_Furniture_Wardrobe_Clothes-rack:Default (36)
Type - Material: <Unnamed>
Pset_QuantityTakeOff - Reference: Default
Name (HR_Furniture_Wardrobe_Clothes-rack:Default:...) | In
541345 | 4-11.1
541610 | 4-11.1
542081 | 4-11.4
542876 | 4-10.3
543322 | 4-9.5
543607 | 4-9.4
544278 | 4-9.1
544785 | 4-10.1
545191 | 3-5.3
545476 | 3-6.3
545724 | 3-7.1
546096 | 3-7.3
546558 | 3-8.4
547855 | 3-8.5
548008 | 3-8.5
548191 | 3-8.1
548379 | 3-8.1
548680 | 3-5.1
549015 | 3-6.1
549116 | 2-1.3
549117 | 2-2.3
549118 | 2-3.1
549119 | 2-3.3
549120 | 2-4.4
549121 | 2-4.5
549122 | 2-4.5
549123 | 2-4.1
549124 | 2-4.1
549125 | 2-1.1
549126 | 2-2.1
549348 | 5-12.12
549639 | 5-12.13
550041 | 5-12.2
550436 | 5-12.2
550730 | 5-12.7
551087 | 5-12.7

# IfcGroup: Model Group:Kahene laud (2)
Name (Model Group:Kahene laud:...) | Group
649395 | Model Group:Mööbel. Tyykorrus:651438
652519 | Model Group:Mööbel. Tyykorrus:652539

# IfcGroup: Model Group:Kahene öökappidega (12)
Name (Model Group:Kahene öökappidega:...) | Group
626272 | Model Group:Mööbel. Tyykorrus:651438
626342 | Model Group:Mööbel. Tyykorrus:651438
626551 | Model Group:Mööbel. Tyykorrus:651438
626693 | Model Group:Mööbel. Tyykorrus:651438
652390 | Model Group:Mööbel. Tyykorrus:652539
652394 | Model Group:Mööbel. Tyykorrus:652539
652398 | Model Group:Mööbel. Tyykorrus:652539
652402 | Model Group:Mööbel. Tyykorrus:652539
653118 | Model Group:Mööbel. 4K:653259
653122 | Model Group:Mööbel. 4K:653259
658714 | Model Group:Mööbel. 4K:653259
659424

# IfcGroup: Model Group:Kuuene laud (5)
Name (Model Group:Kuuene laud:...) | Group
648344 | Model Group:Mööbel. Tyykorrus:651438
652501 | Model Group:Mööbel. Tyykorrus:652539
653221 | Model Group:Mööbel. 4K:653259
656734 | Model Group:Mööbel. 4K:653259
660367

# IfcGroup: Model Group:Neljane laud (5)
Name (Model Group:Neljane laud:...) | Group
637840 | Model Group:Mööbel. Tyykorrus:651438
638105 | Model Group:Mööbel. Tyykorrus:651438
652458 | Model Group:Mööbel. Tyykorrus:652539
652464 | Model Group:Mööbel. Tyykorrus:652539
653184 | Model Group:Mööbel. 4K:653259

# IfcGroup: Model Group:Nurgatiivan (12)
Name (Model Group:Nurgatiivan:...) | Group
635475 | Model Group:Mööbel. Tyykorrus:651438
635681 | Model Group:Mööbel. Tyykorrus:651438
635805 | Model Group:Mööbel. Tyykorrus:651438
635884 | Model Group:Mööbel. Tyykorrus:651438
652437 | Model Group:Mööbel. Tyykorrus:652539
652443 | Model Group:Mööbel. Tyykorrus:652539
652449 | Model Group:Mööbel. Tyykorrus:652539
652455 | Model Group:Mööbel. Tyykorrus:652539
653163 | Model Group:Mööbel. 4K:653259
653175 | Model Group:Mööbel. 4K:653259
654508 | Model Group:Mööbel. 4K:653259
660028

# IfcGroup: Model Group:TV (12)
Name (Model Group:TV:...) | Group
632929 | Model Group:Mööbel. Tyykorrus:651438
632997 | Model Group:Mööbel. Tyykorrus:651438
633009 | Model Group:Mööbel. Tyykorrus:651438
633021 | Model Group:Mööbel. Tyykorrus:651438
652408 | Model Group:Mööbel. Tyykorrus:652539
652411 | Model Group:Mööbel. Tyykorrus:652539
652414 | Model Group:Mööbel. Tyykorrus:652539
652417 | Model Group:Mööbel. Tyykorrus:652539
653128 | Model Group:Mööbel. 4K:653259
653131 | Model Group:Mööbel. 4K:653259
653137 | Model Group:Mööbel. 4K:653259
660022

# IfcOpeningElement: Opening (302)
Name | In | Reference | sets with these values
Basic Wall:Columbia 240mm:206201 | 1K | Default. Klaasprofiiluks lävepakuga. 1500 x 2100 mm | 2
Basic Wall:SS-01. 190:208199 | 1K | Default. Manteluks lävepakuga. 1000 x 2100 mm. Right | 2
Basic Wall:SS-01. 190:208202 | 1K | Default. Manteluks lävepakuga. 1000 x 2100 mm. Right | 2
2 x Basic Wall:SS-01. 190:208202 | 1K | Default | 2
2 x Basic Wall:SS-01. 190:209903 | 2K | Default | 2
6 x Basic Wall:SS-01. 190:210072 | 2K | A-01.400x2400.ma | 2
Basic Wall:SS-01. 190:210332:1 | 2K | SS-01. 190 | 2
Basic Wall:SS-01. 190:210332:2 | 2K | SS-01. 190 | 2
7 x Basic Wall:SS-01. 190:210420 | 2K | A-01.400x2400.ma | 2
7 x Basic Wall:SS-01. 190:210420 | 2K | A-13.1200x2400.P | 2
3 x Basic Wall:SS-01. 190:210420 | 2K | A-02. 800x2400. ma | 2
2 x Basic Wall:SS-01. 190:210420 | 2K | A-10.800x2400.P | 2
2 x Basic Wall:SS-01. 190:210420 | 2K | A-09.800x2400.V | 2
Basic Wall:SS-01. 190:210420 | 2K | A-04.1600x2400.ma | 2
Basic Wall:SS-01. 190:210512:1 | 2K | SS-01. 190 | 2
Basic Wall:SS-01. 190:210512:2 | 2K | SS-01. 190 | 2
Basic Wall:SS-01. 190:210512:3 | 2K | SS-01. 190 | 2
Basic Wall:SS-01. 190:210512:4 | 2K | SS-01. 190 | 2
Basic Wall:SS-01. 190:210512:5 | 2K | SS-01. 190 | 2
Basic Wall:SS-01. 190:210512:6 | 2K | SS-01. 190 | 2
Basic Wall:SS-01. 190:210512:7 | 2K | SS-01. 190 | 2
2 x Basic Wall:Columbia 190mm:210753 | 2K | A-01.400x2400.ma | 2
2 x Basic Wall:Columbia 190mm:210753 | 2K | A-13.1200x2400.P | 2
6 x Basic Wall:Columbia 190mm:210917 | 2K | A-01.400x2400.ma | 2
2 x Basic Wall:Columbia 190mm:210917 | 2K | A-13.1200x2400.P | 2
Basic Wall:SS-01. 190:213113 | 3K | Default | 2
6 x Basic Wall:SS-01. 190:213114 | 3K | A-01.400x2400.ma | 2
Basic Wall:SS-01. 190:213116 | 3K | A-10.800x2400.P | 2
Basic Wall:SS-01. 190:213116 | 3K | A-04.1600x2400.ma | 2
4 x Basic Wall:SS-01. 190:213117 | 3K | A-13.1200x2400.P | 2
Basic Wall:SS-01. 190:213117 | 3K | A-02. 800x2400. ma | 2
Basic Wall:SS-01. 190:213117 | 3K | A-10.800x2400.P | 2
Basic Wall:SS-01. 190:213117 | 3K | A-09.800x2400.V | 2
4 x Basic Wall:SS-01. 190:213117 | 3K | A-01.400x2400.ma | 2
Basic Wall:SS-01. 190:213118 | 3K | A-13.1200x2400.P | 2
Basic Wall:SS-01. 190:213118 | 3K | A-02. 800x2400. ma | 2
Basic Wall:SS-01. 190:213118 | 3K | A-10.800x2400.P | 2
3 x Basic Wall:SS-01. 190:213118 | 3K | A-01.400x2400.ma | 2
Basic Wall:Columbia 190mm:213119 | 3K | A-13.1200x2400.P | 2
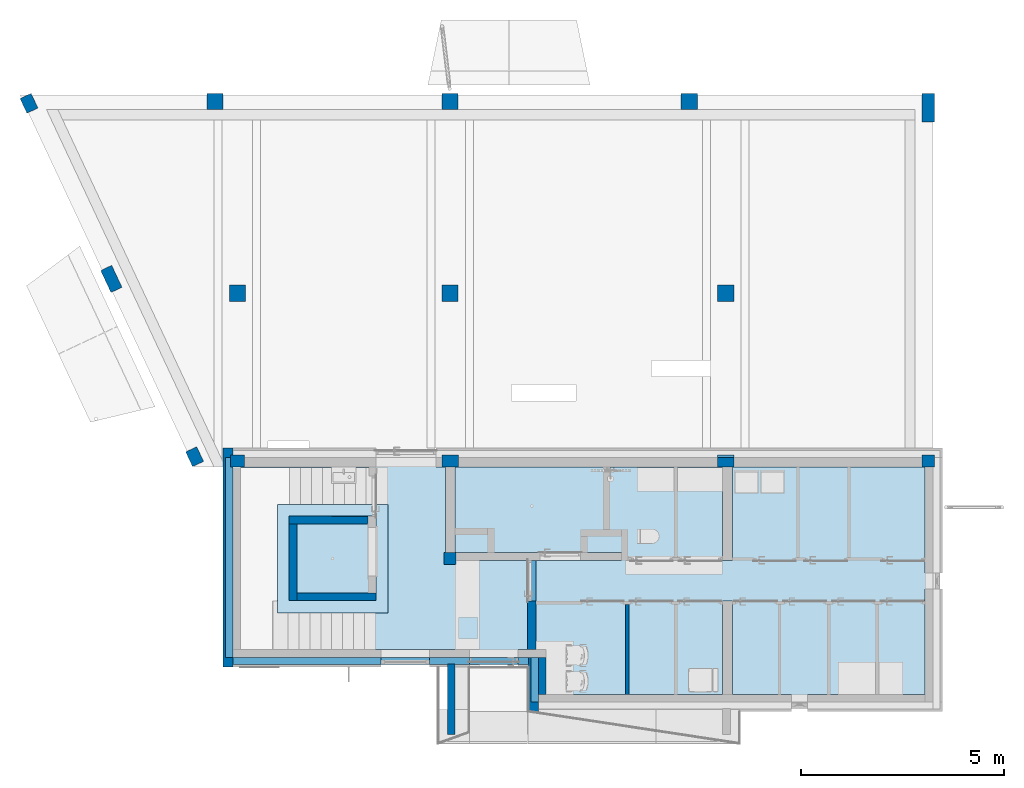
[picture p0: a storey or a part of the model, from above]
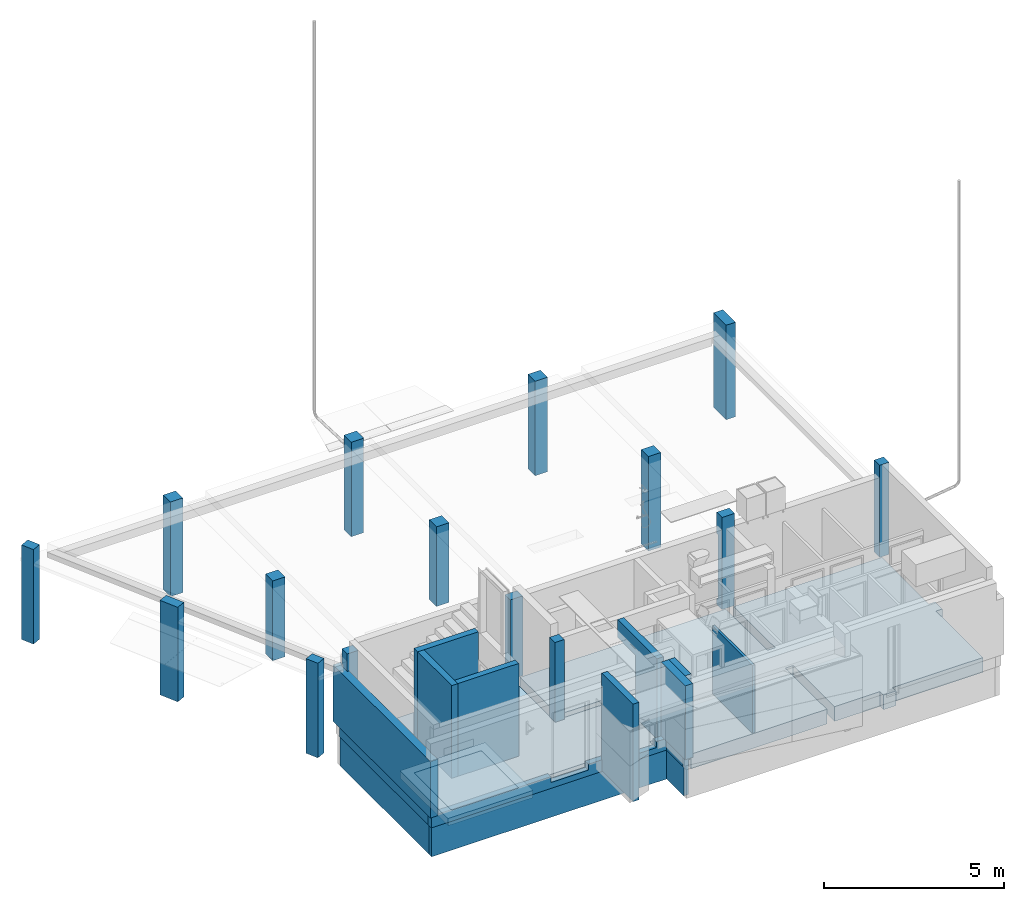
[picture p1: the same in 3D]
Properties of the parts of a building model (IFC2X3), part 3 of 3

# IfcOpeningElement: Opening (302)
Name | In | Reference | sets with these values
Basic Wall:Columbia 190mm:213119 | 3K | A-01.400x2400.ma | 2
Basic Wall:Columbia 190mm:213121 | 3K | A-13.1200x2400.P | 2
3 x Basic Wall:Columbia 190mm:213121 | 3K | A-01.400x2400.ma | 2
3 x Basic Wall:SS-01. 190:213187 | 4K | A-01.400x2400.ma | 2
2 x Basic Wall:SS-01. 190:213187 | 4K | A-13.1200x2400.P | 2
Basic Wall:SS-01. 190:213187 | 4K | A-02. 800x2400. ma | 2
Basic Wall:SS-01. 190:213187 | 4K | A-10.800x2400.P | 2
Basic Wall:Columbia 190mm:213188 | 4K | A-01.400x2400.ma | 2
Basic Wall:Columbia 190mm:213188 | 4K | A-13.1200x2400.P | 2
3 x Basic Wall:Columbia 190mm:213190 | 4K | A-01.400x2400.ma | 2
Basic Wall:Columbia 190mm:213190 | 4K | A-13.1200x2400.P | 2
2 x Basic Wall:SS-01. 190:213206 | 5K | A-10.800x2400.P | 2
3 x Basic Wall:SS-01. 190:213206 | 5K | A-01.400x2400.ma | 2
Basic Wall:SS-01. 190:213206 | 5K | A-04.1600x2400.ma | 2
Basic Wall:SS-01. 190:213206 | 5K | A-03.1200x2400.ma | 2
2 x Basic Wall:Columbia 190mm:213213 | 5K | A-01.400x2400.ma | 2
Basic Wall:Columbia 190mm:213213 | 5K | A-04.1600x2400.ma | 2
Basic Wall:Columbia 190mm:213215 | 5K | A-13.1200x2400.P | 2
5 x Floor:VL-01-B:755083 | 5K | VL-01-B | 2
Floor:VL-01-B:216255 | 5K | 800 | 2
Floor:VL-01-B:216255 | 5K | 1748 | 2
5 x Floor:VL-01-A:216257 | 4K | VL-01-A | 2
Floor:VL-01-A:217246 | 4K | 1080 | 2
Floor:VL-01-A:217246 | 4K | Shower_slope | 2
4 x Floor:VL-01-A:216257 | 3K | VL-01-A | 2
Floor:VL-01-A:217875 | 3K | 1200 | 2
Floor:VL-01-A:217875 | 3K | 1080 | 2
Floor:VL-01-A:217875 | 3K | Shower_slope | 2
4 x Floor:VL-01-A:216257 | 2K | VL-01-A | 2
Floor:VL-01-A:217960 | 2K | 1200 | 2
Floor:VL-01-A:217960 | 2K | Shower_slope | 2
Floor:VL-01-A:217960 | 2K | 1080 | 2
Basic Wall:VS-01:218079 | 2K | A-13.1200x2400.P | 2
3 x Basic Wall:VS-01:218079 | 2K | A-01.400x2400.ma | 2
Basic Wall:VS-01:218091 | 2K | A-15.400x2400.ma | 2
Basic Wall:VS-01:218176 | 2K | Default. Manteluks lävepakuga. 1000 x 2100 mm. Left | 2
Basic Wall:VS-01:218176 | 2K | Default. Klaasprofiiluks lävepakuga. 1500 x 2100 mm | 2
3 x Basic Wall:VS-01:218297 | 3K | A-01.400x2400.ma | 2
Basic Wall:VS-01:218298 | 3K | Default. Manteluks lävepakuga. 1000 x 2100 mm. Left | 2
Basic Wall:VS-01:218298 | 3K | Default. Manteluks lävepakuga. 1000 x 2100 mm. Right | 2
2 x Basic Wall:VS-01:218347 | 4K | A-02. 800x2400. ma | 2
2 x Basic Wall:VS-01:218347 | 4K | A-09.800x2400.V | 2
Basic Wall:VS-01:218347 | 4K | A-10.800x2400.P | 2
Basic Wall:VS-01:218347 | 4K | A-13.1200x2400.P | 2
Basic Wall:VS-01:218347 | 4K | Default. Manteluks lävepakuga. 800 x 2100 mm. Right | 2
Basic Wall:VS-01:218347 | 4K | Default. Manteluks lävepakuga. 800 x 2100 mm. Left | 2
Basic Wall:SS-402:277708 | 2K | Default. Manteluks lävepakuga. 800 x 2100 mm. Left | 2
Basic Wall:SS-402:279087 | 2K | Default. Manteluks lävepakuga. 800 x 2100 mm. Right | 2
Basic Wall:SS-01. 190:280995:1 | 2K | SS-01. 190 | 2
Basic Wall:SS-402:285313 | 3K | Default. Manteluks lävepakuga. 800 x 2100 mm. Left | 2
Basic Wall:SS-402:285320 | 3K | Default. Manteluks lävepakuga. 800 x 2100 mm. Right | 2
Basic Wall:SS-01. 190:285332:1 | 3K | SS-01. 190 | 2
Basic Wall:SS-402:289712 | 4K | Default. Manteluks lävepakuga. 800 x 2100 mm. Left | 2
Basic Wall:SS-401:294891:1 | 5K | SS-401 | 2
Basic Wall:SS-01. 190:345422 | 1K | Default. Manteluks lävepakuga. 1000 x 2100 mm. Left | 2
2 x Basic Wall:VS-01 krohv:358104 | 4K | A-13.1200x2400.P | 2
2 x Basic Wall:VS-01 krohv:358104 | 4K | A-01.400x2400.ma | 2
Basic Wall:VS-01 krohv:358104 | 4K | A-10.800x2400.P | 2
Basic Wall:VS-01 krohv:358104 | 4K | A-02. 800x2400. ma | 2
Floor:PP-01:506187 | 1K | PP-01 | 2
Basic Wall:VS-00:524253 | 1K | Default. Klaasprofiiluks lävepakuga. 1500 x 2100 mm | 2
Basic Wall:VS-00:524325 | 1K | A-08.400x2115.P | 2
Basic Wall:VS-00:524453 | 1K | A-16.400x2400.P | 2
Basic Wall:VS-00:524769 | 1K | A-03.1200x2400.ma | 2
Basic Wall:VS-00:524769 | 1K | Default. Klaasprofiiluks lävepakuga. 1200 x 2100 mm. Left | 2
Floor:Liftišaht:525170 | 1K | Liftišaht | 2
Basic Wall:SS-01. 190:763011 | 4K | 300x300 | 2
2 x Basic Wall:SS-01. 190:763011 | 4K | A-13.1200x2400.P | 2
2 x Basic Wall:SS-01. 190:763011 | 4K | A-01.400x2400.ma | 2
Basic Wall:SS-01. 190:763011 | 4K | A-10.800x2400.P | 2
Basic Wall:SS-01. 190:763011 | 4K | A-02. 800x2400. ma | 2
Basic Wall:VS-01:763647 | 4K | 300x300 | 2
2 x Basic Wall:VS-01:763647 | 4K | A-13.1200x2400.P | 2
5 x Basic Wall:VS-01:763647 | 4K | A-01.400x2400.ma | 2
2 x Basic Wall:VS-01:763647 | 4K | A-10.800x2400.P | 2
Basic Wall:VS-01:763647 | 4K | A-02. 800x2400. ma | 2
Basic Wall:VS-01:763647 | 4K | A-03.1200x2400.ma | 2
4 x Basic Wall:VS-01:218079 | 2K
Basic Wall:VS-01:218091 | 2K
HR_Louver_Rectangle_v1:150x150:364631:1 | 2K
HR_Louver_Rectangle_v1:150x150:365898:1 | 2K
6 x Basic Wall:VS-01:218291 | 3K
2 x Basic Wall:VS-01:218292 | 3K
4 x Basic Wall:VS-01:218294 | 3K
Basic Wall:VS-01:218296 | 3K
3 x Basic Wall:VS-01:218297 | 3K
7 x Basic Wall:VS-01:218345 | 4K
4 x Basic Wall:VS-01:218348 | 4K
Basic Wall:VS-01:218350 | 4K
6 x Basic Wall:VS-01:218445 | 5K
HR_Louver_Rectangle_v1:300x300:364515:1 | 5K
3 x Basic Wall:VS-01:218449 | 5K
Basic Wall:VS-01:218451 | 5K
7 x Basic Wall:VS-01:218452 | 5K
Basic Wall:VS-01:218807 | 1K
Basic Wall:VS-01:218873 | 1K
Basic Wall:VS-01:763647 | 4K
2 x Basic Wall:SS-401:276828 | 2K
Basic Wall:SS-402:277707 | 2K
Basic Wall:SS-402:279086 | 2K
Basic Wall:SS-401:279296 | 2K
2 x Basic Wall:SS-401:283477 | 2K
Basic Wall:SS-401:283540 | 2K
2 x Basic Wall:SS-401:285308 | 3K
Basic Wall:SS-402:285312 | 3K
Basic Wall:SS-402:285319 | 3K
Basic Wall:SS-401:285322 | 3K
Basic Wall:SS-401:285340 | 3K
Basic Wall:SS-401:285351 | 3K
2 x Basic Wall:SS-401:286638 | 4K
Basic Wall:SS-01. 190:288125 | 4K
Basic Wall:SS-402:289775 | 4K
Basic Wall:SS-401:292214 | 5K
Basic Wall:SS-401:292577 | 5K
Basic Wall:SS-401:292690 | 5K
Basic Wall:SS-401:294544 | 5K
Basic Wall:SS-401:294632 | 5K
Basic Wall:SS-401:294891 | 5K
Basic Wall:SS-01. 190:345422 | 1K
Basic Wall:SS-01. 190:345983 | 1K
HR_Louver_Rectangle_v1:300x300:364573:1 | 4K
3 x Basic Wall:SS-07. Panipaik:489526 | 1K
4 x Basic Wall:SS-07. Panipaik:489669 | 1K
3 x Basic Wall:SS-07. Panipaik:490121 | 1K
2 x Basic Wall:SS-07. Panipaik:490321 | 1K
Basic Wall:SS-03. Šahti sein:495713 | 1K
Basic Wall:SS-03. Šahti sein:509441 | 5K
Basic Wall:SS-401:510145 | 5K
Basic Wall:SS-401:536169 | 2K
Basic Wall:SS-401:537616 | 3K

# IfcRailing: Railing:RFIX-GPR1-BaseFixDrainage-Glass_W8+8-H1100_NoTopRail (12)
Type - Pset_ManufacturerTypeInformation - Manufacturer: RFIX
Material: Default, _K. Klaas. Kirgas, _K. Avatäited. Raam. Alumiinium, Rubber, Metal - Steel
Pset_QuantityTakeOff - Reference: RFIX-GPR1-BaseFixDrainage-Glass_W8+8-H1100_NoTopRail
Pset_RailingCommon - IsExternal: no; Reference: RFIX-GPR1-BaseFixDrainage-Glass_W8+8-H1100_NoTopRail; Height: 1000 mm
Name (Railing:RFIX-GPR1-BaseFixDrainage-Glass_W8+8-H1100_NoTopRail:...) | In
362468 | 4K
366725 | 5K
427848 | 2K
429227 | 3K
429239 | 4K
429263 | 5K
429751 | 2K
430067 | 3K
430079 | 4K
431147 | 2K
432013 | 3K
483639 | 5K

# IfcRoof: Basic Roof:KL-01, Basic Roof:KL-01:256263
In: Parapet
Material: _K. Katusekate. Rullmaterjal. SBS 10 mm, _K. Soojustus. Mineraalvill 30 mm, _K. Soojustus. EPS 190 mm, _K. Soojustus. EPS 300 mm, _K. Aurutõke. Rullmaterjal. SBS 5 mm, _K. Betoon. Armeeritud. Monteeritav 220 mm
Pset_QuantityTakeOff - Reference: KL-01
Pset_RoofCommon - IsExternal: yes; Reference: KL-01; TotalArea: 175.144 m2

# IfcRoof: Basic Roof:KL-01 müts (6)
In: Parapet
Material: _K. Katusekate. Rullmaterjal. SBS 10 mm, _K. Soojustus. Mineraalvill 100 mm, _K. Ehitusplaat. Vineer. Veekindel 15 mm
Pset_QuantityTakeOff - Reference: KL-01 müts
Pset_RoofCommon - IsExternal: yes; Reference: KL-01 müts
Name (Basic Roof:KL-01 müts:...) | ProjectedArea (m2) | TotalArea (m2)
367869 | 1.26378 | 1.26428
368015 | 1.592 | 1.5925
368037 | 1.48 | 1.48046
368057 | 1.216 | 1.21639
368075 | 1.00015 | 1.00044
368097 | 0.91584 | 0.916193

# IfcRoof: Basic Roof:KL-02 (2)
Material: _K. Katusekate. Rullmaterjal. PVC(1) 2 mm, _K. Betoon. Armeeritud. Kohtvalu 80 mm, _K. Soojustus. EPS 50 mm, _K. Soojustus. EPS 150 mm, _K. Aurutõke. Rullmaterjal. SBS 5 mm, _K. Betoon. Armeeritud. Monteeritav 220 mm
Pset_QuantityTakeOff - Reference: KL-02
Pset_RoofCommon - IsExternal: yes; Reference: KL-02
Name (Basic Roof:KL-02:...) | In | ProjectedArea (m2) | TotalArea (m2)
356679 | 3K | 27.0514 | 30.0177
358163 | 5K | 77.0456 | 80.4067

# IfcRoof: Basic Roof:KL-02 2 (2)
Material: _K. Katusekate. Rullmaterjal. PVC(1) 2.5 mm, _K. Betoon. Armeeritud. Kohtvalu 65 mm
Pset_QuantityTakeOff - Reference: KL-02 2
Pset_RoofCommon - IsExternal: yes; Reference: KL-02 2
Name (Basic Roof:KL-02 2:...) | In | ProjectedArea (m2) = TotalArea (m2)
362856 | 4K | 2.96621
366141 | 5K | 4.5108

# IfcRoof: Basic Roof:KL-05, Basic Roof:KL-05:257737
In: Parapet
Material: _K. Katusekate. Rullmaterjal. SBS 10 mm, _K. Soojustus. Mineraalvill 30 mm, _K. Soojustus. EPS 50 mm, _K. Soojustus. EPS 100 mm, _K. Aurutõke. Rullmaterjal. SBS 5 mm
Pset_QuantityTakeOff - Reference: KL-05
Pset_RoofCommon - IsExternal: yes; Reference: KL-05; ProjectedArea: 9.42735 m2; TotalArea: 7.40963 m2

# IfcRoof: Basic Roof:KL-05 2, Basic Roof:KL-05 2:266489
In: Parapet
Material: _K. Betoon. Armeeritud. Monteeritav 200 mm
Pset_QuantityTakeOff - Reference: KL-05 2
Pset_RoofCommon - IsExternal: yes; Reference: KL-05 2; ProjectedArea: 4.43041 m2; TotalArea: 4.43041 m2

# IfcRoof: Basic Roof:KL-05 3 (2)
In: Parapet
Material: _K. Katusekate. Rullmaterjal. SBS 10 mm, _K. Soojustus. Mineraalvill 30 mm, _K. Soojustus. EPS 250 mm, _K. Soojustus. EPS 30 mm
Pset_QuantityTakeOff - Reference: KL-05 3
Pset_RoofCommon - IsExternal: yes; Reference: KL-05 3
Name (Basic Roof:KL-05 3:...) | ProjectedArea (m2) | TotalArea (m2)
784416 | 2.82623 | 2.83433
784731 | 1.85638 | 1.86494

# IfcRoof: Basic Roof:KL-06 (5)
Material: _K. Katusekate. Rullmaterjal. SBS 10 mm, _K. Ehitusplaat. Vineer. Veekindel 15 mm, _K. Õhk. Roov. Fassaadikatte alusroov. Horisontaalne. 25 mm 100 mm, _K. Õhk. Roov. Fassaadikatte alusroov. Horisontaalne. 25 mm 100 mm
Pset_QuantityTakeOff - Reference: KL-06
Pset_RoofCommon - IsExternal: yes; Reference: KL-06
Name (Basic Roof:KL-06:...) | In | TotalArea (m2)
474202 | 4K | 6.37884
476530 | 5K | 5.78077
478325 | 5K | 4.52491
480918 | 5K | 14.0095 | Pset_RoofCommon - ProjectedArea: 14.0095 m2
482373 | 5K | 9.21952 | Pset_RoofCommon - ProjectedArea: 9.21952 m2

# IfcSlab: Basic Roof:KL-01 müts (7)
In: Parapet
PredefinedType: ROOF; Material: _K. Katusekate. Rullmaterjal. SBS 10 mm, _K. Soojustus. Mineraalvill 100 mm, _K. Ehitusplaat. Vineer. Veekindel 15 mm
Pset_QuantityTakeOff - Reference: KL-01 müts; sets with these values: 2
Pset_SlabCommon - IsExternal: yes; Reference: KL-01 müts
Name (Basic Roof:KL-01 müts:...) | PitchAngle (deg)
368015 | 1.4321
368037 | 1.4321
2 x 368057 | 1.43229
368057 | 1.47827
368075 | 1.38035
368097 | 1.59114

# IfcSlab: Basic Roof:KL-02 2 (2)
PredefinedType: ROOF; Material: _K. Katusekate. Rullmaterjal. PVC(1) 2.5 mm, _K. Betoon. Armeeritud. Kohtvalu 65 mm
Pset_QuantityTakeOff - Reference: KL-02 2; sets with these values: 2
Pset_SlabCommon - IsExternal: yes; PitchAngle: 0 deg; Reference: KL-02 2
Name (Basic Roof:KL-02 2:...) | In
362856 | 4K
366141 | 5K

# IfcSlab: Basic Roof:KL-05 2, Basic Roof:KL-05 2:266489
In: Parapet
PredefinedType: ROOF; Material: _K. Betoon. Armeeritud. Monteeritav 200 mm
Pset_QuantityTakeOff - Reference: KL-05 2; sets with these values: 2
Pset_SlabCommon - IsExternal: yes; PitchAngle: 0 deg; Reference: KL-05 2

# IfcSlab: Basic Roof:KL-06 (2)
In: 5K
PredefinedType: ROOF; Material: _K. Katusekate. Rullmaterjal. SBS 10 mm, _K. Ehitusplaat. Vineer. Veekindel 15 mm, _K. Õhk. Roov. Fassaadikatte alusroov. Horisontaalne. 25 mm 100 mm, _K. Õhk. Roov. Fassaadikatte alusroov. Horisontaalne. 25 mm 100 mm
Pset_QuantityTakeOff - Reference: KL-06; sets with these values: 2
Pset_SlabCommon - IsExternal: yes; PitchAngle: 0 deg; Reference: KL-06
Name (Basic Roof:KL-06:...)
480918
482373

# IfcSlab: Floor:Liftišaht (2)
In: 1K
Type - PredefinedType: FLOOR; Material: _K. Betoon. Armeeritud. Kohtvalu 250 mm
Pset_QuantityTakeOff - Reference: Liftišaht; sets with these values: 2
Pset_SlabCommon - IsExternal: no; LoadBearing: no; PitchAngle: 0 deg; Reference: Liftišaht
Name (Floor:Liftišaht:...)
525168
525261

# IfcSlab: Floor:PP-01 (2)
In: 1K
Type - PredefinedType: FLOOR; Material: _K. Betoon. Armeeritud. Kohtvalu 100 mm, _K. Soojustus. EPS 200 mm, _K. Puistematerjal. Killustik 200 mm
Pset_QuantityTakeOff - Reference: PP-01; sets with these values: 2
Pset_SlabCommon - IsExternal: no; LoadBearing: no; PitchAngle: 0 deg; Reference: PP-01
Name (Floor:PP-01:...)
506185
506974

# IfcSlab: Floor:VL-01-A (3)
Type - PredefinedType: FLOOR; Material: _K. Betoon. Armeeritud. Kohtvalu 80 mm, _K. Soojustus. Mineraalvill 30 mm, _K. Soojustus. EPS 25 mm, _K. Betoon. Armeeritud. Monteeritav 265 mm
Pset_QuantityTakeOff - Reference: VL-01-A; sets with these values: 2
Pset_SlabCommon - IsExternal: no; LoadBearing: no; PitchAngle: 0 deg; Reference: VL-01-A
Name (Floor:VL-01-A:...) | In
217246 | 4K
217875 | 3K
217960 | 2K | Material: _K. Betoon. Armeeritud. Kohtvalu, _K. Soojustus. Mineraalvill, _K. Soojustus. EPS, _K. Betoon. Armeeritud. Monteeritav

# IfcSlab: Floor:VL-01-B, Floor:VL-01-B:216255
In: 5K
Type - PredefinedType: FLOOR; Material: _K. Betoon. Armeeritud. Kohtvalu 80 mm, _K. Soojustus. Mineraalvill 30 mm, _K. Soojustus. EPS 176 mm, _K. Soojustus. EPS 25 mm, _K. Betoon. Armeeritud. Monteeritav 265 mm
Pset_QuantityTakeOff - Reference: VL-01-B; sets with these values: 2
Pset_SlabCommon - IsExternal: no; LoadBearing: no; Reference: VL-01-B; PitchAngle: 0 deg

# IfcSlab: Floor:VL-03 (3)
Type - PredefinedType: FLOOR
Material: _K. Betoon. Armeeritud. Kohtvalu, _K. Soojustus. Mineraalvill, _K. Soojustus. EPS, _K. Betoon. Armeeritud. Monteeritav
Pset_QuantityTakeOff - Reference: VL-03; sets with these values: 2
Pset_SlabCommon - IsExternal: no; LoadBearing: no; PitchAngle: 0 deg; Reference: VL-03
Name (Floor:VL-03:...) | In
788232 | 2K
788723 | 3K
788745 | 4K

# IfcSlab: Floor:VL-03 B, Floor:VL-03 B:788766
In: 5K
Type - PredefinedType: FLOOR
Material: _K. Betoon. Armeeritud. Kohtvalu, _K. Soojustus. Mineraalvill, _K. Soojustus. EPS, _K. Betoon. Armeeritud. Monteeritav
Pset_QuantityTakeOff - Reference: VL-03 B; sets with these values: 2
Pset_SlabCommon - IsExternal: no; LoadBearing: no; PitchAngle: 0 deg; Reference: VL-03 B

# IfcSlab: HR_Slab_Balcony_v3:Default (10)
Type - PredefinedType: FLOOR; Material: _K. Betoon. Armeeritud. Monteeritav
Pset_QuantityTakeOff - Reference: Default; sets with these values: 2
Pset_SlabCommon - IsExternal: yes; Reference: Default
Name (HR_Slab_Balcony_v3:Default:...) | In
427670 | 2K
428303 | 3K
428311 | 4K
428319 | 5K
429516 | 2K
430064 | 3K
430076 | 4K
431144 | 2K
432010 | 3K
482710 | 5K

# IfcSlab: Monolithic Landing:Default Landing. Raudbetoon (4)
Type - PredefinedType: LANDING
Material: Temp. Betoon. Armeeritud. Kohtvalu
Pset_QuantityTakeOff - Reference: Default Landing. Raudbetoon; sets with these values: 2
Pset_SlabCommon - IsExternal: no; PitchAngle: 0 deg; Reference: Default Landing. Raudbetoon
Name (Precast Stair:Stair:...) | In
496210 Landing 1 | 1K
508931 Landing 1 | 2K
508940 Landing 1 | 3K
508949 Landing 1 | 4K

# IfcStair: Precast Stair:Default. Monteeritav raudbetoontrepp (4)
ShapeType: HALF_TURN_STAIR
Pset_QuantityTakeOff - Reference: Default. Monteeritav raudbetoontrepp
Pset_StairCommon - IsExternal: no; Reference: Default. Monteeritav raudbetoontrepp; NumberOfRiser: 19; NumberOfTreads: 18; TreadLength: 270 mm
Name (Precast Stair:Stair:...) | In | RiserHeight (mm)
496210 | 1K | 173.611
508931 | 2K | 176.111
508940 | 3K | 176.111
508949 | 4K | 176.111

# IfcStairFlight: Monolithic Run:Default Run. Raudbetoon (8)
Type - PredefinedType: STRAIGHT
Type - Pset_StairFlightCommon - NosingLength: 0 mm
NumberOfTreads: 9; TreadLength: 0.885827 mm; Material: Temp. Betoon. Armeeritud. Kohtvalu
Pset_QuantityTakeOff - Reference: Default Run. Raudbetoon
Pset_StairFlightCommon - Reference: Default Run. Raudbetoon; NumberOfTreads: 9; TreadLength: 270 mm; WalkingLineOffset: 1.9685 mm; TreadLengthAtOffset: 270 mm; TreadLengthAtInnerSide: 270 mm
Name (Precast Stair:Stair:...) | In | NumberOfRiser = Pset_StairFlightCommon, NumberOfRiser | RiserHeight (mm) | Pset_StairFlightCommon, RiserHeight (mm)
496210 Run 1 | 1K | 9 | 0.56959 | 173.611
496210 Run 2 | 1K | 10 | 0.56959 | 173.611
508931 Run 1 | 2K | 9 | 0.577792 | 176.111
508931 Run 2 | 2K | 10 | 0.577792 | 176.111
508940 Run 1 | 3K | 9 | 0.577792 | 176.111
508940 Run 2 | 3K | 10 | 0.577792 | 176.111
508949 Run 1 | 4K | 9 | 0.577792 | 176.111
508949 Run 2 | 4K | 10 | 0.577792 | 176.111

# IfcWall: Basic Wall:Columbia 190mm (6)
Type - PredefinedType: STANDARD; Material: _K. Müüritis. Väikeplokk. Betoon-õõnesplokk 190 mm
Pset_QuantityTakeOff - Reference: Columbia 190mm; sets with these values: 2
Pset_WallCommon - IsExternal: no; LoadBearing: no; Reference: Columbia 190mm
Name (Basic Wall:Columbia 190mm:...) | In | ExtendToStructure
206406 | 1K | no
206608 | 1K | no
211152 | 2K | yes
213123 | 3K | yes
213189 | 4K | yes
213192 | 4K | yes

# IfcWall: Basic Wall:Columbia 240mm (4)
Type - PredefinedType: STANDARD; Material: _K. Müüritis. Väikeplokk. Betoon-õõnesplokk 240 mm
Pset_QuantityTakeOff - Reference: Columbia 240mm; sets with these values: 2
Pset_WallCommon - Reference: Columbia 240mm; IsExternal: yes; LoadBearing: no
Name (Basic Wall:Columbia 240mm:...) | In | ExtendToStructure
206513 | 1K | no
213115 | 3K | yes
213184 | 4K | yes
213207 | 5K | no

# IfcWall: Basic Wall:SL (2)
In: Parapet
Type - PredefinedType: STANDARD; Material: _K. Müüritis. Väikeplokk. Kergkruusplokk 190 mm
Pset_QuantityTakeOff - Reference: SL; sets with these values: 2
Pset_WallCommon - IsExternal: no; ExtendToStructure: no; LoadBearing: no; Reference: SL
Name (Basic Wall:SL:...)
858050
858231

# IfcWall: Basic Wall:SS-01. 190 (14)
Type - PredefinedType: STANDARD; Material: _K. Väisviimistlus. Krohv. Valge 5 mm, _K. Müüritis. Väikeplokk. Betoon-õõnesplokk 190 mm, _K. Väisviimistlus. Krohv. Valge 5 mm
Pset_QuantityTakeOff - Reference: SS-01. 190; sets with these values: 2
Pset_WallCommon - IsExternal: no; LoadBearing: no; Reference: SS-01. 190
Name (Basic Wall:SS-01. 190:...) | In | ExtendToStructure
206268 | 1K | no
206660 | 1K | no
213183 | 4K | yes
213186 | 4K | yes
213205 | 5K | no
213209 | 5K | no
213212 | 5K | no
277922 | 2K | no
279180 | 2K | no
285314 | 3K | no
285321 | 3K | no
287351 | 4K | no
287914 | 4K | no
288829 | 4K | no

# IfcWall: Basic Wall:SS-01.240 (5)
Type - PredefinedType: STANDARD; Material: _K. Väisviimistlus. Krohv. Valge 5 mm, _K. Müüritis. Väikeplokk. Betoon-õõnesplokk 240 mm, _K. Väisviimistlus. Krohv. Valge 5 mm
Pset_QuantityTakeOff - Reference: SS-01.240; sets with these values: 2
Pset_WallCommon - IsExternal: yes; LoadBearing: no; Reference: SS-01.240
Name (Basic Wall:SS-01.240:...) | In | ExtendToStructure
210154 | 2K | yes
211257 | 2K | yes
211375 | 2K | yes
213125 | 3K | yes
213194 | 4K | no

# IfcWall: Basic Wall:SS-03. Šahti sein (32)
Type - PredefinedType: STANDARD; Material: _K. Väisviimistlus. Krohv. Valge 10 mm, _K. Müüritis. Väikeplokk. Kergkruusplokk 150 mm, _K. Väisviimistlus. Krohv. Valge 10 mm
Pset_QuantityTakeOff - Reference: SS-03. Šahti sein; sets with these values: 2
Pset_WallCommon - IsExternal: no; ExtendToStructure: no; LoadBearing: no; Reference: SS-03. Šahti sein
Name (Basic Wall:SS-03. Šahti sein:...) | In
282464 | 2K
283234 | 2K
283310 | 2K
283403 | 2K
283404 | 2K
283405 | 2K
285334 | 3K
285335 | 3K
285344 | 3K
285345 | 3K
285346 | 3K
285347 | 3K
285348 | 3K
285349 | 3K
286805 | 4K
290872 | 4K
290873 | 4K
290874 | 4K
290875 | 4K
290876 | 4K
290877 | 4K
292327 | 5K
292328 | 5K
292329 | 5K
292330 | 5K
292337 | 5K
292340 | 5K
292341 | 5K
292342 | 5K
292343 | 5K
292344 | 5K
345420 | 1K

# IfcWall: Basic Wall:SS-401 (10)
Type - PredefinedType: STANDARD; Material: _K. Ehitusplaat. Kipsplaat. Erikõva 13 mm, _K. Soojustus. Mineraalvill 66 mm, _K. Ehitusplaat. Kipsplaat. Erikõva 13 mm
Pset_QuantityTakeOff - Reference: SS-401; sets with these values: 2
Pset_WallCommon - IsExternal: no; ExtendToStructure: no; LoadBearing: no; Reference: SS-401
Name (Basic Wall:SS-401:...) | In
282536 | 2K
285350 | 3K
289257 | 4K
289325 | 4K
289397 | 4K
289924 | 4K
290951 | 4K
291264 | 4K
293317 | 5K
296687 | 5K

# IfcWall: Basic Wall:VS-01 (13)
Type - PredefinedType: STANDARD; Material: _K. Väisviimistlus. Krohv. Valge 10 mm, _K. Soojustus. EPS Silver 230 mm
Pset_QuantityTakeOff - Reference: VS-01; sets with these values: 2
Pset_WallCommon - IsExternal: no; LoadBearing: no; Reference: VS-01
Name (Basic Wall:VS-01:...) | In | ExtendToStructure
218049 | 2K | no
218055 | 2K | no
218061 | 2K | no
218067 | 2K | no
218097 | 2K | no
218289 | 3K | yes
218290 | 3K | yes
218344 | 4K | no
218346 | 4K | no
218351 | 4K | no
218448 | 5K | no
219219 | 1K | no
350872 | 1K | no

# IfcWall: Basic Wall:VS-01 krohv, Basic Wall:VS-01 krohv:764257
In: 5K
Type - PredefinedType: STANDARD; Material: _K. Väisviimistlus. Krohv. Valge 10 mm
Pset_QuantityTakeOff - Reference: VS-01 krohv; sets with these values: 2
Pset_WallCommon - IsExternal: no; ExtendToStructure: no; LoadBearing: no; Reference: VS-01 krohv

# IfcWall: Basic Wall:VS-Tala (2)
In: 1K
Type - PredefinedType: STANDARD; Material: _K. Välisviimistlus. Alumiinium-komposiitplaat. Must 4 mm, _K. Soojustus. Mineraalvill 250 mm
Pset_QuantityTakeOff - Reference: VS-Tala; sets with these values: 2
Pset_WallCommon - IsExternal: no; ExtendToStructure: no; LoadBearing: no; Reference: VS-Tala
Name (Basic Wall:VS-Tala:...)
527797
527951

# IfcWall: Basic Wall:VS-komposiit (41)
Type - PredefinedType: STANDARD
Pset_QuantityTakeOff - Reference: VS-komposiit; sets with these values: 2
Pset_WallCommon - IsExternal: no; LoadBearing: no; Reference: VS-komposiit
Name (Basic Wall:VS-komposiit:...) | In | ExtendToStructure
428624 | 2K | no
428657 | 2K | no
428741 | 2K | yes
429170 | 2K | no
429171 | 2K | no
429172 | 2K | yes
429307 | 2K | no
429308 | 2K | no
429309 | 2K | yes
429405 | 2K | no
429406 | 2K | no
429407 | 2K | yes
430407 | 2K | no
430408 | 2K | no
430409 | 2K | yes
430940 | 2K | no
430941 | 2K | no
430942 | 2K | yes
479277 | 5K | yes
479279 | 5K | no
479918 | 5K | no
480230 | 5K | yes
480231 | 5K | no
480233 | 5K | no
480923 | Parapet | no
482234 | 5K | yes
482235 | 5K | no
482236 | 5K | no
482293 | 5K | yes
482294 | 5K | no
482295 | 5K | no
482374 | Parapet | no
483600 | 5K | no
484114 | 1K | no
484232 | 1K | no
485468 | 1K | no
485621 | 1K | yes
485805 | 1K | no
486356 | 1K | no
486425 | 1K | no
487274 | 1K | no

# IfcWall: Basic Wall:VS-liftimüts, Basic Wall:VS-liftimüts:266842
In: Parapet
Type - PredefinedType: STANDARD; Material: _K. Katusekate. Rullmaterjal. SBS 10 mm, _K. Soojustus. Mineraalvill 30 mm, _K. Soojustus. EPS 170 mm
Pset_QuantityTakeOff - Reference: VS-liftimüts; sets with these values: 2
Pset_WallCommon - IsExternal: no; ExtendToStructure: no; LoadBearing: no; Reference: VS-liftimüts

# IfcWall: Basic Wall:VS-Šahtimüts (5)
In: Parapet
Type - PredefinedType: STANDARD; Material: _K. Katusekate. Rullmaterjal. SBS 10 mm, _K. Soojustus. Mineraalvill 100 mm, _K. Müüritis. Väikeplokk. Kergkruusplokk 100 mm
Pset_QuantityTakeOff - Reference: VS-Šahtimüts; sets with these values: 2
Pset_WallCommon - IsExternal: no; ExtendToStructure: no; LoadBearing: no; Reference: VS-Šahtimüts
Name (Basic Wall:VS-Šahtimüts:...)
272756
272757
272759
272808
272826

# IfcWallStandardCase: Basic Wall:Columbia 190mm (22)
Type - PredefinedType: STANDARD; Material: _K. Müüritis. Väikeplokk. Betoon-õõnesplokk 190 mm
Pset_QuantityTakeOff - Reference: Columbia 190mm; sets with these values: 2
Pset_WallCommon - IsExternal: no; LoadBearing: no; Reference: Columbia 190mm
Name (Basic Wall:Columbia 190mm:...) | In | ExtendToStructure
208201 | 1K | no
208605 | 1K | no
208775 | 1K | no
208784 | 1K | no
209902 | 2K | yes
210753 | 2K | yes
210807 | 2K | yes
210917 | 2K | yes
211022 | 2K | yes
213112 | 3K | yes
213119 | 3K | yes
213120 | 3K | yes
213121 | 3K | yes
213122 | 3K | yes
213181 | 4K | yes
213188 | 4K | yes
213190 | 4K | yes
213191 | 4K | yes
213204 | 5K | no
213213 | 5K | no
213215 | 5K | no
215927 | 5K | no

# IfcWallStandardCase: Basic Wall:Columbia 240mm (3)
In: 1K
Type - PredefinedType: STANDARD; Material: _K. Müüritis. Väikeplokk. Betoon-õõnesplokk 240 mm
Pset_QuantityTakeOff - Reference: Columbia 240mm; sets with these values: 2
Pset_WallCommon - Reference: Columbia 240mm; IsExternal: yes; ExtendToStructure: no; LoadBearing: no
Name (Basic Wall:Columbia 240mm:...)
206043
206201
207367

# IfcWallStandardCase: Basic Wall:SL (2)
In: Parapet
Type - PredefinedType: STANDARD; Material: _K. Müüritis. Väikeplokk. Kergkruusplokk 190 mm
Pset_QuantityTakeOff - Reference: SL; sets with these values: 2
Pset_WallCommon - IsExternal: no; ExtendToStructure: no; LoadBearing: no; Reference: SL
Name (Basic Wall:SL:...)
858096
858174

# IfcWallStandardCase: Basic Wall:SS-01. 190 (38)
Type - PredefinedType: STANDARD; Material: _K. Väisviimistlus. Krohv. Valge 5 mm, _K. Müüritis. Väikeplokk. Betoon-õõnesplokk 190 mm, _K. Väisviimistlus. Krohv. Valge 5 mm
Pset_QuantityTakeOff - Reference: SS-01. 190; sets with these values: 2
Pset_WallCommon - IsExternal: no; LoadBearing: no; Reference: SS-01. 190
Name (Basic Wall:SS-01. 190:...) | In | ExtendToStructure
208199 | 1K | no
208200 | 1K | no
208202 | 1K | no
209900 | 2K | yes
209901 | 2K | yes
209903 | 2K | yes
210072 | 2K | yes
210332 | 2K | yes
210420 | 2K | yes
210512 | 2K | yes
213110 | 3K | yes
213111 | 3K | yes
213113 | 3K | yes
213114 | 3K | yes
213116 | 3K | no
213117 | 3K | yes
213118 | 3K | yes
213179 | 4K | yes
213180 | 4K | yes
213182 | 4K | yes
213187 | 4K | no
213202 | 5K | no
213203 | 5K | no
213206 | 5K | no
279432 | 2K | no
279794 | 2K | no
280995 | 2K | no
285323 | 3K | no
285324 | 3K | no
285332 | 3K | no
287130 | 4K | no
288125 | 4K | no
288370 | 4K | no
288688 | 4K | no
290642 | 4K | no
345422 | 1K | no
345983 | 1K | no
763011 | 4K | no

# IfcWallStandardCase: Basic Wall:SS-01.240 (5)
Type - PredefinedType: STANDARD; Material: _K. Väisviimistlus. Krohv. Valge 5 mm, _K. Müüritis. Väikeplokk. Betoon-õõnesplokk 240 mm, _K. Väisviimistlus. Krohv. Valge 5 mm
Pset_QuantityTakeOff - Reference: SS-01.240; sets with these values: 2
Pset_WallCommon - IsExternal: yes; LoadBearing: no; Reference: SS-01.240
Name (Basic Wall:SS-01.240:...) | In | ExtendToStructure
207529 | 1K | no
213124 | 3K | yes
213193 | 4K | yes
213216 | 5K | no
491676 | 1K | no

# IfcWallStandardCase: Basic Wall:SS-03. Šahti sein (55)
Type - PredefinedType: STANDARD; Material: _K. Väisviimistlus. Krohv. Valge 10 mm, _K. Müüritis. Väikeplokk. Kergkruusplokk 150 mm, _K. Väisviimistlus. Krohv. Valge 10 mm
Pset_QuantityTakeOff - Reference: SS-03. Šahti sein; sets with these values: 2
Pset_WallCommon - IsExternal: no; LoadBearing: no; Reference: SS-03. Šahti sein
Name (Basic Wall:SS-03. Šahti sein:...) | In | ExtendToStructure
278723 | 2K | no
278780 | 2K | no
278872 | 2K | no
280336 | 2K | no
280337 | 2K | no
280482 | 2K | no
281139 | 2K | no
281140 | 2K | no
281214 | 2K | no
282462 | 2K | no
282463 | 2K | no
283235 | 2K | no
283236 | 2K | no
285316 | 3K | no
285317 | 3K | no
285318 | 3K | no
285326 | 3K | no
285327 | 3K | no
285328 | 3K | no
285333 | 3K | no
285337 | 3K | no
285338 | 3K | no
285339 | 3K | no
285343 | 3K | no
286635 | 4K | no
286636 | 4K | no
286637 | 4K | no
287544 | 4K | no
287545 | 4K | no
287646 | 4K | no
288368 | 4K | no
288369 | 4K | no
288538 | 4K | no
288539 | 4K | no
289656 | 4K | no
290871 | 4K | no
292331 | 5K | no
292332 | 5K | no
292333 | 5K | no
292334 | 5K | no
292336 | 5K | no
292338 | 5K | no
292339 | 5K | no
292345 | 5K | no
292422 | 5K | no
293410 | 5K | no
293560 | 5K | no
345416 | 1K | no
345417 | 1K | no
345418 | 1K | no
345421 | 1K | no
346671 | 1K | no
495713 | 1K | yes
509441 | 5K | no
514685 | 5K | no

# IfcWallStandardCase: Basic Wall:SS-07. Panipaik (12)
In: 1K
Type - PredefinedType: STANDARD; Material: _K. Ehitusplaat. Vineer 12 mm, _K. Puit. Peitsitud ja lakitud 70 mm
Pset_QuantityTakeOff - Reference: SS-07. Panipaik; sets with these values: 2
Pset_WallCommon - IsExternal: no; ExtendToStructure: no; LoadBearing: no; Reference: SS-07. Panipaik
Name (Basic Wall:SS-07. Panipaik:...)
489526
489669
489760
489814
489823
489919
490019
490121
490122
490123
490321
490322

# IfcWallStandardCase: Basic Wall:SS-401 (75)
Type - PredefinedType: STANDARD; Material: _K. Ehitusplaat. Kipsplaat. Erikõva 13 mm, _K. Soojustus. Mineraalvill 66 mm, _K. Ehitusplaat. Kipsplaat. Erikõva 13 mm
Pset_QuantityTakeOff - Reference: SS-401; sets with these values: 2
Pset_WallCommon - IsExternal: no; ExtendToStructure: no; LoadBearing: no; Reference: SS-401
Name (Basic Wall:SS-401:...) | In
276685 | 2K
276828 | 2K
278318 | 2K
279296 | 2K
280107 | 2K
280653 | 2K
280773 | 2K
280908 | 2K
281374 | 2K
282628 | 2K
282821 | 2K
283477 | 2K
283540 | 2K
283700 | 2K
283812 | 2K
284174 | 2K
284323 | 2K
284446 | 2K
284533 | 2K
284670 | 2K
285307 | 3K
285308 | 3K
285315 | 3K
285322 | 3K
285325 | 3K
285329 | 3K
285330 | 3K
285331 | 3K
285336 | 3K
285340 | 3K
285341 | 3K
285342 | 3K
285351 | 3K
285352 | 3K
285353 | 3K
285354 | 3K
285355 | 3K
285356 | 3K
285357 | 3K
285358 | 3K
286638 | 4K
286639 | 4K
286696 | 4K
287069 | 4K
289459 | 4K
290950 | 4K
290952 | 4K
291022 | 4K
291431 | 4K
291497 | 4K
291650 | 4K
292214 | 5K
292215 | 5K
292507 | 5K
292577 | 5K
292690 | 5K
292691 | 5K
292895 | 5K
292978 | 5K
293115 | 5K
293668 | 5K
293731 | 5K
293853 | 5K
294087 | 5K
294294 | 5K
294435 | 5K
294544 | 5K
294632 | 5K
294777 | 5K
294891 | 5K
295129 | 5K
510145 | 5K
510236 | 5K
536169 | 2K
537616 | 3K

# IfcWallStandardCase: Basic Wall:SS-402 (20)
Type - PredefinedType: STANDARD; Material: _K. Ehitusplaat. Kipsplaat. Erikõva 13 mm, _K. Soojustus. Mineraalvill 66 mm
Pset_QuantityTakeOff - Reference: SS-402; sets with these values: 2
Pset_WallCommon - IsExternal: no; ExtendToStructure: no; LoadBearing: no; Reference: SS-402
Name (Basic Wall:SS-402:...) | In
277096 | 2K
277304 | 2K
277389 | 2K
277707 | 2K
277708 | 2K
279086 | 2K
279087 | 2K
285309 | 3K
285310 | 3K
285311 | 3K
285312 | 3K
285313 | 3K
285319 | 3K
285320 | 3K
288988 | 4K
288989 | 4K
289204 | 4K
289712 | 4K
289713 | 4K
289775 | 4K

# IfcWallStandardCase: Basic Wall:SS-403 (17)
Type - PredefinedType: STANDARD; Material: _K. Ehitusplaat. Kipsplaat. Erikõva 13 mm, _K. Õhk. Roov. Fassaadikatte alusroov. Vertikaalne. 25 mm 200 mm
Pset_QuantityTakeOff - Reference: SS-403; sets with these values: 2
Pset_WallCommon - IsExternal: no; ExtendToStructure: no; LoadBearing: no; Reference: SS-403
Name (Basic Wall:SS-403:...) | In
534823 | 2K
534997 | 2K
535282 | 2K
535449 | 2K
535603 | 2K
537729 | 3K
537730 | 3K
537731 | 3K
537732 | 3K
537733 | 3K
537805 | 4K
538005 | 4K
538191 | 4K
538192 | 4K
551220 | 5K
551417 | 5K
663299 | 5K

# IfcWallStandardCase: Basic Wall:VS-00 (6)
In: 1K
Type - PredefinedType: STANDARD; Material: _K. Ehitusplaat. Tsementkiudplaat. Must 10 mm, _K. Õhk. Roov. Fassaadikatte alusroov. Vertikaalne. 25 mm 16 mm, _K. Soojustus. EPS Silver 150 mm
Pset_QuantityTakeOff - Reference: VS-00; sets with these values: 2
Pset_WallCommon - IsExternal: no; ExtendToStructure: no; LoadBearing: no; Reference: VS-00
Name (Basic Wall:VS-00:...)
524253
524325
524453
524508
524769
524887

# IfcWallStandardCase: Basic Wall:VS-01 (28)
Type - PredefinedType: STANDARD; Material: _K. Väisviimistlus. Krohv. Valge 10 mm, _K. Soojustus. EPS Silver 230 mm
Pset_QuantityTakeOff - Reference: VS-01; sets with these values: 2
Pset_WallCommon - IsExternal: no; LoadBearing: no; Reference: VS-01
Name (Basic Wall:VS-01:...) | In | ExtendToStructure
218073 | 2K | no
218079 | 2K | no
218085 | 2K | no
218091 | 2K | no
218176 | 2K | no
218291 | 3K | no
218292 | 3K | no
218293 | 3K | no
218294 | 3K | no
218295 | 3K | no
218296 | 3K | no
218297 | 3K | no
218298 | 3K | yes
218345 | 4K | no
218347 | 4K | no
218348 | 4K | no
218349 | 4K | no
218350 | 4K | no
218445 | 5K | no
218449 | 5K | no
218450 | 5K | no
218451 | 5K | no
218452 | 5K | no
218618 | 1K | no
218807 | 1K | no
218873 | 1K | no
219050 | 1K | no
763647 | 4K | no

# IfcWallStandardCase: Basic Wall:VS-01 krohv (3)
Type - PredefinedType: STANDARD; Material: _K. Väisviimistlus. Krohv. Valge 10 mm
Pset_QuantityTakeOff - Reference: VS-01 krohv; sets with these values: 2
Pset_WallCommon - IsExternal: no; ExtendToStructure: no; LoadBearing: no; Reference: VS-01 krohv
Name (Basic Wall:VS-01 krohv:...) | In
358104 | 4K
765034 | 5K
765101 | 5K

# IfcWallStandardCase: Basic Wall:VS-Rõdu parapet (9)
Type - PredefinedType: STANDARD; Material: _K. Katusekate. Rullmaterjal. SBS 10 mm, _K. Ehitusplaat. Vineer. Veekindel 15 mm
Pset_QuantityTakeOff - Reference: VS-Rõdu parapet; sets with these values: 2
Pset_WallCommon - IsExternal: no; ExtendToStructure: no; LoadBearing: no; Reference: VS-Rõdu parapet
Name (Basic Wall:VS-Rõdu parapet:...) | In
475978 | 4K
476132 | 4K
476262 | 4K
476541 | Parapet
476542 | Parapet
476543 | Parapet
478331 | 5K
478332 | 5K
478333 | 5K

# IfcWallStandardCase: Basic Wall:VS-Tala, Basic Wall:VS-Tala:527861
In: 1K
Type - PredefinedType: STANDARD; Material: _K. Välisviimistlus. Alumiinium-komposiitplaat. Must 4 mm, _K. Soojustus. Mineraalvill 250 mm
Pset_QuantityTakeOff - Reference: VS-Tala; sets with these values: 2
Pset_WallCommon - IsExternal: no; ExtendToStructure: no; LoadBearing: no; Reference: VS-Tala

# IfcWallStandardCase: Basic Wall:VS-komposiit (12)
Type - PredefinedType: STANDARD
Material: _K. Välisviimistlus. Alumiinium-komposiitplaat 4 mm, _K. Õhk. Roov. Fassaadikatte alusroov. Horisontaalne. 25 mm 16 mm
Pset_QuantityTakeOff - Reference: VS-komposiit; sets with these values: 2
Pset_WallCommon - IsExternal: no; LoadBearing: no; Reference: VS-komposiit
Name (Basic Wall:VS-komposiit:...) | In | ExtendToStructure
431556 | 2K | no
432019 | 3K | no
432145 | 4K | yes
477337 | 2K | no
477839 | 3K | no
477841 | 4K | no
477843 | 5K | no
477929 | Parapet | no
478340 | 5K | no
479148 | 2K | no
479150 | 3K | no
479152 | 4K | no

# IfcWallStandardCase: Basic Wall:VS-liftimüts (2)
In: Parapet
Type - PredefinedType: STANDARD; Material: _K. Katusekate. Rullmaterjal. SBS 10 mm, _K. Soojustus. Mineraalvill 30 mm, _K. Soojustus. EPS 170 mm
Pset_QuantityTakeOff - Reference: VS-liftimüts; sets with these values: 2
Pset_WallCommon - IsExternal: no; ExtendToStructure: no; LoadBearing: no; Reference: VS-liftimüts
Name (Basic Wall:VS-liftimüts:...)
266903
266983

# IfcWallStandardCase: Basic Wall:VS-liftimüts 2, Basic Wall:VS-liftimüts 2:266734
In: Parapet
Type - PredefinedType: STANDARD; Material: _K. Katusekate. Rullmaterjal. SBS 10 mm, _K. Soojustus. Mineraalvill 30 mm, _K. Soojustus. EPS 200 mm
Pset_QuantityTakeOff - Reference: VS-liftimüts 2; sets with these values: 2
Pset_WallCommon - IsExternal: no; ExtendToStructure: no; LoadBearing: no; Reference: VS-liftimüts 2

# IfcWallStandardCase: Basic Wall:VS-Šahtimüts (19)
In: Parapet
Type - PredefinedType: STANDARD; Material: _K. Katusekate. Rullmaterjal. SBS 10 mm, _K. Soojustus. Mineraalvill 100 mm, _K. Müüritis. Väikeplokk. Kergkruusplokk 100 mm
Pset_QuantityTakeOff - Reference: VS-Šahtimüts; sets with these values: 2
Pset_WallCommon - IsExternal: no; ExtendToStructure: no; LoadBearing: no; Reference: VS-Šahtimüts
Name (Basic Wall:VS-Šahtimüts:...)
271336
271337
271338
271339
272512
272513
272514
272515
272634
272635
272636
272637
272758
272809
272810
272811
272824
272825
272827

# IfcWindow: HR_Louver_Rectangle_v1:150x150 (2)
In: 2K
Type - ParameterTakesPrecedence: no; Sizeable: no; Material: _K. Metall. Plekk. Värvitud. Valge
OverallHeight: 150 mm; OverallWidth: 150 mm
Pset_QuantityTakeOff - Reference: 150x150
Pset_WindowCommon - IsExternal: no; Reference: 150x150
Name (HR_Louver_Rectangle_v1:150x150:...)
364631
365898

# IfcWindow: HR_Louver_Rectangle_v1:300x300 (2)
Type - ParameterTakesPrecedence: no; Sizeable: no; Material: _K. Metall. Plekk. Värvitud. Valge
OverallHeight: 300 mm; OverallWidth: 300 mm
Pset_QuantityTakeOff - Reference: 300x300
Pset_WindowCommon - IsExternal: no; Reference: 300x300
Name (HR_Louver_Rectangle_v1:300x300:...) | In
364515 | 5K
364573 | 4K

# IfcWindow: HR_Window_Generic_Rectangle_1x1:A-01.400x2400.ma (48)
Type - ParameterTakesPrecedence: no; Sizeable: no; Material: _K. Avatäited. Raam. PVC. Valge, _K. Klaas. Pakett, _K. Avatäited. Raam. PVC. RAL9005
OverallHeight: 2465 mm; OverallWidth: 400 mm
Pset_QuantityTakeOff - Reference: A-01.400x2400.ma
Pset_WindowCommon - IsExternal: no; Reference: A-01.400x2400.ma
Name (HR_Window_Generic_Rectangle_1x1:A-01.400x2400.ma:...) | In
234803 | 2K
244659 | 2K
245288 | 2K
245514 | 2K
245556 | 2K
245632 | 2K
245720 | 2K
245808 | 2K
245862 | 2K
245934 | 2K
246026 | 2K
246074 | 2K
246146 | 2K
249635 | 4K
249787 | 4K
249967 | 4K
250121 | 4K
250339 | 4K
250463 | 4K
250573 | 4K
250635 | 4K
250841 | 4K
250915 | 4K
250963 | 4K
251940 | 5K
252282 | 5K
252346 | 5K
252516 | 5K
252620 | 5K
252672 | 5K
252764 | 5K
252806 | 5K
285709 | 3K
285710 | 3K
285711 | 3K
285712 | 3K
285713 | 3K
285714 | 3K
285715 | 3K
285716 | 3K
285717 | 3K
285719 | 3K
285720 | 3K
285721 | 3K
285722 | 3K
347893 | 4K
348073 | 3K
348144 | 2K

# IfcWindow: HR_Window_Generic_Rectangle_1x1:A-02. 800x2400. ma (10)
Type - ParameterTakesPrecedence: no; Sizeable: no; Material: _K. Avatäited. Raam. PVC. Valge, _K. Klaas. Pakett, _K. Avatäited. Raam. PVC. RAL9005
OverallHeight: 2465 mm; OverallWidth: 800 mm
Pset_QuantityTakeOff - Reference: A-02. 800x2400. ma
Pset_WindowCommon - IsExternal: no; Reference: A-02. 800x2400. ma
Name (HR_Window_Generic_Rectangle_1x1:A-02. 800x2400. ma:...) | In
244703 | 2K
245335 | 2K
246849 | 2K
249887 | 4K
250171 | 4K
252126 | 5K
253426 | 5K
253570 | 5K
285697 | 3K
285703 | 3K

# IfcWindow: HR_Window_Generic_Rectangle_1x1:A-03.1200x2400.ma (3)
Type - ParameterTakesPrecedence: no; Sizeable: no; Material: _K. Avatäited. Raam. PVC. Valge, _K. Klaas. Pakett, _K. Avatäited. Raam. PVC. RAL9005
OverallHeight: 2465 mm; OverallWidth: 1200 mm
Pset_QuantityTakeOff - Reference: A-03.1200x2400.ma
Pset_WindowCommon - IsExternal: no; Reference: A-03.1200x2400.ma
Name (HR_Window_Generic_Rectangle_1x1:A-03.1200x2400.ma:...) | In
252198 | 5K
254355 | 5K
346814 | 1K

# IfcWindow: HR_Window_Generic_Rectangle_1x1:A-04.1600x2400.ma (5)
Type - ParameterTakesPrecedence: no; Sizeable: no; Material: _K. Avatäited. Raam. PVC. Valge, _K. Klaas. Pakett, _K. Avatäited. Raam. PVC. RAL9005
OverallHeight: 2465 mm; OverallWidth: 1600 mm
Pset_QuantityTakeOff - Reference: A-04.1600x2400.ma
Pset_WindowCommon - IsExternal: no; Reference: A-04.1600x2400.ma
Name (HR_Window_Generic_Rectangle_1x1:A-04.1600x2400.ma:...) | In
245384 | 2K
246644 | 2K
252830 | 5K
254296 | 5K
285708 | 3K

# IfcWindow: HR_Window_Generic_Rectangle_1x1:A-06.1600x2250.ma, HR_Window_Generic_Rectangle_1x1:A-06.1600x2250.ma:254209
In: 4K
Type - ParameterTakesPrecedence: no; Sizeable: no; Material: _K. Avatäited. Raam. PVC. Valge, _K. Klaas. Pakett, _K. Avatäited. Raam. PVC. RAL9005
OverallHeight: 2315 mm; OverallWidth: 1600 mm
Pset_QuantityTakeOff - Reference: A-06.1600x2250.ma
Pset_WindowCommon - IsExternal: no; Reference: A-06.1600x2250.ma

# IfcWindow: HR_Window_Generic_Rectangle_1x1:A-07.2000x2250.ma, HR_Window_Generic_Rectangle_1x1:A-07.2000x2250.ma:253994
In: 4K
Type - ParameterTakesPrecedence: no; Sizeable: no; Material: _K. Avatäited. Raam. PVC. Valge, _K. Klaas. Pakett, _K. Avatäited. Raam. PVC. RAL9005
OverallHeight: 2315 mm; OverallWidth: 2000 mm
Pset_QuantityTakeOff - Reference: A-07.2000x2250.ma
Pset_WindowCommon - IsExternal: no; Reference: A-07.2000x2250.ma

# IfcWindow: HR_Window_Generic_Rectangle_1x1:A-08.400x2115.P, HR_Window_Generic_Rectangle_1x1:A-08.400x2115.P:255355
In: 1K
Type - ParameterTakesPrecedence: no; Sizeable: no; Material: _K. Klaas. Pakett, _K. Avatäited. Raam. PVC. RAL9005
OverallHeight: 2180 mm; OverallWidth: 400 mm
Pset_QuantityTakeOff - Reference: A-08.400x2115.P
Pset_WindowCommon - IsExternal: no; Reference: A-08.400x2115.P

# IfcWindow: HR_Window_Generic_Rectangle_1x1:A-09.800x2400.V (4)
Type - ParameterTakesPrecedence: no; Sizeable: no; Material: _K. Klaas. Pakett, _K. Avatäited. Raam. PVC. RAL9005
OverallHeight: 2465 mm; OverallWidth: 800 mm
Pset_QuantityTakeOff - Reference: A-09.800x2400.V
Pset_WindowCommon - IsExternal: no; Reference: A-09.800x2400.V
Name (HR_Window_Generic_Rectangle_1x1:A-09.800x2400.V:...) | In
244961 | 2K
252914 | 5K
253082 | 5K
285699 | 3K

# IfcWindow: HR_Window_Generic_Rectangle_1x1:A-10.800x2400.P (12)
Type - ParameterTakesPrecedence: no; Sizeable: no; Material: _K. Klaas. Pakett, _K. Avatäited. Raam. PVC. RAL9005
OverallHeight: 2465 mm; OverallWidth: 800 mm
Pset_QuantityTakeOff - Reference: A-10.800x2400.P
Pset_WindowCommon - IsExternal: no; Reference: A-10.800x2400.P
Name (HR_Window_Generic_Rectangle_1x1:A-10.800x2400.P:...) | In
244837 | 2K
246914 | 2K
249735 | 4K
250245 | 4K
252398 | 5K
252476 | 5K
252972 | 5K
253281 | 5K
276954 | 2K
285698 | 3K
285704 | 3K
285707 | 3K

# IfcWindow: HR_Window_Generic_Rectangle_1x1:A-12.800x2250.P (2)
In: 4K
Type - ParameterTakesPrecedence: no; Sizeable: no; Material: _K. Klaas. Pakett, _K. Avatäited. Raam. PVC. RAL9005
OverallHeight: 2315 mm; OverallWidth: 800 mm
Pset_QuantityTakeOff - Reference: A-12.800x2250.P
Pset_WindowCommon - IsExternal: no; Reference: A-12.800x2250.P
Name (HR_Window_Generic_Rectangle_1x1:A-12.800x2250.P:...)
251065
251131

# IfcWindow: HR_Window_Generic_Rectangle_1x1:A-16.400x2400.P, HR_Window_Generic_Rectangle_1x1:A-16.400x2400.P:351045
In: 1K
Type - ParameterTakesPrecedence: no; Sizeable: no; Material: _K. Klaas. Pakett, _K. Avatäited. Raam. PVC. RAL9005
OverallHeight: 2465 mm; OverallWidth: 400 mm
Pset_QuantityTakeOff - Reference: A-16.400x2400.P
Pset_WindowCommon - IsExternal: no; Reference: A-16.400x2400.P

# IfcWindow: HR_Window_Generic_Rectangle_1x2:A-13.1200x2400.P (21)
Type - ParameterTakesPrecedence: no; Sizeable: no; Material: _K. Klaas. Pakett, _K. Avatäited. Raam. PVC. RAL9005, _K. Avatäited. Raam. PVC. Valge
OverallHeight: 2465 mm; OverallWidth: 1200 mm
Pset_QuantityTakeOff - Reference: A-13.1200x2400.P
Pset_WindowCommon - IsExternal: no; Reference: A-13.1200x2400.P
Name (HR_Window_Generic_Rectangle_1x2:A-13.1200x2400.P:...) | In
234470 | 2K
234731 | 2K
245230 | 2K
246388 | 2K
246436 | 2K
246540 | 2K
249619 | 4K
249853 | 4K
250023 | 4K
250069 | 4K
250543 | 4K
250709 | 4K
252732 | 5K
253056 | 5K
285695 | 3K
285696 | 3K
285700 | 3K
285701 | 3K
285702 | 3K
285705 | 3K
285706 | 3K

# IfcWindow: HR_Window_Generic_Rectangle_1x2:A-15.400x2400.ma (3)
Type - ParameterTakesPrecedence: no; Sizeable: no; Material: _K. Avatäited. Raam. PVC. Valge, _K. Klaas. Pakett, _K. Avatäited. Raam. PVC. RAL9005
OverallHeight: 2465 mm; OverallWidth: 400 mm
Pset_QuantityTakeOff - Reference: A-15.400x2400.ma
Pset_WindowCommon - IsExternal: no; Reference: A-15.400x2400.ma
Name (HR_Window_Generic_Rectangle_1x2:A-15.400x2400.ma:...) | In
247127 | 2K
250789 | 4K
285718 | 3K

# IfcWindow: Infill_Glazing_W-ALU_Rectangle_Triple:Fixed. Tumm (3)
Type - ParameterTakesPrecedence: no; Sizeable: no; Material: _K. Avatäited. Raam. PVC. RAL9005
OverallHeight: 112 mm; OverallWidth: 261 mm
Pset_QuantityTakeOff - Reference: Fixed. Tumm
Pset_WindowCommon - IsExternal: no; Reference: Fixed. Tumm
Name (Infill_Glazing_W-ALU_Rectangle_Triple:Fixed. Tumm:...) | In
420778 | 2K
421387 | 3K
421388 | 4K

# IfcWindow: Orivent 01:900 x 1800, Orivent 01:900 x 1800:265497
In: Parapet
Type - ParameterTakesPrecedence: no; Sizeable: no; Material: RR 20, PC_Clear
Type - Pset_ManufacturerTypeInformation - Manufacturer: Kera Group Oy
Type - Pset_WindowCommon - FireRating: B 300
OverallHeight: 2075.75 mm; OverallWidth: 1175.75 mm; Material: PC_Clear, RR 20, Default
Pset_QuantityTakeOff - Reference: 900 x 1800
Pset_WindowCommon - IsExternal: yes; Reference: 900 x 1800
